VERSION 5.8 ;
BUSBITCHARS "[]" ;
DIVIDERCHAR "/" ;
UNITS
    DATABASE MICRONS 1000 ;
END UNITS

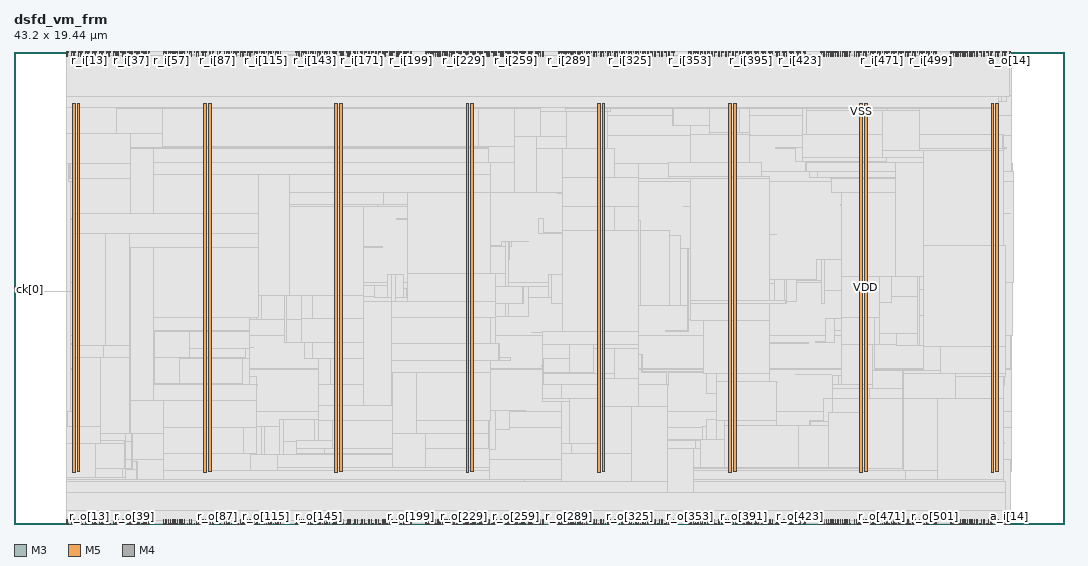
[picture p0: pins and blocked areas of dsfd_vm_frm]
MACRO dsfd_vm_frm
  FOREIGN dsfd_vm_frm 0 0 ;
  CLASS BLOCK ;
  SIZE 43.2 BY 19.44 ;
  PIN a_i[0]
    DIRECTION INPUT ;
    USE SIGNAL ;
    PORT
      LAYER M3 ;
        RECT  40.032 0 40.05 0.038 ;
    END
  END a_i[0]
  PIN a_i[10]
    DIRECTION INPUT ;
    USE SIGNAL ;
    PORT
      LAYER M3 ;
        RECT  40.68 0 40.698 0.038 ;
    END
  END a_i[10]
  PIN a_i[11]
    DIRECTION INPUT ;
    USE SIGNAL ;
    PORT
      LAYER M5 ;
        RECT  40.752 0 40.776 0.192 ;
    END
  END a_i[11]
  PIN a_i[12]
    DIRECTION INPUT ;
    USE SIGNAL ;
    PORT
      LAYER M3 ;
        RECT  40.824 0 40.842 0.038 ;
    END
  END a_i[12]
  PIN a_i[13]
    DIRECTION INPUT ;
    USE SIGNAL ;
    PORT
      LAYER M5 ;
        RECT  40.944 0 40.968 0.192 ;
    END
  END a_i[13]
  PIN a_i[14]
    DIRECTION INPUT ;
    USE SIGNAL ;
    PORT
      LAYER M3 ;
        RECT  40.968 0 40.986 0.038 ;
    END
  END a_i[14]
  PIN a_i[1]
    DIRECTION INPUT ;
    USE SIGNAL ;
    PORT
      LAYER M5 ;
        RECT  40.08 0 40.104 0.192 ;
    END
  END a_i[1]
  PIN a_i[2]
    DIRECTION INPUT ;
    USE SIGNAL ;
    PORT
      LAYER M3 ;
        RECT  40.176 0 40.194 0.038 ;
    END
  END a_i[2]
  PIN a_i[3]
    DIRECTION INPUT ;
    USE SIGNAL ;
    PORT
      LAYER M5 ;
        RECT  40.176 0 40.2 0.192 ;
    END
  END a_i[3]
  PIN a_i[4]
    DIRECTION INPUT ;
    USE SIGNAL ;
    PORT
      LAYER M3 ;
        RECT  40.248 0 40.266 0.038 ;
    END
  END a_i[4]
  PIN a_i[5]
    DIRECTION INPUT ;
    USE SIGNAL ;
    PORT
      LAYER M5 ;
        RECT  40.368 0 40.392 0.192 ;
    END
  END a_i[5]
  PIN a_i[6]
    DIRECTION INPUT ;
    USE SIGNAL ;
    PORT
      LAYER M3 ;
        RECT  40.392 0 40.41 0.038 ;
    END
  END a_i[6]
  PIN a_i[7]
    DIRECTION INPUT ;
    USE SIGNAL ;
    PORT
      LAYER M5 ;
        RECT  40.464 0 40.488 0.192 ;
    END
  END a_i[7]
  PIN a_i[8]
    DIRECTION INPUT ;
    USE SIGNAL ;
    PORT
      LAYER M3 ;
        RECT  40.536 0 40.554 0.038 ;
    END
  END a_i[8]
  PIN a_i[9]
    DIRECTION INPUT ;
    USE SIGNAL ;
    PORT
      LAYER M5 ;
        RECT  40.656 0 40.68 0.192 ;
    END
  END a_i[9]
  PIN a_o[0]
    DIRECTION OUTPUT ;
    USE SIGNAL ;
    PORT
      LAYER M3 ;
        RECT  40.032 19.402 40.05 19.44 ;
    END
  END a_o[0]
  PIN a_o[10]
    DIRECTION OUTPUT ;
    USE SIGNAL ;
    PORT
      LAYER M3 ;
        RECT  40.68 19.402 40.698 19.44 ;
    END
  END a_o[10]
  PIN a_o[11]
    DIRECTION OUTPUT ;
    USE SIGNAL ;
    PORT
      LAYER M5 ;
        RECT  40.752 19.248 40.776 19.44 ;
    END
  END a_o[11]
  PIN a_o[12]
    DIRECTION OUTPUT ;
    USE SIGNAL ;
    PORT
      LAYER M3 ;
        RECT  40.824 19.402 40.842 19.44 ;
    END
  END a_o[12]
  PIN a_o[13]
    DIRECTION OUTPUT ;
    USE SIGNAL ;
    PORT
      LAYER M5 ;
        RECT  40.944 19.248 40.968 19.44 ;
    END
  END a_o[13]
  PIN a_o[14]
    DIRECTION OUTPUT ;
    USE SIGNAL ;
    PORT
      LAYER M3 ;
        RECT  40.968 19.402 40.986 19.44 ;
    END
  END a_o[14]
  PIN a_o[1]
    DIRECTION OUTPUT ;
    USE SIGNAL ;
    PORT
      LAYER M5 ;
        RECT  40.08 19.248 40.104 19.44 ;
    END
  END a_o[1]
  PIN a_o[2]
    DIRECTION OUTPUT ;
    USE SIGNAL ;
    PORT
      LAYER M3 ;
        RECT  40.176 19.402 40.194 19.44 ;
    END
  END a_o[2]
  PIN a_o[3]
    DIRECTION OUTPUT ;
    USE SIGNAL ;
    PORT
      LAYER M5 ;
        RECT  40.176 19.248 40.2 19.44 ;
    END
  END a_o[3]
  PIN a_o[4]
    DIRECTION OUTPUT ;
    USE SIGNAL ;
    PORT
      LAYER M3 ;
        RECT  40.248 19.402 40.266 19.44 ;
    END
  END a_o[4]
  PIN a_o[5]
    DIRECTION OUTPUT ;
    USE SIGNAL ;
    PORT
      LAYER M5 ;
        RECT  40.368 19.248 40.392 19.44 ;
    END
  END a_o[5]
  PIN a_o[6]
    DIRECTION OUTPUT ;
    USE SIGNAL ;
    PORT
      LAYER M3 ;
        RECT  40.392 19.402 40.41 19.44 ;
    END
  END a_o[6]
  PIN a_o[7]
    DIRECTION OUTPUT ;
    USE SIGNAL ;
    PORT
      LAYER M5 ;
        RECT  40.464 19.248 40.488 19.44 ;
    END
  END a_o[7]
  PIN a_o[8]
    DIRECTION OUTPUT ;
    USE SIGNAL ;
    PORT
      LAYER M3 ;
        RECT  40.536 19.402 40.554 19.44 ;
    END
  END a_o[8]
  PIN a_o[9]
    DIRECTION OUTPUT ;
    USE SIGNAL ;
    PORT
      LAYER M5 ;
        RECT  40.656 19.248 40.68 19.44 ;
    END
  END a_o[9]
  PIN ck[0]
    DIRECTION INPUT ;
    USE SIGNAL ;
    PORT
      LAYER M4 ;
        RECT  0 9.744 0.192 9.768 ;
    END
    PORT
      LAYER M4 ;
        RECT  0.156 9.744 0.181 9.768 ;
    END
    PORT
      LAYER M4 ;
        RECT  0.181 9.552 0.227 9.768 ;
    END
  END ck[0]
  PIN f_i[0]
    DIRECTION INPUT ;
    USE SIGNAL ;
    PORT
      LAYER M5 ;
        RECT  39.6 19.248 39.624 19.44 ;
    END
  END f_i[0]
  PIN f_i[1]
    DIRECTION INPUT ;
    USE SIGNAL ;
    PORT
      LAYER M3 ;
        RECT  39.744 19.402 39.762 19.44 ;
    END
  END f_i[1]
  PIN f_i[2]
    DIRECTION INPUT ;
    USE SIGNAL ;
    PORT
      LAYER M5 ;
        RECT  39.792 19.248 39.816 19.44 ;
    END
  END f_i[2]
  PIN f_i[3]
    DIRECTION INPUT ;
    USE SIGNAL ;
    PORT
      LAYER M3 ;
        RECT  39.888 19.402 39.906 19.44 ;
    END
  END f_i[3]
  PIN f_o[0]
    DIRECTION OUTPUT ;
    USE SIGNAL ;
    PORT
      LAYER M5 ;
        RECT  39.6 0 39.624 0.192 ;
    END
  END f_o[0]
  PIN f_o[1]
    DIRECTION OUTPUT ;
    USE SIGNAL ;
    PORT
      LAYER M3 ;
        RECT  39.744 0 39.762 0.038 ;
    END
  END f_o[1]
  PIN f_o[2]
    DIRECTION OUTPUT ;
    USE SIGNAL ;
    PORT
      LAYER M5 ;
        RECT  39.792 0 39.816 0.192 ;
    END
  END f_o[2]
  PIN f_o[3]
    DIRECTION OUTPUT ;
    USE SIGNAL ;
    PORT
      LAYER M3 ;
        RECT  39.888 0 39.906 0.038 ;
    END
  END f_o[3]
  PIN g_i[0]
    DIRECTION INPUT ;
    USE SIGNAL ;
    PORT
      LAYER M5 ;
        RECT  39.888 0 39.912 0.192 ;
    END
  END g_i[0]
  PIN g_o[0]
    DIRECTION OUTPUT ;
    USE SIGNAL ;
    PORT
      LAYER M5 ;
        RECT  39.888 19.248 39.912 19.44 ;
    END
  END g_o[0]
  PIN r_i[0]
    DIRECTION INPUT ;
    USE SIGNAL ;
    PORT
      LAYER M5 ;
        RECT  2.16 19.248 2.184 19.44 ;
    END
  END r_i[0]
  PIN r_i[100]
    DIRECTION INPUT ;
    USE SIGNAL ;
    PORT
      LAYER M5 ;
        RECT  9.312 19.248 9.336 19.44 ;
    END
  END r_i[100]
  PIN r_i[101]
    DIRECTION INPUT ;
    USE SIGNAL ;
    PORT
      LAYER M3 ;
        RECT  9.36 19.402 9.378 19.44 ;
    END
  END r_i[101]
  PIN r_i[102]
    DIRECTION INPUT ;
    USE SIGNAL ;
    PORT
      LAYER M5 ;
        RECT  9.408 19.248 9.432 19.44 ;
    END
  END r_i[102]
  PIN r_i[103]
    DIRECTION INPUT ;
    USE SIGNAL ;
    PORT
      LAYER M3 ;
        RECT  9.504 19.402 9.522 19.44 ;
    END
  END r_i[103]
  PIN r_i[104]
    DIRECTION INPUT ;
    USE SIGNAL ;
    PORT
      LAYER M5 ;
        RECT  9.6 19.248 9.624 19.44 ;
    END
  END r_i[104]
  PIN r_i[105]
    DIRECTION INPUT ;
    USE SIGNAL ;
    PORT
      LAYER M3 ;
        RECT  9.648 19.402 9.666 19.44 ;
    END
  END r_i[105]
  PIN r_i[106]
    DIRECTION INPUT ;
    USE SIGNAL ;
    PORT
      LAYER M5 ;
        RECT  9.696 19.248 9.72 19.44 ;
    END
  END r_i[106]
  PIN r_i[107]
    DIRECTION INPUT ;
    USE SIGNAL ;
    PORT
      LAYER M3 ;
        RECT  9.792 19.402 9.81 19.44 ;
    END
  END r_i[107]
  PIN r_i[108]
    DIRECTION INPUT ;
    USE SIGNAL ;
    PORT
      LAYER M5 ;
        RECT  9.888 19.248 9.912 19.44 ;
    END
  END r_i[108]
  PIN r_i[109]
    DIRECTION INPUT ;
    USE SIGNAL ;
    PORT
      LAYER M3 ;
        RECT  9.936 19.402 9.954 19.44 ;
    END
  END r_i[109]
  PIN r_i[10]
    DIRECTION INPUT ;
    USE SIGNAL ;
    PORT
      LAYER M5 ;
        RECT  2.928 19.248 2.952 19.44 ;
    END
  END r_i[10]
  PIN r_i[110]
    DIRECTION INPUT ;
    USE SIGNAL ;
    PORT
      LAYER M5 ;
        RECT  9.984 19.248 10.008 19.44 ;
    END
  END r_i[110]
  PIN r_i[111]
    DIRECTION INPUT ;
    USE SIGNAL ;
    PORT
      LAYER M3 ;
        RECT  10.08 19.402 10.098 19.44 ;
    END
  END r_i[111]
  PIN r_i[112]
    DIRECTION INPUT ;
    USE SIGNAL ;
    PORT
      LAYER M5 ;
        RECT  10.176 19.248 10.2 19.44 ;
    END
  END r_i[112]
  PIN r_i[113]
    DIRECTION INPUT ;
    USE SIGNAL ;
    PORT
      LAYER M3 ;
        RECT  10.224 19.402 10.242 19.44 ;
    END
  END r_i[113]
  PIN r_i[114]
    DIRECTION INPUT ;
    USE SIGNAL ;
    PORT
      LAYER M5 ;
        RECT  10.272 19.248 10.296 19.44 ;
    END
  END r_i[114]
  PIN r_i[115]
    DIRECTION INPUT ;
    USE SIGNAL ;
    PORT
      LAYER M3 ;
        RECT  10.368 19.402 10.386 19.44 ;
    END
  END r_i[115]
  PIN r_i[116]
    DIRECTION INPUT ;
    USE SIGNAL ;
    PORT
      LAYER M5 ;
        RECT  10.464 19.248 10.488 19.44 ;
    END
  END r_i[116]
  PIN r_i[117]
    DIRECTION INPUT ;
    USE SIGNAL ;
    PORT
      LAYER M3 ;
        RECT  10.512 19.402 10.53 19.44 ;
    END
  END r_i[117]
  PIN r_i[118]
    DIRECTION INPUT ;
    USE SIGNAL ;
    PORT
      LAYER M5 ;
        RECT  10.56 19.248 10.584 19.44 ;
    END
  END r_i[118]
  PIN r_i[119]
    DIRECTION INPUT ;
    USE SIGNAL ;
    PORT
      LAYER M3 ;
        RECT  10.656 19.402 10.674 19.44 ;
    END
  END r_i[119]
  PIN r_i[11]
    DIRECTION INPUT ;
    USE SIGNAL ;
    PORT
      LAYER M3 ;
        RECT  2.952 19.402 2.97 19.44 ;
    END
  END r_i[11]
  PIN r_i[120]
    DIRECTION INPUT ;
    USE SIGNAL ;
    PORT
      LAYER M5 ;
        RECT  10.752 19.248 10.776 19.44 ;
    END
  END r_i[120]
  PIN r_i[121]
    DIRECTION INPUT ;
    USE SIGNAL ;
    PORT
      LAYER M3 ;
        RECT  10.8 19.402 10.818 19.44 ;
    END
  END r_i[121]
  PIN r_i[122]
    DIRECTION INPUT ;
    USE SIGNAL ;
    PORT
      LAYER M5 ;
        RECT  10.848 19.248 10.872 19.44 ;
    END
  END r_i[122]
  PIN r_i[123]
    DIRECTION INPUT ;
    USE SIGNAL ;
    PORT
      LAYER M3 ;
        RECT  10.944 19.402 10.962 19.44 ;
    END
  END r_i[123]
  PIN r_i[124]
    DIRECTION INPUT ;
    USE SIGNAL ;
    PORT
      LAYER M5 ;
        RECT  10.944 19.248 10.968 19.44 ;
    END
  END r_i[124]
  PIN r_i[125]
    DIRECTION INPUT ;
    USE SIGNAL ;
    PORT
      LAYER M3 ;
        RECT  11.592 19.402 11.61 19.44 ;
    END
  END r_i[125]
  PIN r_i[126]
    DIRECTION INPUT ;
    USE SIGNAL ;
    PORT
      LAYER M5 ;
        RECT  11.616 19.248 11.64 19.44 ;
    END
  END r_i[126]
  PIN r_i[127]
    DIRECTION INPUT ;
    USE SIGNAL ;
    PORT
      LAYER M3 ;
        RECT  11.664 19.402 11.682 19.44 ;
    END
  END r_i[127]
  PIN r_i[128]
    DIRECTION INPUT ;
    USE SIGNAL ;
    PORT
      LAYER M5 ;
        RECT  11.712 19.248 11.736 19.44 ;
    END
  END r_i[128]
  PIN r_i[129]
    DIRECTION INPUT ;
    USE SIGNAL ;
    PORT
      LAYER M3 ;
        RECT  11.736 19.402 11.754 19.44 ;
    END
  END r_i[129]
  PIN r_i[12]
    DIRECTION INPUT ;
    USE SIGNAL ;
    PORT
      LAYER M5 ;
        RECT  3.024 19.248 3.048 19.44 ;
    END
  END r_i[12]
  PIN r_i[130]
    DIRECTION INPUT ;
    USE SIGNAL ;
    PORT
      LAYER M5 ;
        RECT  11.808 19.248 11.832 19.44 ;
    END
  END r_i[130]
  PIN r_i[131]
    DIRECTION INPUT ;
    USE SIGNAL ;
    PORT
      LAYER M3 ;
        RECT  11.808 19.402 11.826 19.44 ;
    END
  END r_i[131]
  PIN r_i[132]
    DIRECTION INPUT ;
    USE SIGNAL ;
    PORT
      LAYER M5 ;
        RECT  11.904 19.248 11.928 19.44 ;
    END
  END r_i[132]
  PIN r_i[133]
    DIRECTION INPUT ;
    USE SIGNAL ;
    PORT
      LAYER M3 ;
        RECT  11.88 19.402 11.898 19.44 ;
    END
  END r_i[133]
  PIN r_i[134]
    DIRECTION INPUT ;
    USE SIGNAL ;
    PORT
      LAYER M5 ;
        RECT  12 19.248 12.024 19.44 ;
    END
  END r_i[134]
  PIN r_i[135]
    DIRECTION INPUT ;
    USE SIGNAL ;
    PORT
      LAYER M3 ;
        RECT  11.952 19.402 11.97 19.44 ;
    END
  END r_i[135]
  PIN r_i[136]
    DIRECTION INPUT ;
    USE SIGNAL ;
    PORT
      LAYER M5 ;
        RECT  12.096 19.248 12.12 19.44 ;
    END
  END r_i[136]
  PIN r_i[137]
    DIRECTION INPUT ;
    USE SIGNAL ;
    PORT
      LAYER M3 ;
        RECT  12.024 19.402 12.042 19.44 ;
    END
  END r_i[137]
  PIN r_i[138]
    DIRECTION INPUT ;
    USE SIGNAL ;
    PORT
      LAYER M5 ;
        RECT  12.192 19.248 12.216 19.44 ;
    END
  END r_i[138]
  PIN r_i[139]
    DIRECTION INPUT ;
    USE SIGNAL ;
    PORT
      LAYER M3 ;
        RECT  12.096 19.402 12.114 19.44 ;
    END
  END r_i[139]
  PIN r_i[13]
    DIRECTION INPUT ;
    USE SIGNAL ;
    PORT
      LAYER M3 ;
        RECT  3.096 19.402 3.114 19.44 ;
    END
  END r_i[13]
  PIN r_i[140]
    DIRECTION INPUT ;
    USE SIGNAL ;
    PORT
      LAYER M5 ;
        RECT  12.288 19.248 12.312 19.44 ;
    END
  END r_i[140]
  PIN r_i[141]
    DIRECTION INPUT ;
    USE SIGNAL ;
    PORT
      LAYER M3 ;
        RECT  12.24 19.402 12.258 19.44 ;
    END
  END r_i[141]
  PIN r_i[142]
    DIRECTION INPUT ;
    USE SIGNAL ;
    PORT
      LAYER M5 ;
        RECT  12.384 19.248 12.408 19.44 ;
    END
  END r_i[142]
  PIN r_i[143]
    DIRECTION INPUT ;
    USE SIGNAL ;
    PORT
      LAYER M3 ;
        RECT  12.384 19.402 12.402 19.44 ;
    END
  END r_i[143]
  PIN r_i[144]
    DIRECTION INPUT ;
    USE SIGNAL ;
    PORT
      LAYER M5 ;
        RECT  12.48 19.248 12.504 19.44 ;
    END
  END r_i[144]
  PIN r_i[145]
    DIRECTION INPUT ;
    USE SIGNAL ;
    PORT
      LAYER M3 ;
        RECT  12.528 19.402 12.546 19.44 ;
    END
  END r_i[145]
  PIN r_i[146]
    DIRECTION INPUT ;
    USE SIGNAL ;
    PORT
      LAYER M5 ;
        RECT  12.576 19.248 12.6 19.44 ;
    END
  END r_i[146]
  PIN r_i[147]
    DIRECTION INPUT ;
    USE SIGNAL ;
    PORT
      LAYER M3 ;
        RECT  12.672 19.402 12.69 19.44 ;
    END
  END r_i[147]
  PIN r_i[148]
    DIRECTION INPUT ;
    USE SIGNAL ;
    PORT
      LAYER M5 ;
        RECT  12.768 19.248 12.792 19.44 ;
    END
  END r_i[148]
  PIN r_i[149]
    DIRECTION INPUT ;
    USE SIGNAL ;
    PORT
      LAYER M3 ;
        RECT  12.816 19.402 12.834 19.44 ;
    END
  END r_i[149]
  PIN r_i[14]
    DIRECTION INPUT ;
    USE SIGNAL ;
    PORT
      LAYER M5 ;
        RECT  3.216 19.248 3.24 19.44 ;
    END
  END r_i[14]
  PIN r_i[150]
    DIRECTION INPUT ;
    USE SIGNAL ;
    PORT
      LAYER M5 ;
        RECT  12.864 19.248 12.888 19.44 ;
    END
  END r_i[150]
  PIN r_i[151]
    DIRECTION INPUT ;
    USE SIGNAL ;
    PORT
      LAYER M3 ;
        RECT  12.96 19.402 12.978 19.44 ;
    END
  END r_i[151]
  PIN r_i[152]
    DIRECTION INPUT ;
    USE SIGNAL ;
    PORT
      LAYER M5 ;
        RECT  12.96 19.248 12.984 19.44 ;
    END
  END r_i[152]
  PIN r_i[153]
    DIRECTION INPUT ;
    USE SIGNAL ;
    PORT
      LAYER M3 ;
        RECT  13.104 19.402 13.122 19.44 ;
    END
  END r_i[153]
  PIN r_i[154]
    DIRECTION INPUT ;
    USE SIGNAL ;
    PORT
      LAYER M5 ;
        RECT  13.152 19.248 13.176 19.44 ;
    END
  END r_i[154]
  PIN r_i[155]
    DIRECTION INPUT ;
    USE SIGNAL ;
    PORT
      LAYER M3 ;
        RECT  13.248 19.402 13.266 19.44 ;
    END
  END r_i[155]
  PIN r_i[156]
    DIRECTION INPUT ;
    USE SIGNAL ;
    PORT
      LAYER M5 ;
        RECT  13.248 19.248 13.272 19.44 ;
    END
  END r_i[156]
  PIN r_i[157]
    DIRECTION INPUT ;
    USE SIGNAL ;
    PORT
      LAYER M3 ;
        RECT  13.392 19.402 13.41 19.44 ;
    END
  END r_i[157]
  PIN r_i[158]
    DIRECTION INPUT ;
    USE SIGNAL ;
    PORT
      LAYER M5 ;
        RECT  13.44 19.248 13.464 19.44 ;
    END
  END r_i[158]
  PIN r_i[159]
    DIRECTION INPUT ;
    USE SIGNAL ;
    PORT
      LAYER M3 ;
        RECT  13.536 19.402 13.554 19.44 ;
    END
  END r_i[159]
  PIN r_i[15]
    DIRECTION INPUT ;
    USE SIGNAL ;
    PORT
      LAYER M3 ;
        RECT  3.24 19.402 3.258 19.44 ;
    END
  END r_i[15]
  PIN r_i[160]
    DIRECTION INPUT ;
    USE SIGNAL ;
    PORT
      LAYER M5 ;
        RECT  13.536 19.248 13.56 19.44 ;
    END
  END r_i[160]
  PIN r_i[161]
    DIRECTION INPUT ;
    USE SIGNAL ;
    PORT
      LAYER M3 ;
        RECT  13.68 19.402 13.698 19.44 ;
    END
  END r_i[161]
  PIN r_i[162]
    DIRECTION INPUT ;
    USE SIGNAL ;
    PORT
      LAYER M5 ;
        RECT  13.728 19.248 13.752 19.44 ;
    END
  END r_i[162]
  PIN r_i[163]
    DIRECTION INPUT ;
    USE SIGNAL ;
    PORT
      LAYER M3 ;
        RECT  13.824 19.402 13.842 19.44 ;
    END
  END r_i[163]
  PIN r_i[164]
    DIRECTION INPUT ;
    USE SIGNAL ;
    PORT
      LAYER M5 ;
        RECT  13.824 19.248 13.848 19.44 ;
    END
  END r_i[164]
  PIN r_i[165]
    DIRECTION INPUT ;
    USE SIGNAL ;
    PORT
      LAYER M3 ;
        RECT  13.968 19.402 13.986 19.44 ;
    END
  END r_i[165]
  PIN r_i[166]
    DIRECTION INPUT ;
    USE SIGNAL ;
    PORT
      LAYER M5 ;
        RECT  14.016 19.248 14.04 19.44 ;
    END
  END r_i[166]
  PIN r_i[167]
    DIRECTION INPUT ;
    USE SIGNAL ;
    PORT
      LAYER M3 ;
        RECT  14.112 19.402 14.13 19.44 ;
    END
  END r_i[167]
  PIN r_i[168]
    DIRECTION INPUT ;
    USE SIGNAL ;
    PORT
      LAYER M5 ;
        RECT  14.112 19.248 14.136 19.44 ;
    END
  END r_i[168]
  PIN r_i[169]
    DIRECTION INPUT ;
    USE SIGNAL ;
    PORT
      LAYER M3 ;
        RECT  14.256 19.402 14.274 19.44 ;
    END
  END r_i[169]
  PIN r_i[16]
    DIRECTION INPUT ;
    USE SIGNAL ;
    PORT
      LAYER M5 ;
        RECT  3.312 19.248 3.336 19.44 ;
    END
  END r_i[16]
  PIN r_i[170]
    DIRECTION INPUT ;
    USE SIGNAL ;
    PORT
      LAYER M5 ;
        RECT  14.304 19.248 14.328 19.44 ;
    END
  END r_i[170]
  PIN r_i[171]
    DIRECTION INPUT ;
    USE SIGNAL ;
    PORT
      LAYER M3 ;
        RECT  14.328 19.402 14.346 19.44 ;
    END
  END r_i[171]
  PIN r_i[172]
    DIRECTION INPUT ;
    USE SIGNAL ;
    PORT
      LAYER M5 ;
        RECT  14.4 19.248 14.424 19.44 ;
    END
  END r_i[172]
  PIN r_i[173]
    DIRECTION INPUT ;
    USE SIGNAL ;
    PORT
      LAYER M3 ;
        RECT  14.472 19.402 14.49 19.44 ;
    END
  END r_i[173]
  PIN r_i[174]
    DIRECTION INPUT ;
    USE SIGNAL ;
    PORT
      LAYER M5 ;
        RECT  14.592 19.248 14.616 19.44 ;
    END
  END r_i[174]
  PIN r_i[175]
    DIRECTION INPUT ;
    USE SIGNAL ;
    PORT
      LAYER M3 ;
        RECT  14.616 19.402 14.634 19.44 ;
    END
  END r_i[175]
  PIN r_i[176]
    DIRECTION INPUT ;
    USE SIGNAL ;
    PORT
      LAYER M5 ;
        RECT  14.688 19.248 14.712 19.44 ;
    END
  END r_i[176]
  PIN r_i[177]
    DIRECTION INPUT ;
    USE SIGNAL ;
    PORT
      LAYER M3 ;
        RECT  14.76 19.402 14.778 19.44 ;
    END
  END r_i[177]
  PIN r_i[178]
    DIRECTION INPUT ;
    USE SIGNAL ;
    PORT
      LAYER M5 ;
        RECT  14.88 19.248 14.904 19.44 ;
    END
  END r_i[178]
  PIN r_i[179]
    DIRECTION INPUT ;
    USE SIGNAL ;
    PORT
      LAYER M3 ;
        RECT  14.904 19.402 14.922 19.44 ;
    END
  END r_i[179]
  PIN r_i[17]
    DIRECTION INPUT ;
    USE SIGNAL ;
    PORT
      LAYER M3 ;
        RECT  3.384 19.402 3.402 19.44 ;
    END
  END r_i[17]
  PIN r_i[180]
    DIRECTION INPUT ;
    USE SIGNAL ;
    PORT
      LAYER M5 ;
        RECT  14.976 19.248 15 19.44 ;
    END
  END r_i[180]
  PIN r_i[181]
    DIRECTION INPUT ;
    USE SIGNAL ;
    PORT
      LAYER M3 ;
        RECT  15.048 19.402 15.066 19.44 ;
    END
  END r_i[181]
  PIN r_i[182]
    DIRECTION INPUT ;
    USE SIGNAL ;
    PORT
      LAYER M5 ;
        RECT  15.168 19.248 15.192 19.44 ;
    END
  END r_i[182]
  PIN r_i[183]
    DIRECTION INPUT ;
    USE SIGNAL ;
    PORT
      LAYER M3 ;
        RECT  15.192 19.402 15.21 19.44 ;
    END
  END r_i[183]
  PIN r_i[184]
    DIRECTION INPUT ;
    USE SIGNAL ;
    PORT
      LAYER M5 ;
        RECT  15.264 19.248 15.288 19.44 ;
    END
  END r_i[184]
  PIN r_i[185]
    DIRECTION INPUT ;
    USE SIGNAL ;
    PORT
      LAYER M3 ;
        RECT  15.336 19.402 15.354 19.44 ;
    END
  END r_i[185]
  PIN r_i[186]
    DIRECTION INPUT ;
    USE SIGNAL ;
    PORT
      LAYER M5 ;
        RECT  15.456 19.248 15.48 19.44 ;
    END
  END r_i[186]
  PIN r_i[187]
    DIRECTION INPUT ;
    USE SIGNAL ;
    PORT
      LAYER M3 ;
        RECT  15.48 19.402 15.498 19.44 ;
    END
  END r_i[187]
  PIN r_i[188]
    DIRECTION INPUT ;
    USE SIGNAL ;
    PORT
      LAYER M5 ;
        RECT  15.552 19.248 15.576 19.44 ;
    END
  END r_i[188]
  PIN r_i[189]
    DIRECTION INPUT ;
    USE SIGNAL ;
    PORT
      LAYER M3 ;
        RECT  15.624 19.402 15.642 19.44 ;
    END
  END r_i[189]
  PIN r_i[18]
    DIRECTION INPUT ;
    USE SIGNAL ;
    PORT
      LAYER M5 ;
        RECT  3.504 19.248 3.528 19.44 ;
    END
  END r_i[18]
  PIN r_i[190]
    DIRECTION INPUT ;
    USE SIGNAL ;
    PORT
      LAYER M5 ;
        RECT  15.744 19.248 15.768 19.44 ;
    END
  END r_i[190]
  PIN r_i[191]
    DIRECTION INPUT ;
    USE SIGNAL ;
    PORT
      LAYER M3 ;
        RECT  15.768 19.402 15.786 19.44 ;
    END
  END r_i[191]
  PIN r_i[192]
    DIRECTION INPUT ;
    USE SIGNAL ;
    PORT
      LAYER M5 ;
        RECT  15.84 19.248 15.864 19.44 ;
    END
  END r_i[192]
  PIN r_i[193]
    DIRECTION INPUT ;
    USE SIGNAL ;
    PORT
      LAYER M3 ;
        RECT  15.912 19.402 15.93 19.44 ;
    END
  END r_i[193]
  PIN r_i[194]
    DIRECTION INPUT ;
    USE SIGNAL ;
    PORT
      LAYER M5 ;
        RECT  16.032 19.248 16.056 19.44 ;
    END
  END r_i[194]
  PIN r_i[195]
    DIRECTION INPUT ;
    USE SIGNAL ;
    PORT
      LAYER M3 ;
        RECT  16.056 19.402 16.074 19.44 ;
    END
  END r_i[195]
  PIN r_i[196]
    DIRECTION INPUT ;
    USE SIGNAL ;
    PORT
      LAYER M5 ;
        RECT  16.128 19.248 16.152 19.44 ;
    END
  END r_i[196]
  PIN r_i[197]
    DIRECTION INPUT ;
    USE SIGNAL ;
    PORT
      LAYER M3 ;
        RECT  16.2 19.402 16.218 19.44 ;
    END
  END r_i[197]
  PIN r_i[198]
    DIRECTION INPUT ;
    USE SIGNAL ;
    PORT
      LAYER M5 ;
        RECT  16.32 19.248 16.344 19.44 ;
    END
  END r_i[198]
  PIN r_i[199]
    DIRECTION INPUT ;
    USE SIGNAL ;
    PORT
      LAYER M3 ;
        RECT  16.344 19.402 16.362 19.44 ;
    END
  END r_i[199]
  PIN r_i[19]
    DIRECTION INPUT ;
    USE SIGNAL ;
    PORT
      LAYER M3 ;
        RECT  3.528 19.402 3.546 19.44 ;
    END
  END r_i[19]
  PIN r_i[1]
    DIRECTION INPUT ;
    USE SIGNAL ;
    PORT
      LAYER M3 ;
        RECT  2.232 19.402 2.25 19.44 ;
    END
  END r_i[1]
  PIN r_i[200]
    DIRECTION INPUT ;
    USE SIGNAL ;
    PORT
      LAYER M5 ;
        RECT  16.944 19.248 16.968 19.44 ;
    END
  END r_i[200]
  PIN r_i[201]
    DIRECTION INPUT ;
    USE SIGNAL ;
    PORT
      LAYER M3 ;
        RECT  16.992 19.402 17.01 19.44 ;
    END
  END r_i[201]
  PIN r_i[202]
    DIRECTION INPUT ;
    USE SIGNAL ;
    PORT
      LAYER M5 ;
        RECT  17.04 19.248 17.064 19.44 ;
    END
  END r_i[202]
  PIN r_i[203]
    DIRECTION INPUT ;
    USE SIGNAL ;
    PORT
      LAYER M3 ;
        RECT  17.064 19.402 17.082 19.44 ;
    END
  END r_i[203]
  PIN r_i[204]
    DIRECTION INPUT ;
    USE SIGNAL ;
    PORT
      LAYER M5 ;
        RECT  17.136 19.248 17.16 19.44 ;
    END
  END r_i[204]
  PIN r_i[205]
    DIRECTION INPUT ;
    USE SIGNAL ;
    PORT
      LAYER M3 ;
        RECT  17.136 19.402 17.154 19.44 ;
    END
  END r_i[205]
  PIN r_i[206]
    DIRECTION INPUT ;
    USE SIGNAL ;
    PORT
      LAYER M5 ;
        RECT  17.232 19.248 17.256 19.44 ;
    END
  END r_i[206]
  PIN r_i[207]
    DIRECTION INPUT ;
    USE SIGNAL ;
    PORT
      LAYER M3 ;
        RECT  17.208 19.402 17.226 19.44 ;
    END
  END r_i[207]
  PIN r_i[208]
    DIRECTION INPUT ;
    USE SIGNAL ;
    PORT
      LAYER M5 ;
        RECT  17.328 19.248 17.352 19.44 ;
    END
  END r_i[208]
  PIN r_i[209]
    DIRECTION INPUT ;
    USE SIGNAL ;
    PORT
      LAYER M3 ;
        RECT  17.28 19.402 17.298 19.44 ;
    END
  END r_i[209]
  PIN r_i[20]
    DIRECTION INPUT ;
    USE SIGNAL ;
    PORT
      LAYER M5 ;
        RECT  3.6 19.248 3.624 19.44 ;
    END
  END r_i[20]
  PIN r_i[210]
    DIRECTION INPUT ;
    USE SIGNAL ;
    PORT
      LAYER M5 ;
        RECT  17.424 19.248 17.448 19.44 ;
    END
  END r_i[210]
  PIN r_i[211]
    DIRECTION INPUT ;
    USE SIGNAL ;
    PORT
      LAYER M3 ;
        RECT  17.352 19.402 17.37 19.44 ;
    END
  END r_i[211]
  PIN r_i[212]
    DIRECTION INPUT ;
    USE SIGNAL ;
    PORT
      LAYER M5 ;
        RECT  17.52 19.248 17.544 19.44 ;
    END
  END r_i[212]
  PIN r_i[213]
    DIRECTION INPUT ;
    USE SIGNAL ;
    PORT
      LAYER M3 ;
        RECT  17.424 19.402 17.442 19.44 ;
    END
  END r_i[213]
  PIN r_i[214]
    DIRECTION INPUT ;
    USE SIGNAL ;
    PORT
      LAYER M5 ;
        RECT  17.616 19.248 17.64 19.44 ;
    END
  END r_i[214]
  PIN r_i[215]
    DIRECTION INPUT ;
    USE SIGNAL ;
    PORT
      LAYER M3 ;
        RECT  17.496 19.402 17.514 19.44 ;
    END
  END r_i[215]
  PIN r_i[216]
    DIRECTION INPUT ;
    USE SIGNAL ;
    PORT
      LAYER M5 ;
        RECT  17.712 19.248 17.736 19.44 ;
    END
  END r_i[216]
  PIN r_i[217]
    DIRECTION INPUT ;
    USE SIGNAL ;
    PORT
      LAYER M3 ;
        RECT  17.64 19.402 17.658 19.44 ;
    END
  END r_i[217]
  PIN r_i[218]
    DIRECTION INPUT ;
    USE SIGNAL ;
    PORT
      LAYER M5 ;
        RECT  17.808 19.248 17.832 19.44 ;
    END
  END r_i[218]
  PIN r_i[219]
    DIRECTION INPUT ;
    USE SIGNAL ;
    PORT
      LAYER M3 ;
        RECT  17.784 19.402 17.802 19.44 ;
    END
  END r_i[219]
  PIN r_i[21]
    DIRECTION INPUT ;
    USE SIGNAL ;
    PORT
      LAYER M3 ;
        RECT  3.672 19.402 3.69 19.44 ;
    END
  END r_i[21]
  PIN r_i[220]
    DIRECTION INPUT ;
    USE SIGNAL ;
    PORT
      LAYER M5 ;
        RECT  17.904 19.248 17.928 19.44 ;
    END
  END r_i[220]
  PIN r_i[221]
    DIRECTION INPUT ;
    USE SIGNAL ;
    PORT
      LAYER M3 ;
        RECT  17.928 19.402 17.946 19.44 ;
    END
  END r_i[221]
  PIN r_i[222]
    DIRECTION INPUT ;
    USE SIGNAL ;
    PORT
      LAYER M5 ;
        RECT  18 19.248 18.024 19.44 ;
    END
  END r_i[222]
  PIN r_i[223]
    DIRECTION INPUT ;
    USE SIGNAL ;
    PORT
      LAYER M3 ;
        RECT  18.072 19.402 18.09 19.44 ;
    END
  END r_i[223]
  PIN r_i[224]
    DIRECTION INPUT ;
    USE SIGNAL ;
    PORT
      LAYER M5 ;
        RECT  18.096 19.248 18.12 19.44 ;
    END
  END r_i[224]
  PIN r_i[225]
    DIRECTION INPUT ;
    USE SIGNAL ;
    PORT
      LAYER M3 ;
        RECT  18.216 19.402 18.234 19.44 ;
    END
  END r_i[225]
  PIN r_i[226]
    DIRECTION INPUT ;
    USE SIGNAL ;
    PORT
      LAYER M5 ;
        RECT  18.288 19.248 18.312 19.44 ;
    END
  END r_i[226]
  PIN r_i[227]
    DIRECTION INPUT ;
    USE SIGNAL ;
    PORT
      LAYER M3 ;
        RECT  18.36 19.402 18.378 19.44 ;
    END
  END r_i[227]
  PIN r_i[228]
    DIRECTION INPUT ;
    USE SIGNAL ;
    PORT
      LAYER M5 ;
        RECT  18.384 19.248 18.408 19.44 ;
    END
  END r_i[228]
  PIN r_i[229]
    DIRECTION INPUT ;
    USE SIGNAL ;
    PORT
      LAYER M3 ;
        RECT  18.504 19.402 18.522 19.44 ;
    END
  END r_i[229]
  PIN r_i[22]
    DIRECTION INPUT ;
    USE SIGNAL ;
    PORT
      LAYER M5 ;
        RECT  3.792 19.248 3.816 19.44 ;
    END
  END r_i[22]
  PIN r_i[230]
    DIRECTION INPUT ;
    USE SIGNAL ;
    PORT
      LAYER M5 ;
        RECT  18.576 19.248 18.6 19.44 ;
    END
  END r_i[230]
  PIN r_i[231]
    DIRECTION INPUT ;
    USE SIGNAL ;
    PORT
      LAYER M3 ;
        RECT  18.648 19.402 18.666 19.44 ;
    END
  END r_i[231]
  PIN r_i[232]
    DIRECTION INPUT ;
    USE SIGNAL ;
    PORT
      LAYER M5 ;
        RECT  18.672 19.248 18.696 19.44 ;
    END
  END r_i[232]
  PIN r_i[233]
    DIRECTION INPUT ;
    USE SIGNAL ;
    PORT
      LAYER M3 ;
        RECT  18.792 19.402 18.81 19.44 ;
    END
  END r_i[233]
  PIN r_i[234]
    DIRECTION INPUT ;
    USE SIGNAL ;
    PORT
      LAYER M5 ;
        RECT  18.864 19.248 18.888 19.44 ;
    END
  END r_i[234]
  PIN r_i[235]
    DIRECTION INPUT ;
    USE SIGNAL ;
    PORT
      LAYER M3 ;
        RECT  18.936 19.402 18.954 19.44 ;
    END
  END r_i[235]
  PIN r_i[236]
    DIRECTION INPUT ;
    USE SIGNAL ;
    PORT
      LAYER M5 ;
        RECT  18.96 19.248 18.984 19.44 ;
    END
  END r_i[236]
  PIN r_i[237]
    DIRECTION INPUT ;
    USE SIGNAL ;
    PORT
      LAYER M3 ;
        RECT  19.08 19.402 19.098 19.44 ;
    END
  END r_i[237]
  PIN r_i[238]
    DIRECTION INPUT ;
    USE SIGNAL ;
    PORT
      LAYER M5 ;
        RECT  19.152 19.248 19.176 19.44 ;
    END
  END r_i[238]
  PIN r_i[239]
    DIRECTION INPUT ;
    USE SIGNAL ;
    PORT
      LAYER M3 ;
        RECT  19.224 19.402 19.242 19.44 ;
    END
  END r_i[239]
  PIN r_i[23]
    DIRECTION INPUT ;
    USE SIGNAL ;
    PORT
      LAYER M3 ;
        RECT  3.816 19.402 3.834 19.44 ;
    END
  END r_i[23]
  PIN r_i[240]
    DIRECTION INPUT ;
    USE SIGNAL ;
    PORT
      LAYER M5 ;
        RECT  19.248 19.248 19.272 19.44 ;
    END
  END r_i[240]
  PIN r_i[241]
    DIRECTION INPUT ;
    USE SIGNAL ;
    PORT
      LAYER M3 ;
        RECT  19.368 19.402 19.386 19.44 ;
    END
  END r_i[241]
  PIN r_i[242]
    DIRECTION INPUT ;
    USE SIGNAL ;
    PORT
      LAYER M5 ;
        RECT  19.44 19.248 19.464 19.44 ;
    END
  END r_i[242]
  PIN r_i[243]
    DIRECTION INPUT ;
    USE SIGNAL ;
    PORT
      LAYER M3 ;
        RECT  19.512 19.402 19.53 19.44 ;
    END
  END r_i[243]
  PIN r_i[244]
    DIRECTION INPUT ;
    USE SIGNAL ;
    PORT
      LAYER M5 ;
        RECT  19.536 19.248 19.56 19.44 ;
    END
  END r_i[244]
  PIN r_i[245]
    DIRECTION INPUT ;
    USE SIGNAL ;
    PORT
      LAYER M3 ;
        RECT  19.656 19.402 19.674 19.44 ;
    END
  END r_i[245]
  PIN r_i[246]
    DIRECTION INPUT ;
    USE SIGNAL ;
    PORT
      LAYER M5 ;
        RECT  19.728 19.248 19.752 19.44 ;
    END
  END r_i[246]
  PIN r_i[247]
    DIRECTION INPUT ;
    USE SIGNAL ;
    PORT
      LAYER M3 ;
        RECT  19.8 19.402 19.818 19.44 ;
    END
  END r_i[247]
  PIN r_i[248]
    DIRECTION INPUT ;
    USE SIGNAL ;
    PORT
      LAYER M5 ;
        RECT  19.824 19.248 19.848 19.44 ;
    END
  END r_i[248]
  PIN r_i[249]
    DIRECTION INPUT ;
    USE SIGNAL ;
    PORT
      LAYER M3 ;
        RECT  19.944 19.402 19.962 19.44 ;
    END
  END r_i[249]
  PIN r_i[24]
    DIRECTION INPUT ;
    USE SIGNAL ;
    PORT
      LAYER M5 ;
        RECT  3.888 19.248 3.912 19.44 ;
    END
  END r_i[24]
  PIN r_i[250]
    DIRECTION INPUT ;
    USE SIGNAL ;
    PORT
      LAYER M5 ;
        RECT  20.016 19.248 20.04 19.44 ;
    END
  END r_i[250]
  PIN r_i[251]
    DIRECTION INPUT ;
    USE SIGNAL ;
    PORT
      LAYER M3 ;
        RECT  20.088 19.402 20.106 19.44 ;
    END
  END r_i[251]
  PIN r_i[252]
    DIRECTION INPUT ;
    USE SIGNAL ;
    PORT
      LAYER M5 ;
        RECT  20.112 19.248 20.136 19.44 ;
    END
  END r_i[252]
  PIN r_i[253]
    DIRECTION INPUT ;
    USE SIGNAL ;
    PORT
      LAYER M3 ;
        RECT  20.232 19.402 20.25 19.44 ;
    END
  END r_i[253]
  PIN r_i[254]
    DIRECTION INPUT ;
    USE SIGNAL ;
    PORT
      LAYER M5 ;
        RECT  20.304 19.248 20.328 19.44 ;
    END
  END r_i[254]
  PIN r_i[255]
    DIRECTION INPUT ;
    USE SIGNAL ;
    PORT
      LAYER M3 ;
        RECT  20.376 19.402 20.394 19.44 ;
    END
  END r_i[255]
  PIN r_i[256]
    DIRECTION INPUT ;
    USE SIGNAL ;
    PORT
      LAYER M5 ;
        RECT  20.4 19.248 20.424 19.44 ;
    END
  END r_i[256]
  PIN r_i[257]
    DIRECTION INPUT ;
    USE SIGNAL ;
    PORT
      LAYER M3 ;
        RECT  20.52 19.402 20.538 19.44 ;
    END
  END r_i[257]
  PIN r_i[258]
    DIRECTION INPUT ;
    USE SIGNAL ;
    PORT
      LAYER M5 ;
        RECT  20.592 19.248 20.616 19.44 ;
    END
  END r_i[258]
  PIN r_i[259]
    DIRECTION INPUT ;
    USE SIGNAL ;
    PORT
      LAYER M3 ;
        RECT  20.664 19.402 20.682 19.44 ;
    END
  END r_i[259]
  PIN r_i[25]
    DIRECTION INPUT ;
    USE SIGNAL ;
    PORT
      LAYER M3 ;
        RECT  3.96 19.402 3.978 19.44 ;
    END
  END r_i[25]
  PIN r_i[260]
    DIRECTION INPUT ;
    USE SIGNAL ;
    PORT
      LAYER M5 ;
        RECT  20.688 19.248 20.712 19.44 ;
    END
  END r_i[260]
  PIN r_i[261]
    DIRECTION INPUT ;
    USE SIGNAL ;
    PORT
      LAYER M3 ;
        RECT  20.808 19.402 20.826 19.44 ;
    END
  END r_i[261]
  PIN r_i[262]
    DIRECTION INPUT ;
    USE SIGNAL ;
    PORT
      LAYER M5 ;
        RECT  20.88 19.248 20.904 19.44 ;
    END
  END r_i[262]
  PIN r_i[263]
    DIRECTION INPUT ;
    USE SIGNAL ;
    PORT
      LAYER M3 ;
        RECT  20.88 19.402 20.898 19.44 ;
    END
  END r_i[263]
  PIN r_i[264]
    DIRECTION INPUT ;
    USE SIGNAL ;
    PORT
      LAYER M5 ;
        RECT  20.976 19.248 21 19.44 ;
    END
  END r_i[264]
  PIN r_i[265]
    DIRECTION INPUT ;
    USE SIGNAL ;
    PORT
      LAYER M3 ;
        RECT  21.024 19.402 21.042 19.44 ;
    END
  END r_i[265]
  PIN r_i[266]
    DIRECTION INPUT ;
    USE SIGNAL ;
    PORT
      LAYER M5 ;
        RECT  21.168 19.248 21.192 19.44 ;
    END
  END r_i[266]
  PIN r_i[267]
    DIRECTION INPUT ;
    USE SIGNAL ;
    PORT
      LAYER M3 ;
        RECT  21.168 19.402 21.186 19.44 ;
    END
  END r_i[267]
  PIN r_i[268]
    DIRECTION INPUT ;
    USE SIGNAL ;
    PORT
      LAYER M5 ;
        RECT  21.264 19.248 21.288 19.44 ;
    END
  END r_i[268]
  PIN r_i[269]
    DIRECTION INPUT ;
    USE SIGNAL ;
    PORT
      LAYER M3 ;
        RECT  21.312 19.402 21.33 19.44 ;
    END
  END r_i[269]
  PIN r_i[26]
    DIRECTION INPUT ;
    USE SIGNAL ;
    PORT
      LAYER M5 ;
        RECT  4.08 19.248 4.104 19.44 ;
    END
  END r_i[26]
  PIN r_i[270]
    DIRECTION INPUT ;
    USE SIGNAL ;
    PORT
      LAYER M5 ;
        RECT  21.456 19.248 21.48 19.44 ;
    END
  END r_i[270]
  PIN r_i[271]
    DIRECTION INPUT ;
    USE SIGNAL ;
    PORT
      LAYER M3 ;
        RECT  21.456 19.402 21.474 19.44 ;
    END
  END r_i[271]
  PIN r_i[272]
    DIRECTION INPUT ;
    USE SIGNAL ;
    PORT
      LAYER M5 ;
        RECT  21.552 19.248 21.576 19.44 ;
    END
  END r_i[272]
  PIN r_i[273]
    DIRECTION INPUT ;
    USE SIGNAL ;
    PORT
      LAYER M3 ;
        RECT  21.6 19.402 21.618 19.44 ;
    END
  END r_i[273]
  PIN r_i[274]
    DIRECTION INPUT ;
    USE SIGNAL ;
    PORT
      LAYER M5 ;
        RECT  21.648 19.248 21.672 19.44 ;
    END
  END r_i[274]
  PIN r_i[275]
    DIRECTION INPUT ;
    USE SIGNAL ;
    PORT
      LAYER M3 ;
        RECT  21.744 19.402 21.762 19.44 ;
    END
  END r_i[275]
  PIN r_i[276]
    DIRECTION INPUT ;
    USE SIGNAL ;
    PORT
      LAYER M5 ;
        RECT  21.744 19.248 21.768 19.44 ;
    END
  END r_i[276]
  PIN r_i[277]
    DIRECTION INPUT ;
    USE SIGNAL ;
    PORT
      LAYER M3 ;
        RECT  22.392 19.402 22.41 19.44 ;
    END
  END r_i[277]
  PIN r_i[278]
    DIRECTION INPUT ;
    USE SIGNAL ;
    PORT
      LAYER M5 ;
        RECT  22.416 19.248 22.44 19.44 ;
    END
  END r_i[278]
  PIN r_i[279]
    DIRECTION INPUT ;
    USE SIGNAL ;
    PORT
      LAYER M3 ;
        RECT  22.464 19.402 22.482 19.44 ;
    END
  END r_i[279]
  PIN r_i[27]
    DIRECTION INPUT ;
    USE SIGNAL ;
    PORT
      LAYER M3 ;
        RECT  4.104 19.402 4.122 19.44 ;
    END
  END r_i[27]
  PIN r_i[280]
    DIRECTION INPUT ;
    USE SIGNAL ;
    PORT
      LAYER M5 ;
        RECT  22.512 19.248 22.536 19.44 ;
    END
  END r_i[280]
  PIN r_i[281]
    DIRECTION INPUT ;
    USE SIGNAL ;
    PORT
      LAYER M3 ;
        RECT  22.536 19.402 22.554 19.44 ;
    END
  END r_i[281]
  PIN r_i[282]
    DIRECTION INPUT ;
    USE SIGNAL ;
    PORT
      LAYER M5 ;
        RECT  22.608 19.248 22.632 19.44 ;
    END
  END r_i[282]
  PIN r_i[283]
    DIRECTION INPUT ;
    USE SIGNAL ;
    PORT
      LAYER M3 ;
        RECT  22.608 19.402 22.626 19.44 ;
    END
  END r_i[283]
  PIN r_i[284]
    DIRECTION INPUT ;
    USE SIGNAL ;
    PORT
      LAYER M5 ;
        RECT  22.704 19.248 22.728 19.44 ;
    END
  END r_i[284]
  PIN r_i[285]
    DIRECTION INPUT ;
    USE SIGNAL ;
    PORT
      LAYER M3 ;
        RECT  22.68 19.402 22.698 19.44 ;
    END
  END r_i[285]
  PIN r_i[286]
    DIRECTION INPUT ;
    USE SIGNAL ;
    PORT
      LAYER M5 ;
        RECT  22.8 19.248 22.824 19.44 ;
    END
  END r_i[286]
  PIN r_i[287]
    DIRECTION INPUT ;
    USE SIGNAL ;
    PORT
      LAYER M3 ;
        RECT  22.752 19.402 22.77 19.44 ;
    END
  END r_i[287]
  PIN r_i[288]
    DIRECTION INPUT ;
    USE SIGNAL ;
    PORT
      LAYER M5 ;
        RECT  22.896 19.248 22.92 19.44 ;
    END
  END r_i[288]
  PIN r_i[289]
    DIRECTION INPUT ;
    USE SIGNAL ;
    PORT
      LAYER M3 ;
        RECT  22.824 19.402 22.842 19.44 ;
    END
  END r_i[289]
  PIN r_i[28]
    DIRECTION INPUT ;
    USE SIGNAL ;
    PORT
      LAYER M5 ;
        RECT  4.176 19.248 4.2 19.44 ;
    END
  END r_i[28]
  PIN r_i[290]
    DIRECTION INPUT ;
    USE SIGNAL ;
    PORT
      LAYER M5 ;
        RECT  22.992 19.248 23.016 19.44 ;
    END
  END r_i[290]
  PIN r_i[291]
    DIRECTION INPUT ;
    USE SIGNAL ;
    PORT
      LAYER M3 ;
        RECT  22.896 19.402 22.914 19.44 ;
    END
  END r_i[291]
  PIN r_i[292]
    DIRECTION INPUT ;
    USE SIGNAL ;
    PORT
      LAYER M5 ;
        RECT  23.088 19.248 23.112 19.44 ;
    END
  END r_i[292]
  PIN r_i[293]
    DIRECTION INPUT ;
    USE SIGNAL ;
    PORT
      LAYER M3 ;
        RECT  23.04 19.402 23.058 19.44 ;
    END
  END r_i[293]
  PIN r_i[294]
    DIRECTION INPUT ;
    USE SIGNAL ;
    PORT
      LAYER M5 ;
        RECT  23.184 19.248 23.208 19.44 ;
    END
  END r_i[294]
  PIN r_i[295]
    DIRECTION INPUT ;
    USE SIGNAL ;
    PORT
      LAYER M3 ;
        RECT  23.184 19.402 23.202 19.44 ;
    END
  END r_i[295]
  PIN r_i[296]
    DIRECTION INPUT ;
    USE SIGNAL ;
    PORT
      LAYER M5 ;
        RECT  23.28 19.248 23.304 19.44 ;
    END
  END r_i[296]
  PIN r_i[297]
    DIRECTION INPUT ;
    USE SIGNAL ;
    PORT
      LAYER M3 ;
        RECT  23.328 19.402 23.346 19.44 ;
    END
  END r_i[297]
  PIN r_i[298]
    DIRECTION INPUT ;
    USE SIGNAL ;
    PORT
      LAYER M5 ;
        RECT  23.376 19.248 23.4 19.44 ;
    END
  END r_i[298]
  PIN r_i[299]
    DIRECTION INPUT ;
    USE SIGNAL ;
    PORT
      LAYER M3 ;
        RECT  23.472 19.402 23.49 19.44 ;
    END
  END r_i[299]
  PIN r_i[29]
    DIRECTION INPUT ;
    USE SIGNAL ;
    PORT
      LAYER M3 ;
        RECT  4.248 19.402 4.266 19.44 ;
    END
  END r_i[29]
  PIN r_i[2]
    DIRECTION INPUT ;
    USE SIGNAL ;
    PORT
      LAYER M5 ;
        RECT  2.352 19.248 2.376 19.44 ;
    END
  END r_i[2]
  PIN r_i[300]
    DIRECTION INPUT ;
    USE SIGNAL ;
    PORT
      LAYER M5 ;
        RECT  23.568 19.248 23.592 19.44 ;
    END
  END r_i[300]
  PIN r_i[301]
    DIRECTION INPUT ;
    USE SIGNAL ;
    PORT
      LAYER M3 ;
        RECT  23.616 19.402 23.634 19.44 ;
    END
  END r_i[301]
  PIN r_i[302]
    DIRECTION INPUT ;
    USE SIGNAL ;
    PORT
      LAYER M5 ;
        RECT  23.664 19.248 23.688 19.44 ;
    END
  END r_i[302]
  PIN r_i[303]
    DIRECTION INPUT ;
    USE SIGNAL ;
    PORT
      LAYER M3 ;
        RECT  23.76 19.402 23.778 19.44 ;
    END
  END r_i[303]
  PIN r_i[304]
    DIRECTION INPUT ;
    USE SIGNAL ;
    PORT
      LAYER M5 ;
        RECT  23.856 19.248 23.88 19.44 ;
    END
  END r_i[304]
  PIN r_i[305]
    DIRECTION INPUT ;
    USE SIGNAL ;
    PORT
      LAYER M3 ;
        RECT  23.904 19.402 23.922 19.44 ;
    END
  END r_i[305]
  PIN r_i[306]
    DIRECTION INPUT ;
    USE SIGNAL ;
    PORT
      LAYER M5 ;
        RECT  23.952 19.248 23.976 19.44 ;
    END
  END r_i[306]
  PIN r_i[307]
    DIRECTION INPUT ;
    USE SIGNAL ;
    PORT
      LAYER M3 ;
        RECT  24.048 19.402 24.066 19.44 ;
    END
  END r_i[307]
  PIN r_i[308]
    DIRECTION INPUT ;
    USE SIGNAL ;
    PORT
      LAYER M5 ;
        RECT  24.144 19.248 24.168 19.44 ;
    END
  END r_i[308]
  PIN r_i[309]
    DIRECTION INPUT ;
    USE SIGNAL ;
    PORT
      LAYER M3 ;
        RECT  24.192 19.402 24.21 19.44 ;
    END
  END r_i[309]
  PIN r_i[30]
    DIRECTION INPUT ;
    USE SIGNAL ;
    PORT
      LAYER M5 ;
        RECT  4.272 19.248 4.296 19.44 ;
    END
  END r_i[30]
  PIN r_i[310]
    DIRECTION INPUT ;
    USE SIGNAL ;
    PORT
      LAYER M5 ;
        RECT  24.24 19.248 24.264 19.44 ;
    END
  END r_i[310]
  PIN r_i[311]
    DIRECTION INPUT ;
    USE SIGNAL ;
    PORT
      LAYER M3 ;
        RECT  24.336 19.402 24.354 19.44 ;
    END
  END r_i[311]
  PIN r_i[312]
    DIRECTION INPUT ;
    USE SIGNAL ;
    PORT
      LAYER M5 ;
        RECT  24.432 19.248 24.456 19.44 ;
    END
  END r_i[312]
  PIN r_i[313]
    DIRECTION INPUT ;
    USE SIGNAL ;
    PORT
      LAYER M3 ;
        RECT  24.48 19.402 24.498 19.44 ;
    END
  END r_i[313]
  PIN r_i[314]
    DIRECTION INPUT ;
    USE SIGNAL ;
    PORT
      LAYER M5 ;
        RECT  24.528 19.248 24.552 19.44 ;
    END
  END r_i[314]
  PIN r_i[315]
    DIRECTION INPUT ;
    USE SIGNAL ;
    PORT
      LAYER M3 ;
        RECT  24.624 19.402 24.642 19.44 ;
    END
  END r_i[315]
  PIN r_i[316]
    DIRECTION INPUT ;
    USE SIGNAL ;
    PORT
      LAYER M5 ;
        RECT  24.72 19.248 24.744 19.44 ;
    END
  END r_i[316]
  PIN r_i[317]
    DIRECTION INPUT ;
    USE SIGNAL ;
    PORT
      LAYER M3 ;
        RECT  24.768 19.402 24.786 19.44 ;
    END
  END r_i[317]
  PIN r_i[318]
    DIRECTION INPUT ;
    USE SIGNAL ;
    PORT
      LAYER M5 ;
        RECT  24.816 19.248 24.84 19.44 ;
    END
  END r_i[318]
  PIN r_i[319]
    DIRECTION INPUT ;
    USE SIGNAL ;
    PORT
      LAYER M3 ;
        RECT  24.912 19.402 24.93 19.44 ;
    END
  END r_i[319]
  PIN r_i[31]
    DIRECTION INPUT ;
    USE SIGNAL ;
    PORT
      LAYER M3 ;
        RECT  4.392 19.402 4.41 19.44 ;
    END
  END r_i[31]
  PIN r_i[320]
    DIRECTION INPUT ;
    USE SIGNAL ;
    PORT
      LAYER M5 ;
        RECT  25.008 19.248 25.032 19.44 ;
    END
  END r_i[320]
  PIN r_i[321]
    DIRECTION INPUT ;
    USE SIGNAL ;
    PORT
      LAYER M3 ;
        RECT  25.056 19.402 25.074 19.44 ;
    END
  END r_i[321]
  PIN r_i[322]
    DIRECTION INPUT ;
    USE SIGNAL ;
    PORT
      LAYER M5 ;
        RECT  25.104 19.248 25.128 19.44 ;
    END
  END r_i[322]
  PIN r_i[323]
    DIRECTION INPUT ;
    USE SIGNAL ;
    PORT
      LAYER M3 ;
        RECT  25.2 19.402 25.218 19.44 ;
    END
  END r_i[323]
  PIN r_i[324]
    DIRECTION INPUT ;
    USE SIGNAL ;
    PORT
      LAYER M5 ;
        RECT  25.296 19.248 25.32 19.44 ;
    END
  END r_i[324]
  PIN r_i[325]
    DIRECTION INPUT ;
    USE SIGNAL ;
    PORT
      LAYER M3 ;
        RECT  25.344 19.402 25.362 19.44 ;
    END
  END r_i[325]
  PIN r_i[326]
    DIRECTION INPUT ;
    USE SIGNAL ;
    PORT
      LAYER M5 ;
        RECT  25.392 19.248 25.416 19.44 ;
    END
  END r_i[326]
  PIN r_i[327]
    DIRECTION INPUT ;
    USE SIGNAL ;
    PORT
      LAYER M3 ;
        RECT  25.488 19.402 25.506 19.44 ;
    END
  END r_i[327]
  PIN r_i[328]
    DIRECTION INPUT ;
    USE SIGNAL ;
    PORT
      LAYER M5 ;
        RECT  25.584 19.248 25.608 19.44 ;
    END
  END r_i[328]
  PIN r_i[329]
    DIRECTION INPUT ;
    USE SIGNAL ;
    PORT
      LAYER M3 ;
        RECT  25.632 19.402 25.65 19.44 ;
    END
  END r_i[329]
  PIN r_i[32]
    DIRECTION INPUT ;
    USE SIGNAL ;
    PORT
      LAYER M5 ;
        RECT  4.464 19.248 4.488 19.44 ;
    END
  END r_i[32]
  PIN r_i[330]
    DIRECTION INPUT ;
    USE SIGNAL ;
    PORT
      LAYER M5 ;
        RECT  25.68 19.248 25.704 19.44 ;
    END
  END r_i[330]
  PIN r_i[331]
    DIRECTION INPUT ;
    USE SIGNAL ;
    PORT
      LAYER M3 ;
        RECT  25.776 19.402 25.794 19.44 ;
    END
  END r_i[331]
  PIN r_i[332]
    DIRECTION INPUT ;
    USE SIGNAL ;
    PORT
      LAYER M5 ;
        RECT  25.872 19.248 25.896 19.44 ;
    END
  END r_i[332]
  PIN r_i[333]
    DIRECTION INPUT ;
    USE SIGNAL ;
    PORT
      LAYER M3 ;
        RECT  25.92 19.402 25.938 19.44 ;
    END
  END r_i[333]
  PIN r_i[334]
    DIRECTION INPUT ;
    USE SIGNAL ;
    PORT
      LAYER M5 ;
        RECT  25.968 19.248 25.992 19.44 ;
    END
  END r_i[334]
  PIN r_i[335]
    DIRECTION INPUT ;
    USE SIGNAL ;
    PORT
      LAYER M3 ;
        RECT  26.064 19.402 26.082 19.44 ;
    END
  END r_i[335]
  PIN r_i[336]
    DIRECTION INPUT ;
    USE SIGNAL ;
    PORT
      LAYER M5 ;
        RECT  26.064 19.248 26.088 19.44 ;
    END
  END r_i[336]
  PIN r_i[337]
    DIRECTION INPUT ;
    USE SIGNAL ;
    PORT
      LAYER M3 ;
        RECT  26.208 19.402 26.226 19.44 ;
    END
  END r_i[337]
  PIN r_i[338]
    DIRECTION INPUT ;
    USE SIGNAL ;
    PORT
      LAYER M5 ;
        RECT  26.256 19.248 26.28 19.44 ;
    END
  END r_i[338]
  PIN r_i[339]
    DIRECTION INPUT ;
    USE SIGNAL ;
    PORT
      LAYER M3 ;
        RECT  26.352 19.402 26.37 19.44 ;
    END
  END r_i[339]
  PIN r_i[33]
    DIRECTION INPUT ;
    USE SIGNAL ;
    PORT
      LAYER M3 ;
        RECT  4.536 19.402 4.554 19.44 ;
    END
  END r_i[33]
  PIN r_i[340]
    DIRECTION INPUT ;
    USE SIGNAL ;
    PORT
      LAYER M5 ;
        RECT  26.352 19.248 26.376 19.44 ;
    END
  END r_i[340]
  PIN r_i[341]
    DIRECTION INPUT ;
    USE SIGNAL ;
    PORT
      LAYER M3 ;
        RECT  26.496 19.402 26.514 19.44 ;
    END
  END r_i[341]
  PIN r_i[342]
    DIRECTION INPUT ;
    USE SIGNAL ;
    PORT
      LAYER M5 ;
        RECT  26.544 19.248 26.568 19.44 ;
    END
  END r_i[342]
  PIN r_i[343]
    DIRECTION INPUT ;
    USE SIGNAL ;
    PORT
      LAYER M3 ;
        RECT  26.64 19.402 26.658 19.44 ;
    END
  END r_i[343]
  PIN r_i[344]
    DIRECTION INPUT ;
    USE SIGNAL ;
    PORT
      LAYER M5 ;
        RECT  26.64 19.248 26.664 19.44 ;
    END
  END r_i[344]
  PIN r_i[345]
    DIRECTION INPUT ;
    USE SIGNAL ;
    PORT
      LAYER M3 ;
        RECT  26.784 19.402 26.802 19.44 ;
    END
  END r_i[345]
  PIN r_i[346]
    DIRECTION INPUT ;
    USE SIGNAL ;
    PORT
      LAYER M5 ;
        RECT  26.832 19.248 26.856 19.44 ;
    END
  END r_i[346]
  PIN r_i[347]
    DIRECTION INPUT ;
    USE SIGNAL ;
    PORT
      LAYER M3 ;
        RECT  26.928 19.402 26.946 19.44 ;
    END
  END r_i[347]
  PIN r_i[348]
    DIRECTION INPUT ;
    USE SIGNAL ;
    PORT
      LAYER M5 ;
        RECT  26.928 19.248 26.952 19.44 ;
    END
  END r_i[348]
  PIN r_i[349]
    DIRECTION INPUT ;
    USE SIGNAL ;
    PORT
      LAYER M3 ;
        RECT  27.072 19.402 27.09 19.44 ;
    END
  END r_i[349]
  PIN r_i[34]
    DIRECTION INPUT ;
    USE SIGNAL ;
    PORT
      LAYER M5 ;
        RECT  4.56 19.248 4.584 19.44 ;
    END
  END r_i[34]
  PIN r_i[350]
    DIRECTION INPUT ;
    USE SIGNAL ;
    PORT
      LAYER M5 ;
        RECT  27.12 19.248 27.144 19.44 ;
    END
  END r_i[350]
  PIN r_i[351]
    DIRECTION INPUT ;
    USE SIGNAL ;
    PORT
      LAYER M3 ;
        RECT  27.144 19.402 27.162 19.44 ;
    END
  END r_i[351]
  PIN r_i[352]
    DIRECTION INPUT ;
    USE SIGNAL ;
    PORT
      LAYER M5 ;
        RECT  27.744 19.248 27.768 19.44 ;
    END
  END r_i[352]
  PIN r_i[353]
    DIRECTION INPUT ;
    USE SIGNAL ;
    PORT
      LAYER M3 ;
        RECT  27.792 19.402 27.81 19.44 ;
    END
  END r_i[353]
  PIN r_i[354]
    DIRECTION INPUT ;
    USE SIGNAL ;
    PORT
      LAYER M5 ;
        RECT  27.84 19.248 27.864 19.44 ;
    END
  END r_i[354]
  PIN r_i[355]
    DIRECTION INPUT ;
    USE SIGNAL ;
    PORT
      LAYER M3 ;
        RECT  27.864 19.402 27.882 19.44 ;
    END
  END r_i[355]
  PIN r_i[356]
    DIRECTION INPUT ;
    USE SIGNAL ;
    PORT
      LAYER M5 ;
        RECT  27.936 19.248 27.96 19.44 ;
    END
  END r_i[356]
  PIN r_i[357]
    DIRECTION INPUT ;
    USE SIGNAL ;
    PORT
      LAYER M3 ;
        RECT  27.936 19.402 27.954 19.44 ;
    END
  END r_i[357]
  PIN r_i[358]
    DIRECTION INPUT ;
    USE SIGNAL ;
    PORT
      LAYER M5 ;
        RECT  28.032 19.248 28.056 19.44 ;
    END
  END r_i[358]
  PIN r_i[359]
    DIRECTION INPUT ;
    USE SIGNAL ;
    PORT
      LAYER M3 ;
        RECT  28.008 19.402 28.026 19.44 ;
    END
  END r_i[359]
  PIN r_i[35]
    DIRECTION INPUT ;
    USE SIGNAL ;
    PORT
      LAYER M3 ;
        RECT  4.68 19.402 4.698 19.44 ;
    END
  END r_i[35]
  PIN r_i[360]
    DIRECTION INPUT ;
    USE SIGNAL ;
    PORT
      LAYER M5 ;
        RECT  28.128 19.248 28.152 19.44 ;
    END
  END r_i[360]
  PIN r_i[361]
    DIRECTION INPUT ;
    USE SIGNAL ;
    PORT
      LAYER M3 ;
        RECT  28.08 19.402 28.098 19.44 ;
    END
  END r_i[361]
  PIN r_i[362]
    DIRECTION INPUT ;
    USE SIGNAL ;
    PORT
      LAYER M5 ;
        RECT  28.224 19.248 28.248 19.44 ;
    END
  END r_i[362]
  PIN r_i[363]
    DIRECTION INPUT ;
    USE SIGNAL ;
    PORT
      LAYER M3 ;
        RECT  28.152 19.402 28.17 19.44 ;
    END
  END r_i[363]
  PIN r_i[364]
    DIRECTION INPUT ;
    USE SIGNAL ;
    PORT
      LAYER M5 ;
        RECT  28.32 19.248 28.344 19.44 ;
    END
  END r_i[364]
  PIN r_i[365]
    DIRECTION INPUT ;
    USE SIGNAL ;
    PORT
      LAYER M3 ;
        RECT  28.224 19.402 28.242 19.44 ;
    END
  END r_i[365]
  PIN r_i[366]
    DIRECTION INPUT ;
    USE SIGNAL ;
    PORT
      LAYER M5 ;
        RECT  28.416 19.248 28.44 19.44 ;
    END
  END r_i[366]
  PIN r_i[367]
    DIRECTION INPUT ;
    USE SIGNAL ;
    PORT
      LAYER M3 ;
        RECT  28.296 19.402 28.314 19.44 ;
    END
  END r_i[367]
  PIN r_i[368]
    DIRECTION INPUT ;
    USE SIGNAL ;
    PORT
      LAYER M5 ;
        RECT  28.512 19.248 28.536 19.44 ;
    END
  END r_i[368]
  PIN r_i[369]
    DIRECTION INPUT ;
    USE SIGNAL ;
    PORT
      LAYER M3 ;
        RECT  28.44 19.402 28.458 19.44 ;
    END
  END r_i[369]
  PIN r_i[36]
    DIRECTION INPUT ;
    USE SIGNAL ;
    PORT
      LAYER M5 ;
        RECT  4.752 19.248 4.776 19.44 ;
    END
  END r_i[36]
  PIN r_i[370]
    DIRECTION INPUT ;
    USE SIGNAL ;
    PORT
      LAYER M5 ;
        RECT  28.608 19.248 28.632 19.44 ;
    END
  END r_i[370]
  PIN r_i[371]
    DIRECTION INPUT ;
    USE SIGNAL ;
    PORT
      LAYER M3 ;
        RECT  28.584 19.402 28.602 19.44 ;
    END
  END r_i[371]
  PIN r_i[372]
    DIRECTION INPUT ;
    USE SIGNAL ;
    PORT
      LAYER M5 ;
        RECT  28.704 19.248 28.728 19.44 ;
    END
  END r_i[372]
  PIN r_i[373]
    DIRECTION INPUT ;
    USE SIGNAL ;
    PORT
      LAYER M3 ;
        RECT  28.728 19.402 28.746 19.44 ;
    END
  END r_i[373]
  PIN r_i[374]
    DIRECTION INPUT ;
    USE SIGNAL ;
    PORT
      LAYER M5 ;
        RECT  28.8 19.248 28.824 19.44 ;
    END
  END r_i[374]
  PIN r_i[375]
    DIRECTION INPUT ;
    USE SIGNAL ;
    PORT
      LAYER M3 ;
        RECT  28.872 19.402 28.89 19.44 ;
    END
  END r_i[375]
  PIN r_i[376]
    DIRECTION INPUT ;
    USE SIGNAL ;
    PORT
      LAYER M5 ;
        RECT  28.992 19.248 29.016 19.44 ;
    END
  END r_i[376]
  PIN r_i[377]
    DIRECTION INPUT ;
    USE SIGNAL ;
    PORT
      LAYER M3 ;
        RECT  29.016 19.402 29.034 19.44 ;
    END
  END r_i[377]
  PIN r_i[378]
    DIRECTION INPUT ;
    USE SIGNAL ;
    PORT
      LAYER M5 ;
        RECT  29.088 19.248 29.112 19.44 ;
    END
  END r_i[378]
  PIN r_i[379]
    DIRECTION INPUT ;
    USE SIGNAL ;
    PORT
      LAYER M3 ;
        RECT  29.16 19.402 29.178 19.44 ;
    END
  END r_i[379]
  PIN r_i[37]
    DIRECTION INPUT ;
    USE SIGNAL ;
    PORT
      LAYER M3 ;
        RECT  4.824 19.402 4.842 19.44 ;
    END
  END r_i[37]
  PIN r_i[380]
    DIRECTION INPUT ;
    USE SIGNAL ;
    PORT
      LAYER M5 ;
        RECT  29.28 19.248 29.304 19.44 ;
    END
  END r_i[380]
  PIN r_i[381]
    DIRECTION INPUT ;
    USE SIGNAL ;
    PORT
      LAYER M3 ;
        RECT  29.304 19.402 29.322 19.44 ;
    END
  END r_i[381]
  PIN r_i[382]
    DIRECTION INPUT ;
    USE SIGNAL ;
    PORT
      LAYER M5 ;
        RECT  29.376 19.248 29.4 19.44 ;
    END
  END r_i[382]
  PIN r_i[383]
    DIRECTION INPUT ;
    USE SIGNAL ;
    PORT
      LAYER M3 ;
        RECT  29.448 19.402 29.466 19.44 ;
    END
  END r_i[383]
  PIN r_i[384]
    DIRECTION INPUT ;
    USE SIGNAL ;
    PORT
      LAYER M5 ;
        RECT  29.568 19.248 29.592 19.44 ;
    END
  END r_i[384]
  PIN r_i[385]
    DIRECTION INPUT ;
    USE SIGNAL ;
    PORT
      LAYER M3 ;
        RECT  29.592 19.402 29.61 19.44 ;
    END
  END r_i[385]
  PIN r_i[386]
    DIRECTION INPUT ;
    USE SIGNAL ;
    PORT
      LAYER M5 ;
        RECT  29.664 19.248 29.688 19.44 ;
    END
  END r_i[386]
  PIN r_i[387]
    DIRECTION INPUT ;
    USE SIGNAL ;
    PORT
      LAYER M3 ;
        RECT  29.736 19.402 29.754 19.44 ;
    END
  END r_i[387]
  PIN r_i[388]
    DIRECTION INPUT ;
    USE SIGNAL ;
    PORT
      LAYER M5 ;
        RECT  29.856 19.248 29.88 19.44 ;
    END
  END r_i[388]
  PIN r_i[389]
    DIRECTION INPUT ;
    USE SIGNAL ;
    PORT
      LAYER M3 ;
        RECT  29.88 19.402 29.898 19.44 ;
    END
  END r_i[389]
  PIN r_i[38]
    DIRECTION INPUT ;
    USE SIGNAL ;
    PORT
      LAYER M5 ;
        RECT  4.848 19.248 4.872 19.44 ;
    END
  END r_i[38]
  PIN r_i[390]
    DIRECTION INPUT ;
    USE SIGNAL ;
    PORT
      LAYER M5 ;
        RECT  29.952 19.248 29.976 19.44 ;
    END
  END r_i[390]
  PIN r_i[391]
    DIRECTION INPUT ;
    USE SIGNAL ;
    PORT
      LAYER M3 ;
        RECT  30.024 19.402 30.042 19.44 ;
    END
  END r_i[391]
  PIN r_i[392]
    DIRECTION INPUT ;
    USE SIGNAL ;
    PORT
      LAYER M5 ;
        RECT  30.144 19.248 30.168 19.44 ;
    END
  END r_i[392]
  PIN r_i[393]
    DIRECTION INPUT ;
    USE SIGNAL ;
    PORT
      LAYER M3 ;
        RECT  30.168 19.402 30.186 19.44 ;
    END
  END r_i[393]
  PIN r_i[394]
    DIRECTION INPUT ;
    USE SIGNAL ;
    PORT
      LAYER M5 ;
        RECT  30.24 19.248 30.264 19.44 ;
    END
  END r_i[394]
  PIN r_i[395]
    DIRECTION INPUT ;
    USE SIGNAL ;
    PORT
      LAYER M3 ;
        RECT  30.312 19.402 30.33 19.44 ;
    END
  END r_i[395]
  PIN r_i[396]
    DIRECTION INPUT ;
    USE SIGNAL ;
    PORT
      LAYER M5 ;
        RECT  30.336 19.248 30.36 19.44 ;
    END
  END r_i[396]
  PIN r_i[397]
    DIRECTION INPUT ;
    USE SIGNAL ;
    PORT
      LAYER M3 ;
        RECT  30.456 19.402 30.474 19.44 ;
    END
  END r_i[397]
  PIN r_i[398]
    DIRECTION INPUT ;
    USE SIGNAL ;
    PORT
      LAYER M5 ;
        RECT  30.528 19.248 30.552 19.44 ;
    END
  END r_i[398]
  PIN r_i[399]
    DIRECTION INPUT ;
    USE SIGNAL ;
    PORT
      LAYER M3 ;
        RECT  30.6 19.402 30.618 19.44 ;
    END
  END r_i[399]
  PIN r_i[39]
    DIRECTION INPUT ;
    USE SIGNAL ;
    PORT
      LAYER M3 ;
        RECT  4.968 19.402 4.986 19.44 ;
    END
  END r_i[39]
  PIN r_i[3]
    DIRECTION INPUT ;
    USE SIGNAL ;
    PORT
      LAYER M3 ;
        RECT  2.376 19.402 2.394 19.44 ;
    END
  END r_i[3]
  PIN r_i[400]
    DIRECTION INPUT ;
    USE SIGNAL ;
    PORT
      LAYER M5 ;
        RECT  30.624 19.248 30.648 19.44 ;
    END
  END r_i[400]
  PIN r_i[401]
    DIRECTION INPUT ;
    USE SIGNAL ;
    PORT
      LAYER M3 ;
        RECT  30.744 19.402 30.762 19.44 ;
    END
  END r_i[401]
  PIN r_i[402]
    DIRECTION INPUT ;
    USE SIGNAL ;
    PORT
      LAYER M5 ;
        RECT  30.816 19.248 30.84 19.44 ;
    END
  END r_i[402]
  PIN r_i[403]
    DIRECTION INPUT ;
    USE SIGNAL ;
    PORT
      LAYER M3 ;
        RECT  30.888 19.402 30.906 19.44 ;
    END
  END r_i[403]
  PIN r_i[404]
    DIRECTION INPUT ;
    USE SIGNAL ;
    PORT
      LAYER M5 ;
        RECT  30.912 19.248 30.936 19.44 ;
    END
  END r_i[404]
  PIN r_i[405]
    DIRECTION INPUT ;
    USE SIGNAL ;
    PORT
      LAYER M3 ;
        RECT  31.032 19.402 31.05 19.44 ;
    END
  END r_i[405]
  PIN r_i[406]
    DIRECTION INPUT ;
    USE SIGNAL ;
    PORT
      LAYER M5 ;
        RECT  31.104 19.248 31.128 19.44 ;
    END
  END r_i[406]
  PIN r_i[407]
    DIRECTION INPUT ;
    USE SIGNAL ;
    PORT
      LAYER M3 ;
        RECT  31.176 19.402 31.194 19.44 ;
    END
  END r_i[407]
  PIN r_i[408]
    DIRECTION INPUT ;
    USE SIGNAL ;
    PORT
      LAYER M5 ;
        RECT  31.2 19.248 31.224 19.44 ;
    END
  END r_i[408]
  PIN r_i[409]
    DIRECTION INPUT ;
    USE SIGNAL ;
    PORT
      LAYER M3 ;
        RECT  31.32 19.402 31.338 19.44 ;
    END
  END r_i[409]
  PIN r_i[40]
    DIRECTION INPUT ;
    USE SIGNAL ;
    PORT
      LAYER M5 ;
        RECT  5.04 19.248 5.064 19.44 ;
    END
  END r_i[40]
  PIN r_i[410]
    DIRECTION INPUT ;
    USE SIGNAL ;
    PORT
      LAYER M5 ;
        RECT  31.392 19.248 31.416 19.44 ;
    END
  END r_i[410]
  PIN r_i[411]
    DIRECTION INPUT ;
    USE SIGNAL ;
    PORT
      LAYER M3 ;
        RECT  31.464 19.402 31.482 19.44 ;
    END
  END r_i[411]
  PIN r_i[412]
    DIRECTION INPUT ;
    USE SIGNAL ;
    PORT
      LAYER M5 ;
        RECT  31.488 19.248 31.512 19.44 ;
    END
  END r_i[412]
  PIN r_i[413]
    DIRECTION INPUT ;
    USE SIGNAL ;
    PORT
      LAYER M3 ;
        RECT  31.608 19.402 31.626 19.44 ;
    END
  END r_i[413]
  PIN r_i[414]
    DIRECTION INPUT ;
    USE SIGNAL ;
    PORT
      LAYER M5 ;
        RECT  31.68 19.248 31.704 19.44 ;
    END
  END r_i[414]
  PIN r_i[415]
    DIRECTION INPUT ;
    USE SIGNAL ;
    PORT
      LAYER M3 ;
        RECT  31.752 19.402 31.77 19.44 ;
    END
  END r_i[415]
  PIN r_i[416]
    DIRECTION INPUT ;
    USE SIGNAL ;
    PORT
      LAYER M5 ;
        RECT  31.776 19.248 31.8 19.44 ;
    END
  END r_i[416]
  PIN r_i[417]
    DIRECTION INPUT ;
    USE SIGNAL ;
    PORT
      LAYER M3 ;
        RECT  31.896 19.402 31.914 19.44 ;
    END
  END r_i[417]
  PIN r_i[418]
    DIRECTION INPUT ;
    USE SIGNAL ;
    PORT
      LAYER M5 ;
        RECT  31.968 19.248 31.992 19.44 ;
    END
  END r_i[418]
  PIN r_i[419]
    DIRECTION INPUT ;
    USE SIGNAL ;
    PORT
      LAYER M3 ;
        RECT  32.04 19.402 32.058 19.44 ;
    END
  END r_i[419]
  PIN r_i[41]
    DIRECTION INPUT ;
    USE SIGNAL ;
    PORT
      LAYER M3 ;
        RECT  5.112 19.402 5.13 19.44 ;
    END
  END r_i[41]
  PIN r_i[420]
    DIRECTION INPUT ;
    USE SIGNAL ;
    PORT
      LAYER M5 ;
        RECT  32.064 19.248 32.088 19.44 ;
    END
  END r_i[420]
  PIN r_i[421]
    DIRECTION INPUT ;
    USE SIGNAL ;
    PORT
      LAYER M3 ;
        RECT  32.184 19.402 32.202 19.44 ;
    END
  END r_i[421]
  PIN r_i[422]
    DIRECTION INPUT ;
    USE SIGNAL ;
    PORT
      LAYER M5 ;
        RECT  32.256 19.248 32.28 19.44 ;
    END
  END r_i[422]
  PIN r_i[423]
    DIRECTION INPUT ;
    USE SIGNAL ;
    PORT
      LAYER M3 ;
        RECT  32.328 19.402 32.346 19.44 ;
    END
  END r_i[423]
  PIN r_i[424]
    DIRECTION INPUT ;
    USE SIGNAL ;
    PORT
      LAYER M5 ;
        RECT  32.352 19.248 32.376 19.44 ;
    END
  END r_i[424]
  PIN r_i[425]
    DIRECTION INPUT ;
    USE SIGNAL ;
    PORT
      LAYER M3 ;
        RECT  32.472 19.402 32.49 19.44 ;
    END
  END r_i[425]
  PIN r_i[426]
    DIRECTION INPUT ;
    USE SIGNAL ;
    PORT
      LAYER M5 ;
        RECT  32.544 19.248 32.568 19.44 ;
    END
  END r_i[426]
  PIN r_i[427]
    DIRECTION INPUT ;
    USE SIGNAL ;
    PORT
      LAYER M3 ;
        RECT  32.544 19.402 32.562 19.44 ;
    END
  END r_i[427]
  PIN r_i[428]
    DIRECTION INPUT ;
    USE SIGNAL ;
    PORT
      LAYER M5 ;
        RECT  33.216 19.248 33.24 19.44 ;
    END
  END r_i[428]
  PIN r_i[429]
    DIRECTION INPUT ;
    USE SIGNAL ;
    PORT
      LAYER M3 ;
        RECT  33.192 19.402 33.21 19.44 ;
    END
  END r_i[429]
  PIN r_i[42]
    DIRECTION INPUT ;
    USE SIGNAL ;
    PORT
      LAYER M5 ;
        RECT  5.136 19.248 5.16 19.44 ;
    END
  END r_i[42]
  PIN r_i[430]
    DIRECTION INPUT ;
    USE SIGNAL ;
    PORT
      LAYER M5 ;
        RECT  33.312 19.248 33.336 19.44 ;
    END
  END r_i[430]
  PIN r_i[431]
    DIRECTION INPUT ;
    USE SIGNAL ;
    PORT
      LAYER M3 ;
        RECT  33.264 19.402 33.282 19.44 ;
    END
  END r_i[431]
  PIN r_i[432]
    DIRECTION INPUT ;
    USE SIGNAL ;
    PORT
      LAYER M5 ;
        RECT  33.408 19.248 33.432 19.44 ;
    END
  END r_i[432]
  PIN r_i[433]
    DIRECTION INPUT ;
    USE SIGNAL ;
    PORT
      LAYER M3 ;
        RECT  33.336 19.402 33.354 19.44 ;
    END
  END r_i[433]
  PIN r_i[434]
    DIRECTION INPUT ;
    USE SIGNAL ;
    PORT
      LAYER M5 ;
        RECT  33.504 19.248 33.528 19.44 ;
    END
  END r_i[434]
  PIN r_i[435]
    DIRECTION INPUT ;
    USE SIGNAL ;
    PORT
      LAYER M3 ;
        RECT  33.408 19.402 33.426 19.44 ;
    END
  END r_i[435]
  PIN r_i[436]
    DIRECTION INPUT ;
    USE SIGNAL ;
    PORT
      LAYER M5 ;
        RECT  33.6 19.248 33.624 19.44 ;
    END
  END r_i[436]
  PIN r_i[437]
    DIRECTION INPUT ;
    USE SIGNAL ;
    PORT
      LAYER M3 ;
        RECT  33.48 19.402 33.498 19.44 ;
    END
  END r_i[437]
  PIN r_i[438]
    DIRECTION INPUT ;
    USE SIGNAL ;
    PORT
      LAYER M5 ;
        RECT  33.696 19.248 33.72 19.44 ;
    END
  END r_i[438]
  PIN r_i[439]
    DIRECTION INPUT ;
    USE SIGNAL ;
    PORT
      LAYER M3 ;
        RECT  33.552 19.402 33.57 19.44 ;
    END
  END r_i[439]
  PIN r_i[43]
    DIRECTION INPUT ;
    USE SIGNAL ;
    PORT
      LAYER M3 ;
        RECT  5.256 19.402 5.274 19.44 ;
    END
  END r_i[43]
  PIN r_i[440]
    DIRECTION INPUT ;
    USE SIGNAL ;
    PORT
      LAYER M5 ;
        RECT  33.792 19.248 33.816 19.44 ;
    END
  END r_i[440]
  PIN r_i[441]
    DIRECTION INPUT ;
    USE SIGNAL ;
    PORT
      LAYER M3 ;
        RECT  33.624 19.402 33.642 19.44 ;
    END
  END r_i[441]
  PIN r_i[442]
    DIRECTION INPUT ;
    USE SIGNAL ;
    PORT
      LAYER M5 ;
        RECT  33.888 19.248 33.912 19.44 ;
    END
  END r_i[442]
  PIN r_i[443]
    DIRECTION INPUT ;
    USE SIGNAL ;
    PORT
      LAYER M3 ;
        RECT  33.768 19.402 33.786 19.44 ;
    END
  END r_i[443]
  PIN r_i[444]
    DIRECTION INPUT ;
    USE SIGNAL ;
    PORT
      LAYER M5 ;
        RECT  33.984 19.248 34.008 19.44 ;
    END
  END r_i[444]
  PIN r_i[445]
    DIRECTION INPUT ;
    USE SIGNAL ;
    PORT
      LAYER M3 ;
        RECT  33.84 19.402 33.858 19.44 ;
    END
  END r_i[445]
  PIN r_i[446]
    DIRECTION INPUT ;
    USE SIGNAL ;
    PORT
      LAYER M5 ;
        RECT  34.08 19.248 34.104 19.44 ;
    END
  END r_i[446]
  PIN r_i[447]
    DIRECTION INPUT ;
    USE SIGNAL ;
    PORT
      LAYER M3 ;
        RECT  33.984 19.402 34.002 19.44 ;
    END
  END r_i[447]
  PIN r_i[448]
    DIRECTION INPUT ;
    USE SIGNAL ;
    PORT
      LAYER M5 ;
        RECT  34.176 19.248 34.2 19.44 ;
    END
  END r_i[448]
  PIN r_i[449]
    DIRECTION INPUT ;
    USE SIGNAL ;
    PORT
      LAYER M3 ;
        RECT  34.128 19.402 34.146 19.44 ;
    END
  END r_i[449]
  PIN r_i[44]
    DIRECTION INPUT ;
    USE SIGNAL ;
    PORT
      LAYER M5 ;
        RECT  5.328 19.248 5.352 19.44 ;
    END
  END r_i[44]
  PIN r_i[450]
    DIRECTION INPUT ;
    USE SIGNAL ;
    PORT
      LAYER M5 ;
        RECT  34.272 19.248 34.296 19.44 ;
    END
  END r_i[450]
  PIN r_i[451]
    DIRECTION INPUT ;
    USE SIGNAL ;
    PORT
      LAYER M3 ;
        RECT  34.272 19.402 34.29 19.44 ;
    END
  END r_i[451]
  PIN r_i[452]
    DIRECTION INPUT ;
    USE SIGNAL ;
    PORT
      LAYER M5 ;
        RECT  34.368 19.248 34.392 19.44 ;
    END
  END r_i[452]
  PIN r_i[453]
    DIRECTION INPUT ;
    USE SIGNAL ;
    PORT
      LAYER M3 ;
        RECT  34.416 19.402 34.434 19.44 ;
    END
  END r_i[453]
  PIN r_i[454]
    DIRECTION INPUT ;
    USE SIGNAL ;
    PORT
      LAYER M5 ;
        RECT  34.56 19.248 34.584 19.44 ;
    END
  END r_i[454]
  PIN r_i[455]
    DIRECTION INPUT ;
    USE SIGNAL ;
    PORT
      LAYER M3 ;
        RECT  34.56 19.402 34.578 19.44 ;
    END
  END r_i[455]
  PIN r_i[456]
    DIRECTION INPUT ;
    USE SIGNAL ;
    PORT
      LAYER M5 ;
        RECT  34.656 19.248 34.68 19.44 ;
    END
  END r_i[456]
  PIN r_i[457]
    DIRECTION INPUT ;
    USE SIGNAL ;
    PORT
      LAYER M3 ;
        RECT  34.704 19.402 34.722 19.44 ;
    END
  END r_i[457]
  PIN r_i[458]
    DIRECTION INPUT ;
    USE SIGNAL ;
    PORT
      LAYER M5 ;
        RECT  34.752 19.248 34.776 19.44 ;
    END
  END r_i[458]
  PIN r_i[459]
    DIRECTION INPUT ;
    USE SIGNAL ;
    PORT
      LAYER M3 ;
        RECT  34.848 19.402 34.866 19.44 ;
    END
  END r_i[459]
  PIN r_i[45]
    DIRECTION INPUT ;
    USE SIGNAL ;
    PORT
      LAYER M3 ;
        RECT  5.4 19.402 5.418 19.44 ;
    END
  END r_i[45]
  PIN r_i[460]
    DIRECTION INPUT ;
    USE SIGNAL ;
    PORT
      LAYER M5 ;
        RECT  34.944 19.248 34.968 19.44 ;
    END
  END r_i[460]
  PIN r_i[461]
    DIRECTION INPUT ;
    USE SIGNAL ;
    PORT
      LAYER M3 ;
        RECT  34.992 19.402 35.01 19.44 ;
    END
  END r_i[461]
  PIN r_i[462]
    DIRECTION INPUT ;
    USE SIGNAL ;
    PORT
      LAYER M5 ;
        RECT  35.04 19.248 35.064 19.44 ;
    END
  END r_i[462]
  PIN r_i[463]
    DIRECTION INPUT ;
    USE SIGNAL ;
    PORT
      LAYER M3 ;
        RECT  35.136 19.402 35.154 19.44 ;
    END
  END r_i[463]
  PIN r_i[464]
    DIRECTION INPUT ;
    USE SIGNAL ;
    PORT
      LAYER M5 ;
        RECT  35.232 19.248 35.256 19.44 ;
    END
  END r_i[464]
  PIN r_i[465]
    DIRECTION INPUT ;
    USE SIGNAL ;
    PORT
      LAYER M3 ;
        RECT  35.28 19.402 35.298 19.44 ;
    END
  END r_i[465]
  PIN r_i[466]
    DIRECTION INPUT ;
    USE SIGNAL ;
    PORT
      LAYER M5 ;
        RECT  35.328 19.248 35.352 19.44 ;
    END
  END r_i[466]
  PIN r_i[467]
    DIRECTION INPUT ;
    USE SIGNAL ;
    PORT
      LAYER M3 ;
        RECT  35.424 19.402 35.442 19.44 ;
    END
  END r_i[467]
  PIN r_i[468]
    DIRECTION INPUT ;
    USE SIGNAL ;
    PORT
      LAYER M5 ;
        RECT  35.52 19.248 35.544 19.44 ;
    END
  END r_i[468]
  PIN r_i[469]
    DIRECTION INPUT ;
    USE SIGNAL ;
    PORT
      LAYER M3 ;
        RECT  35.568 19.402 35.586 19.44 ;
    END
  END r_i[469]
  PIN r_i[46]
    DIRECTION INPUT ;
    USE SIGNAL ;
    PORT
      LAYER M5 ;
        RECT  5.424 19.248 5.448 19.44 ;
    END
  END r_i[46]
  PIN r_i[470]
    DIRECTION INPUT ;
    USE SIGNAL ;
    PORT
      LAYER M5 ;
        RECT  35.616 19.248 35.64 19.44 ;
    END
  END r_i[470]
  PIN r_i[471]
    DIRECTION INPUT ;
    USE SIGNAL ;
    PORT
      LAYER M3 ;
        RECT  35.712 19.402 35.73 19.44 ;
    END
  END r_i[471]
  PIN r_i[472]
    DIRECTION INPUT ;
    USE SIGNAL ;
    PORT
      LAYER M5 ;
        RECT  35.808 19.248 35.832 19.44 ;
    END
  END r_i[472]
  PIN r_i[473]
    DIRECTION INPUT ;
    USE SIGNAL ;
    PORT
      LAYER M3 ;
        RECT  35.856 19.402 35.874 19.44 ;
    END
  END r_i[473]
  PIN r_i[474]
    DIRECTION INPUT ;
    USE SIGNAL ;
    PORT
      LAYER M5 ;
        RECT  35.904 19.248 35.928 19.44 ;
    END
  END r_i[474]
  PIN r_i[475]
    DIRECTION INPUT ;
    USE SIGNAL ;
    PORT
      LAYER M3 ;
        RECT  36 19.402 36.018 19.44 ;
    END
  END r_i[475]
  PIN r_i[476]
    DIRECTION INPUT ;
    USE SIGNAL ;
    PORT
      LAYER M5 ;
        RECT  36.096 19.248 36.12 19.44 ;
    END
  END r_i[476]
  PIN r_i[477]
    DIRECTION INPUT ;
    USE SIGNAL ;
    PORT
      LAYER M3 ;
        RECT  36.144 19.402 36.162 19.44 ;
    END
  END r_i[477]
  PIN r_i[478]
    DIRECTION INPUT ;
    USE SIGNAL ;
    PORT
      LAYER M5 ;
        RECT  36.192 19.248 36.216 19.44 ;
    END
  END r_i[478]
  PIN r_i[479]
    DIRECTION INPUT ;
    USE SIGNAL ;
    PORT
      LAYER M3 ;
        RECT  36.288 19.402 36.306 19.44 ;
    END
  END r_i[479]
  PIN r_i[47]
    DIRECTION INPUT ;
    USE SIGNAL ;
    PORT
      LAYER M3 ;
        RECT  5.544 19.402 5.562 19.44 ;
    END
  END r_i[47]
  PIN r_i[480]
    DIRECTION INPUT ;
    USE SIGNAL ;
    PORT
      LAYER M5 ;
        RECT  36.384 19.248 36.408 19.44 ;
    END
  END r_i[480]
  PIN r_i[481]
    DIRECTION INPUT ;
    USE SIGNAL ;
    PORT
      LAYER M3 ;
        RECT  36.432 19.402 36.45 19.44 ;
    END
  END r_i[481]
  PIN r_i[482]
    DIRECTION INPUT ;
    USE SIGNAL ;
    PORT
      LAYER M5 ;
        RECT  36.48 19.248 36.504 19.44 ;
    END
  END r_i[482]
  PIN r_i[483]
    DIRECTION INPUT ;
    USE SIGNAL ;
    PORT
      LAYER M3 ;
        RECT  36.576 19.402 36.594 19.44 ;
    END
  END r_i[483]
  PIN r_i[484]
    DIRECTION INPUT ;
    USE SIGNAL ;
    PORT
      LAYER M5 ;
        RECT  36.672 19.248 36.696 19.44 ;
    END
  END r_i[484]
  PIN r_i[485]
    DIRECTION INPUT ;
    USE SIGNAL ;
    PORT
      LAYER M3 ;
        RECT  36.72 19.402 36.738 19.44 ;
    END
  END r_i[485]
  PIN r_i[486]
    DIRECTION INPUT ;
    USE SIGNAL ;
    PORT
      LAYER M5 ;
        RECT  36.768 19.248 36.792 19.44 ;
    END
  END r_i[486]
  PIN r_i[487]
    DIRECTION INPUT ;
    USE SIGNAL ;
    PORT
      LAYER M3 ;
        RECT  36.864 19.402 36.882 19.44 ;
    END
  END r_i[487]
  PIN r_i[488]
    DIRECTION INPUT ;
    USE SIGNAL ;
    PORT
      LAYER M5 ;
        RECT  36.96 19.248 36.984 19.44 ;
    END
  END r_i[488]
  PIN r_i[489]
    DIRECTION INPUT ;
    USE SIGNAL ;
    PORT
      LAYER M3 ;
        RECT  37.008 19.402 37.026 19.44 ;
    END
  END r_i[489]
  PIN r_i[48]
    DIRECTION INPUT ;
    USE SIGNAL ;
    PORT
      LAYER M5 ;
        RECT  5.52 19.248 5.544 19.44 ;
    END
  END r_i[48]
  PIN r_i[490]
    DIRECTION INPUT ;
    USE SIGNAL ;
    PORT
      LAYER M5 ;
        RECT  37.056 19.248 37.08 19.44 ;
    END
  END r_i[490]
  PIN r_i[491]
    DIRECTION INPUT ;
    USE SIGNAL ;
    PORT
      LAYER M3 ;
        RECT  37.152 19.402 37.17 19.44 ;
    END
  END r_i[491]
  PIN r_i[492]
    DIRECTION INPUT ;
    USE SIGNAL ;
    PORT
      LAYER M5 ;
        RECT  37.248 19.248 37.272 19.44 ;
    END
  END r_i[492]
  PIN r_i[493]
    DIRECTION INPUT ;
    USE SIGNAL ;
    PORT
      LAYER M3 ;
        RECT  37.296 19.402 37.314 19.44 ;
    END
  END r_i[493]
  PIN r_i[494]
    DIRECTION INPUT ;
    USE SIGNAL ;
    PORT
      LAYER M5 ;
        RECT  37.344 19.248 37.368 19.44 ;
    END
  END r_i[494]
  PIN r_i[495]
    DIRECTION INPUT ;
    USE SIGNAL ;
    PORT
      LAYER M3 ;
        RECT  37.44 19.402 37.458 19.44 ;
    END
  END r_i[495]
  PIN r_i[496]
    DIRECTION INPUT ;
    USE SIGNAL ;
    PORT
      LAYER M5 ;
        RECT  37.536 19.248 37.56 19.44 ;
    END
  END r_i[496]
  PIN r_i[497]
    DIRECTION INPUT ;
    USE SIGNAL ;
    PORT
      LAYER M3 ;
        RECT  37.584 19.402 37.602 19.44 ;
    END
  END r_i[497]
  PIN r_i[498]
    DIRECTION INPUT ;
    USE SIGNAL ;
    PORT
      LAYER M5 ;
        RECT  37.632 19.248 37.656 19.44 ;
    END
  END r_i[498]
  PIN r_i[499]
    DIRECTION INPUT ;
    USE SIGNAL ;
    PORT
      LAYER M3 ;
        RECT  37.728 19.402 37.746 19.44 ;
    END
  END r_i[499]
  PIN r_i[49]
    DIRECTION INPUT ;
    USE SIGNAL ;
    PORT
      LAYER M3 ;
        RECT  6.192 19.402 6.21 19.44 ;
    END
  END r_i[49]
  PIN r_i[4]
    DIRECTION INPUT ;
    USE SIGNAL ;
    PORT
      LAYER M5 ;
        RECT  2.448 19.248 2.472 19.44 ;
    END
  END r_i[4]
  PIN r_i[500]
    DIRECTION INPUT ;
    USE SIGNAL ;
    PORT
      LAYER M5 ;
        RECT  37.824 19.248 37.848 19.44 ;
    END
  END r_i[500]
  PIN r_i[501]
    DIRECTION INPUT ;
    USE SIGNAL ;
    PORT
      LAYER M3 ;
        RECT  37.872 19.402 37.89 19.44 ;
    END
  END r_i[501]
  PIN r_i[502]
    DIRECTION INPUT ;
    USE SIGNAL ;
    PORT
      LAYER M5 ;
        RECT  37.92 19.248 37.944 19.44 ;
    END
  END r_i[502]
  PIN r_i[503]
    DIRECTION INPUT ;
    USE SIGNAL ;
    PORT
      LAYER M3 ;
        RECT  37.944 19.402 37.962 19.44 ;
    END
  END r_i[503]
  PIN r_i[504]
    DIRECTION INPUT ;
    USE SIGNAL ;
    PORT
      LAYER M5 ;
        RECT  38.544 19.248 38.568 19.44 ;
    END
  END r_i[504]
  PIN r_i[505]
    DIRECTION INPUT ;
    USE SIGNAL ;
    PORT
      LAYER M3 ;
        RECT  38.592 19.402 38.61 19.44 ;
    END
  END r_i[505]
  PIN r_i[506]
    DIRECTION INPUT ;
    USE SIGNAL ;
    PORT
      LAYER M5 ;
        RECT  38.64 19.248 38.664 19.44 ;
    END
  END r_i[506]
  PIN r_i[507]
    DIRECTION INPUT ;
    USE SIGNAL ;
    PORT
      LAYER M3 ;
        RECT  38.664 19.402 38.682 19.44 ;
    END
  END r_i[507]
  PIN r_i[508]
    DIRECTION INPUT ;
    USE SIGNAL ;
    PORT
      LAYER M5 ;
        RECT  38.736 19.248 38.76 19.44 ;
    END
  END r_i[508]
  PIN r_i[509]
    DIRECTION INPUT ;
    USE SIGNAL ;
    PORT
      LAYER M3 ;
        RECT  38.736 19.402 38.754 19.44 ;
    END
  END r_i[509]
  PIN r_i[50]
    DIRECTION INPUT ;
    USE SIGNAL ;
    PORT
      LAYER M5 ;
        RECT  6.144 19.248 6.168 19.44 ;
    END
  END r_i[50]
  PIN r_i[510]
    DIRECTION INPUT ;
    USE SIGNAL ;
    PORT
      LAYER M5 ;
        RECT  38.832 19.248 38.856 19.44 ;
    END
  END r_i[510]
  PIN r_i[511]
    DIRECTION INPUT ;
    USE SIGNAL ;
    PORT
      LAYER M3 ;
        RECT  38.808 19.402 38.826 19.44 ;
    END
  END r_i[511]
  PIN r_i[512]
    DIRECTION INPUT ;
    USE SIGNAL ;
    PORT
      LAYER M5 ;
        RECT  38.928 19.248 38.952 19.44 ;
    END
  END r_i[512]
  PIN r_i[513]
    DIRECTION INPUT ;
    USE SIGNAL ;
    PORT
      LAYER M3 ;
        RECT  38.88 19.402 38.898 19.44 ;
    END
  END r_i[513]
  PIN r_i[514]
    DIRECTION INPUT ;
    USE SIGNAL ;
    PORT
      LAYER M5 ;
        RECT  39.024 19.248 39.048 19.44 ;
    END
  END r_i[514]
  PIN r_i[515]
    DIRECTION INPUT ;
    USE SIGNAL ;
    PORT
      LAYER M3 ;
        RECT  38.952 19.402 38.97 19.44 ;
    END
  END r_i[515]
  PIN r_i[516]
    DIRECTION INPUT ;
    USE SIGNAL ;
    PORT
      LAYER M5 ;
        RECT  39.12 19.248 39.144 19.44 ;
    END
  END r_i[516]
  PIN r_i[517]
    DIRECTION INPUT ;
    USE SIGNAL ;
    PORT
      LAYER M3 ;
        RECT  39.024 19.402 39.042 19.44 ;
    END
  END r_i[517]
  PIN r_i[518]
    DIRECTION INPUT ;
    USE SIGNAL ;
    PORT
      LAYER M5 ;
        RECT  39.216 19.248 39.24 19.44 ;
    END
  END r_i[518]
  PIN r_i[519]
    DIRECTION INPUT ;
    USE SIGNAL ;
    PORT
      LAYER M3 ;
        RECT  39.168 19.402 39.186 19.44 ;
    END
  END r_i[519]
  PIN r_i[51]
    DIRECTION INPUT ;
    USE SIGNAL ;
    PORT
      LAYER M3 ;
        RECT  6.264 19.402 6.282 19.44 ;
    END
  END r_i[51]
  PIN r_i[520]
    DIRECTION INPUT ;
    USE SIGNAL ;
    PORT
      LAYER M5 ;
        RECT  39.312 19.248 39.336 19.44 ;
    END
  END r_i[520]
  PIN r_i[521]
    DIRECTION INPUT ;
    USE SIGNAL ;
    PORT
      LAYER M3 ;
        RECT  39.312 19.402 39.33 19.44 ;
    END
  END r_i[521]
  PIN r_i[522]
    DIRECTION INPUT ;
    USE SIGNAL ;
    PORT
      LAYER M5 ;
        RECT  39.408 19.248 39.432 19.44 ;
    END
  END r_i[522]
  PIN r_i[523]
    DIRECTION INPUT ;
    USE SIGNAL ;
    PORT
      LAYER M3 ;
        RECT  39.456 19.402 39.474 19.44 ;
    END
  END r_i[523]
  PIN r_i[524]
    DIRECTION INPUT ;
    USE SIGNAL ;
    PORT
      LAYER M5 ;
        RECT  39.504 19.248 39.528 19.44 ;
    END
  END r_i[524]
  PIN r_i[525]
    DIRECTION INPUT ;
    USE SIGNAL ;
    PORT
      LAYER M3 ;
        RECT  39.6 19.402 39.618 19.44 ;
    END
  END r_i[525]
  PIN r_i[52]
    DIRECTION INPUT ;
    USE SIGNAL ;
    PORT
      LAYER M5 ;
        RECT  6.24 19.248 6.264 19.44 ;
    END
  END r_i[52]
  PIN r_i[53]
    DIRECTION INPUT ;
    USE SIGNAL ;
    PORT
      LAYER M3 ;
        RECT  6.336 19.402 6.354 19.44 ;
    END
  END r_i[53]
  PIN r_i[54]
    DIRECTION INPUT ;
    USE SIGNAL ;
    PORT
      LAYER M5 ;
        RECT  6.336 19.248 6.36 19.44 ;
    END
  END r_i[54]
  PIN r_i[55]
    DIRECTION INPUT ;
    USE SIGNAL ;
    PORT
      LAYER M3 ;
        RECT  6.408 19.402 6.426 19.44 ;
    END
  END r_i[55]
  PIN r_i[56]
    DIRECTION INPUT ;
    USE SIGNAL ;
    PORT
      LAYER M5 ;
        RECT  6.432 19.248 6.456 19.44 ;
    END
  END r_i[56]
  PIN r_i[57]
    DIRECTION INPUT ;
    USE SIGNAL ;
    PORT
      LAYER M3 ;
        RECT  6.48 19.402 6.498 19.44 ;
    END
  END r_i[57]
  PIN r_i[58]
    DIRECTION INPUT ;
    USE SIGNAL ;
    PORT
      LAYER M5 ;
        RECT  6.528 19.248 6.552 19.44 ;
    END
  END r_i[58]
  PIN r_i[59]
    DIRECTION INPUT ;
    USE SIGNAL ;
    PORT
      LAYER M3 ;
        RECT  6.552 19.402 6.57 19.44 ;
    END
  END r_i[59]
  PIN r_i[5]
    DIRECTION INPUT ;
    USE SIGNAL ;
    PORT
      LAYER M3 ;
        RECT  2.52 19.402 2.538 19.44 ;
    END
  END r_i[5]
  PIN r_i[60]
    DIRECTION INPUT ;
    USE SIGNAL ;
    PORT
      LAYER M5 ;
        RECT  6.624 19.248 6.648 19.44 ;
    END
  END r_i[60]
  PIN r_i[61]
    DIRECTION INPUT ;
    USE SIGNAL ;
    PORT
      LAYER M3 ;
        RECT  6.624 19.402 6.642 19.44 ;
    END
  END r_i[61]
  PIN r_i[62]
    DIRECTION INPUT ;
    USE SIGNAL ;
    PORT
      LAYER M5 ;
        RECT  6.72 19.248 6.744 19.44 ;
    END
  END r_i[62]
  PIN r_i[63]
    DIRECTION INPUT ;
    USE SIGNAL ;
    PORT
      LAYER M3 ;
        RECT  6.696 19.402 6.714 19.44 ;
    END
  END r_i[63]
  PIN r_i[64]
    DIRECTION INPUT ;
    USE SIGNAL ;
    PORT
      LAYER M5 ;
        RECT  6.816 19.248 6.84 19.44 ;
    END
  END r_i[64]
  PIN r_i[65]
    DIRECTION INPUT ;
    USE SIGNAL ;
    PORT
      LAYER M3 ;
        RECT  6.84 19.402 6.858 19.44 ;
    END
  END r_i[65]
  PIN r_i[66]
    DIRECTION INPUT ;
    USE SIGNAL ;
    PORT
      LAYER M5 ;
        RECT  6.912 19.248 6.936 19.44 ;
    END
  END r_i[66]
  PIN r_i[67]
    DIRECTION INPUT ;
    USE SIGNAL ;
    PORT
      LAYER M3 ;
        RECT  6.984 19.402 7.002 19.44 ;
    END
  END r_i[67]
  PIN r_i[68]
    DIRECTION INPUT ;
    USE SIGNAL ;
    PORT
      LAYER M5 ;
        RECT  7.008 19.248 7.032 19.44 ;
    END
  END r_i[68]
  PIN r_i[69]
    DIRECTION INPUT ;
    USE SIGNAL ;
    PORT
      LAYER M3 ;
        RECT  7.128 19.402 7.146 19.44 ;
    END
  END r_i[69]
  PIN r_i[6]
    DIRECTION INPUT ;
    USE SIGNAL ;
    PORT
      LAYER M5 ;
        RECT  2.64 19.248 2.664 19.44 ;
    END
  END r_i[6]
  PIN r_i[70]
    DIRECTION INPUT ;
    USE SIGNAL ;
    PORT
      LAYER M5 ;
        RECT  7.2 19.248 7.224 19.44 ;
    END
  END r_i[70]
  PIN r_i[71]
    DIRECTION INPUT ;
    USE SIGNAL ;
    PORT
      LAYER M3 ;
        RECT  7.272 19.402 7.29 19.44 ;
    END
  END r_i[71]
  PIN r_i[72]
    DIRECTION INPUT ;
    USE SIGNAL ;
    PORT
      LAYER M5 ;
        RECT  7.296 19.248 7.32 19.44 ;
    END
  END r_i[72]
  PIN r_i[73]
    DIRECTION INPUT ;
    USE SIGNAL ;
    PORT
      LAYER M3 ;
        RECT  7.416 19.402 7.434 19.44 ;
    END
  END r_i[73]
  PIN r_i[74]
    DIRECTION INPUT ;
    USE SIGNAL ;
    PORT
      LAYER M5 ;
        RECT  7.488 19.248 7.512 19.44 ;
    END
  END r_i[74]
  PIN r_i[75]
    DIRECTION INPUT ;
    USE SIGNAL ;
    PORT
      LAYER M3 ;
        RECT  7.56 19.402 7.578 19.44 ;
    END
  END r_i[75]
  PIN r_i[76]
    DIRECTION INPUT ;
    USE SIGNAL ;
    PORT
      LAYER M5 ;
        RECT  7.584 19.248 7.608 19.44 ;
    END
  END r_i[76]
  PIN r_i[77]
    DIRECTION INPUT ;
    USE SIGNAL ;
    PORT
      LAYER M3 ;
        RECT  7.704 19.402 7.722 19.44 ;
    END
  END r_i[77]
  PIN r_i[78]
    DIRECTION INPUT ;
    USE SIGNAL ;
    PORT
      LAYER M5 ;
        RECT  7.776 19.248 7.8 19.44 ;
    END
  END r_i[78]
  PIN r_i[79]
    DIRECTION INPUT ;
    USE SIGNAL ;
    PORT
      LAYER M3 ;
        RECT  7.848 19.402 7.866 19.44 ;
    END
  END r_i[79]
  PIN r_i[7]
    DIRECTION INPUT ;
    USE SIGNAL ;
    PORT
      LAYER M3 ;
        RECT  2.664 19.402 2.682 19.44 ;
    END
  END r_i[7]
  PIN r_i[80]
    DIRECTION INPUT ;
    USE SIGNAL ;
    PORT
      LAYER M5 ;
        RECT  7.872 19.248 7.896 19.44 ;
    END
  END r_i[80]
  PIN r_i[81]
    DIRECTION INPUT ;
    USE SIGNAL ;
    PORT
      LAYER M3 ;
        RECT  7.92 19.402 7.938 19.44 ;
    END
  END r_i[81]
  PIN r_i[82]
    DIRECTION INPUT ;
    USE SIGNAL ;
    PORT
      LAYER M5 ;
        RECT  8.064 19.248 8.088 19.44 ;
    END
  END r_i[82]
  PIN r_i[83]
    DIRECTION INPUT ;
    USE SIGNAL ;
    PORT
      LAYER M3 ;
        RECT  8.064 19.402 8.082 19.44 ;
    END
  END r_i[83]
  PIN r_i[84]
    DIRECTION INPUT ;
    USE SIGNAL ;
    PORT
      LAYER M5 ;
        RECT  8.16 19.248 8.184 19.44 ;
    END
  END r_i[84]
  PIN r_i[85]
    DIRECTION INPUT ;
    USE SIGNAL ;
    PORT
      LAYER M3 ;
        RECT  8.208 19.402 8.226 19.44 ;
    END
  END r_i[85]
  PIN r_i[86]
    DIRECTION INPUT ;
    USE SIGNAL ;
    PORT
      LAYER M5 ;
        RECT  8.352 19.248 8.376 19.44 ;
    END
  END r_i[86]
  PIN r_i[87]
    DIRECTION INPUT ;
    USE SIGNAL ;
    PORT
      LAYER M3 ;
        RECT  8.352 19.402 8.37 19.44 ;
    END
  END r_i[87]
  PIN r_i[88]
    DIRECTION INPUT ;
    USE SIGNAL ;
    PORT
      LAYER M5 ;
        RECT  8.448 19.248 8.472 19.44 ;
    END
  END r_i[88]
  PIN r_i[89]
    DIRECTION INPUT ;
    USE SIGNAL ;
    PORT
      LAYER M3 ;
        RECT  8.496 19.402 8.514 19.44 ;
    END
  END r_i[89]
  PIN r_i[8]
    DIRECTION INPUT ;
    USE SIGNAL ;
    PORT
      LAYER M5 ;
        RECT  2.736 19.248 2.76 19.44 ;
    END
  END r_i[8]
  PIN r_i[90]
    DIRECTION INPUT ;
    USE SIGNAL ;
    PORT
      LAYER M5 ;
        RECT  8.64 19.248 8.664 19.44 ;
    END
  END r_i[90]
  PIN r_i[91]
    DIRECTION INPUT ;
    USE SIGNAL ;
    PORT
      LAYER M3 ;
        RECT  8.64 19.402 8.658 19.44 ;
    END
  END r_i[91]
  PIN r_i[92]
    DIRECTION INPUT ;
    USE SIGNAL ;
    PORT
      LAYER M5 ;
        RECT  8.736 19.248 8.76 19.44 ;
    END
  END r_i[92]
  PIN r_i[93]
    DIRECTION INPUT ;
    USE SIGNAL ;
    PORT
      LAYER M3 ;
        RECT  8.784 19.402 8.802 19.44 ;
    END
  END r_i[93]
  PIN r_i[94]
    DIRECTION INPUT ;
    USE SIGNAL ;
    PORT
      LAYER M5 ;
        RECT  8.832 19.248 8.856 19.44 ;
    END
  END r_i[94]
  PIN r_i[95]
    DIRECTION INPUT ;
    USE SIGNAL ;
    PORT
      LAYER M3 ;
        RECT  8.928 19.402 8.946 19.44 ;
    END
  END r_i[95]
  PIN r_i[96]
    DIRECTION INPUT ;
    USE SIGNAL ;
    PORT
      LAYER M5 ;
        RECT  9.024 19.248 9.048 19.44 ;
    END
  END r_i[96]
  PIN r_i[97]
    DIRECTION INPUT ;
    USE SIGNAL ;
    PORT
      LAYER M3 ;
        RECT  9.072 19.402 9.09 19.44 ;
    END
  END r_i[97]
  PIN r_i[98]
    DIRECTION INPUT ;
    USE SIGNAL ;
    PORT
      LAYER M5 ;
        RECT  9.12 19.248 9.144 19.44 ;
    END
  END r_i[98]
  PIN r_i[99]
    DIRECTION INPUT ;
    USE SIGNAL ;
    PORT
      LAYER M3 ;
        RECT  9.216 19.402 9.234 19.44 ;
    END
  END r_i[99]
  PIN r_i[9]
    DIRECTION INPUT ;
    USE SIGNAL ;
    PORT
      LAYER M3 ;
        RECT  2.808 19.402 2.826 19.44 ;
    END
  END r_i[9]
  PIN r_o[0]
    DIRECTION OUTPUT ;
    USE SIGNAL ;
    PORT
      LAYER M5 ;
        RECT  2.16 0 2.184 0.192 ;
    END
  END r_o[0]
  PIN r_o[100]
    DIRECTION OUTPUT ;
    USE SIGNAL ;
    PORT
      LAYER M5 ;
        RECT  9.312 0 9.336 0.192 ;
    END
  END r_o[100]
  PIN r_o[101]
    DIRECTION OUTPUT ;
    USE SIGNAL ;
    PORT
      LAYER M3 ;
        RECT  9.36 0 9.378 0.038 ;
    END
  END r_o[101]
  PIN r_o[102]
    DIRECTION OUTPUT ;
    USE SIGNAL ;
    PORT
      LAYER M5 ;
        RECT  9.408 0 9.432 0.192 ;
    END
  END r_o[102]
  PIN r_o[103]
    DIRECTION OUTPUT ;
    USE SIGNAL ;
    PORT
      LAYER M3 ;
        RECT  9.504 0 9.522 0.038 ;
    END
  END r_o[103]
  PIN r_o[104]
    DIRECTION OUTPUT ;
    USE SIGNAL ;
    PORT
      LAYER M5 ;
        RECT  9.6 0 9.624 0.192 ;
    END
  END r_o[104]
  PIN r_o[105]
    DIRECTION OUTPUT ;
    USE SIGNAL ;
    PORT
      LAYER M3 ;
        RECT  9.648 0 9.666 0.038 ;
    END
  END r_o[105]
  PIN r_o[106]
    DIRECTION OUTPUT ;
    USE SIGNAL ;
    PORT
      LAYER M5 ;
        RECT  9.696 0 9.72 0.192 ;
    END
  END r_o[106]
  PIN r_o[107]
    DIRECTION OUTPUT ;
    USE SIGNAL ;
    PORT
      LAYER M3 ;
        RECT  9.792 0 9.81 0.038 ;
    END
  END r_o[107]
  PIN r_o[108]
    DIRECTION OUTPUT ;
    USE SIGNAL ;
    PORT
      LAYER M5 ;
        RECT  9.888 0 9.912 0.192 ;
    END
  END r_o[108]
  PIN r_o[109]
    DIRECTION OUTPUT ;
    USE SIGNAL ;
    PORT
      LAYER M3 ;
        RECT  9.936 0 9.954 0.038 ;
    END
  END r_o[109]
  PIN r_o[10]
    DIRECTION OUTPUT ;
    USE SIGNAL ;
    PORT
      LAYER M5 ;
        RECT  2.928 0 2.952 0.192 ;
    END
  END r_o[10]
  PIN r_o[110]
    DIRECTION OUTPUT ;
    USE SIGNAL ;
    PORT
      LAYER M5 ;
        RECT  9.984 0 10.008 0.192 ;
    END
  END r_o[110]
  PIN r_o[111]
    DIRECTION OUTPUT ;
    USE SIGNAL ;
    PORT
      LAYER M3 ;
        RECT  10.08 0 10.098 0.038 ;
    END
  END r_o[111]
  PIN r_o[112]
    DIRECTION OUTPUT ;
    USE SIGNAL ;
    PORT
      LAYER M5 ;
        RECT  10.176 0 10.2 0.192 ;
    END
  END r_o[112]
  PIN r_o[113]
    DIRECTION OUTPUT ;
    USE SIGNAL ;
    PORT
      LAYER M3 ;
        RECT  10.224 0 10.242 0.038 ;
    END
  END r_o[113]
  PIN r_o[114]
    DIRECTION OUTPUT ;
    USE SIGNAL ;
    PORT
      LAYER M5 ;
        RECT  10.272 0 10.296 0.192 ;
    END
  END r_o[114]
  PIN r_o[115]
    DIRECTION OUTPUT ;
    USE SIGNAL ;
    PORT
      LAYER M3 ;
        RECT  10.368 0 10.386 0.038 ;
    END
  END r_o[115]
  PIN r_o[116]
    DIRECTION OUTPUT ;
    USE SIGNAL ;
    PORT
      LAYER M5 ;
        RECT  10.464 0 10.488 0.192 ;
    END
  END r_o[116]
  PIN r_o[117]
    DIRECTION OUTPUT ;
    USE SIGNAL ;
    PORT
      LAYER M3 ;
        RECT  10.512 0 10.53 0.038 ;
    END
  END r_o[117]
  PIN r_o[118]
    DIRECTION OUTPUT ;
    USE SIGNAL ;
    PORT
      LAYER M5 ;
        RECT  10.56 0 10.584 0.192 ;
    END
  END r_o[118]
  PIN r_o[119]
    DIRECTION OUTPUT ;
    USE SIGNAL ;
    PORT
      LAYER M3 ;
        RECT  10.656 0 10.674 0.038 ;
    END
  END r_o[119]
  PIN r_o[11]
    DIRECTION OUTPUT ;
    USE SIGNAL ;
    PORT
      LAYER M3 ;
        RECT  2.952 0 2.97 0.038 ;
    END
  END r_o[11]
  PIN r_o[120]
    DIRECTION OUTPUT ;
    USE SIGNAL ;
    PORT
      LAYER M5 ;
        RECT  10.752 0 10.776 0.192 ;
    END
  END r_o[120]
  PIN r_o[121]
    DIRECTION OUTPUT ;
    USE SIGNAL ;
    PORT
      LAYER M3 ;
        RECT  10.8 0 10.818 0.038 ;
    END
  END r_o[121]
  PIN r_o[122]
    DIRECTION OUTPUT ;
    USE SIGNAL ;
    PORT
      LAYER M5 ;
        RECT  10.848 0 10.872 0.192 ;
    END
  END r_o[122]
  PIN r_o[123]
    DIRECTION OUTPUT ;
    USE SIGNAL ;
    PORT
      LAYER M3 ;
        RECT  10.944 0 10.962 0.038 ;
    END
  END r_o[123]
  PIN r_o[124]
    DIRECTION OUTPUT ;
    USE SIGNAL ;
    PORT
      LAYER M5 ;
        RECT  10.944 0 10.968 0.192 ;
    END
  END r_o[124]
  PIN r_o[125]
    DIRECTION OUTPUT ;
    USE SIGNAL ;
    PORT
      LAYER M3 ;
        RECT  11.592 0 11.61 0.038 ;
    END
  END r_o[125]
  PIN r_o[126]
    DIRECTION OUTPUT ;
    USE SIGNAL ;
    PORT
      LAYER M5 ;
        RECT  11.616 0 11.64 0.192 ;
    END
  END r_o[126]
  PIN r_o[127]
    DIRECTION OUTPUT ;
    USE SIGNAL ;
    PORT
      LAYER M3 ;
        RECT  11.664 0 11.682 0.038 ;
    END
  END r_o[127]
  PIN r_o[128]
    DIRECTION OUTPUT ;
    USE SIGNAL ;
    PORT
      LAYER M5 ;
        RECT  11.712 0 11.736 0.192 ;
    END
  END r_o[128]
  PIN r_o[129]
    DIRECTION OUTPUT ;
    USE SIGNAL ;
    PORT
      LAYER M3 ;
        RECT  11.736 0 11.754 0.038 ;
    END
  END r_o[129]
  PIN r_o[12]
    DIRECTION OUTPUT ;
    USE SIGNAL ;
    PORT
      LAYER M5 ;
        RECT  3.024 0 3.048 0.192 ;
    END
  END r_o[12]
  PIN r_o[130]
    DIRECTION OUTPUT ;
    USE SIGNAL ;
    PORT
      LAYER M5 ;
        RECT  11.808 0 11.832 0.192 ;
    END
  END r_o[130]
  PIN r_o[131]
    DIRECTION OUTPUT ;
    USE SIGNAL ;
    PORT
      LAYER M3 ;
        RECT  11.808 0 11.826 0.038 ;
    END
  END r_o[131]
  PIN r_o[132]
    DIRECTION OUTPUT ;
    USE SIGNAL ;
    PORT
      LAYER M5 ;
        RECT  11.904 0 11.928 0.192 ;
    END
  END r_o[132]
  PIN r_o[133]
    DIRECTION OUTPUT ;
    USE SIGNAL ;
    PORT
      LAYER M3 ;
        RECT  11.88 0 11.898 0.038 ;
    END
  END r_o[133]
  PIN r_o[134]
    DIRECTION OUTPUT ;
    USE SIGNAL ;
    PORT
      LAYER M5 ;
        RECT  12 0 12.024 0.192 ;
    END
  END r_o[134]
  PIN r_o[135]
    DIRECTION OUTPUT ;
    USE SIGNAL ;
    PORT
      LAYER M3 ;
        RECT  11.952 0 11.97 0.038 ;
    END
  END r_o[135]
  PIN r_o[136]
    DIRECTION OUTPUT ;
    USE SIGNAL ;
    PORT
      LAYER M5 ;
        RECT  12.096 0 12.12 0.192 ;
    END
  END r_o[136]
  PIN r_o[137]
    DIRECTION OUTPUT ;
    USE SIGNAL ;
    PORT
      LAYER M3 ;
        RECT  12.024 0 12.042 0.038 ;
    END
  END r_o[137]
  PIN r_o[138]
    DIRECTION OUTPUT ;
    USE SIGNAL ;
    PORT
      LAYER M5 ;
        RECT  12.192 0 12.216 0.192 ;
    END
  END r_o[138]
  PIN r_o[139]
    DIRECTION OUTPUT ;
    USE SIGNAL ;
    PORT
      LAYER M3 ;
        RECT  12.096 0 12.114 0.038 ;
    END
  END r_o[139]
  PIN r_o[13]
    DIRECTION OUTPUT ;
    USE SIGNAL ;
    PORT
      LAYER M3 ;
        RECT  3.096 0 3.114 0.038 ;
    END
  END r_o[13]
  PIN r_o[140]
    DIRECTION OUTPUT ;
    USE SIGNAL ;
    PORT
      LAYER M5 ;
        RECT  12.288 0 12.312 0.192 ;
    END
  END r_o[140]
  PIN r_o[141]
    DIRECTION OUTPUT ;
    USE SIGNAL ;
    PORT
      LAYER M3 ;
        RECT  12.24 0 12.258 0.038 ;
    END
  END r_o[141]
  PIN r_o[142]
    DIRECTION OUTPUT ;
    USE SIGNAL ;
    PORT
      LAYER M5 ;
        RECT  12.384 0 12.408 0.192 ;
    END
  END r_o[142]
  PIN r_o[143]
    DIRECTION OUTPUT ;
    USE SIGNAL ;
    PORT
      LAYER M3 ;
        RECT  12.384 0 12.402 0.038 ;
    END
  END r_o[143]
  PIN r_o[144]
    DIRECTION OUTPUT ;
    USE SIGNAL ;
    PORT
      LAYER M5 ;
        RECT  12.48 0 12.504 0.192 ;
    END
  END r_o[144]
  PIN r_o[145]
    DIRECTION OUTPUT ;
    USE SIGNAL ;
    PORT
      LAYER M3 ;
        RECT  12.528 0 12.546 0.038 ;
    END
  END r_o[145]
  PIN r_o[146]
    DIRECTION OUTPUT ;
    USE SIGNAL ;
    PORT
      LAYER M5 ;
        RECT  12.576 0 12.6 0.192 ;
    END
  END r_o[146]
  PIN r_o[147]
    DIRECTION OUTPUT ;
    USE SIGNAL ;
    PORT
      LAYER M3 ;
        RECT  12.672 0 12.69 0.038 ;
    END
  END r_o[147]
  PIN r_o[148]
    DIRECTION OUTPUT ;
    USE SIGNAL ;
    PORT
      LAYER M5 ;
        RECT  12.768 0 12.792 0.192 ;
    END
  END r_o[148]
  PIN r_o[149]
    DIRECTION OUTPUT ;
    USE SIGNAL ;
    PORT
      LAYER M3 ;
        RECT  12.816 0 12.834 0.038 ;
    END
  END r_o[149]
  PIN r_o[14]
    DIRECTION OUTPUT ;
    USE SIGNAL ;
    PORT
      LAYER M5 ;
        RECT  3.216 0 3.24 0.192 ;
    END
  END r_o[14]
  PIN r_o[150]
    DIRECTION OUTPUT ;
    USE SIGNAL ;
    PORT
      LAYER M5 ;
        RECT  12.864 0 12.888 0.192 ;
    END
  END r_o[150]
  PIN r_o[151]
    DIRECTION OUTPUT ;
    USE SIGNAL ;
    PORT
      LAYER M3 ;
        RECT  12.96 0 12.978 0.038 ;
    END
  END r_o[151]
  PIN r_o[152]
    DIRECTION OUTPUT ;
    USE SIGNAL ;
    PORT
      LAYER M5 ;
        RECT  12.96 0 12.984 0.192 ;
    END
  END r_o[152]
  PIN r_o[153]
    DIRECTION OUTPUT ;
    USE SIGNAL ;
    PORT
      LAYER M3 ;
        RECT  13.104 0 13.122 0.038 ;
    END
  END r_o[153]
  PIN r_o[154]
    DIRECTION OUTPUT ;
    USE SIGNAL ;
    PORT
      LAYER M5 ;
        RECT  13.152 0 13.176 0.192 ;
    END
  END r_o[154]
  PIN r_o[155]
    DIRECTION OUTPUT ;
    USE SIGNAL ;
    PORT
      LAYER M3 ;
        RECT  13.248 0 13.266 0.038 ;
    END
  END r_o[155]
  PIN r_o[156]
    DIRECTION OUTPUT ;
    USE SIGNAL ;
    PORT
      LAYER M5 ;
        RECT  13.248 0 13.272 0.192 ;
    END
  END r_o[156]
  PIN r_o[157]
    DIRECTION OUTPUT ;
    USE SIGNAL ;
    PORT
      LAYER M3 ;
        RECT  13.392 0 13.41 0.038 ;
    END
  END r_o[157]
  PIN r_o[158]
    DIRECTION OUTPUT ;
    USE SIGNAL ;
    PORT
      LAYER M5 ;
        RECT  13.44 0 13.464 0.192 ;
    END
  END r_o[158]
  PIN r_o[159]
    DIRECTION OUTPUT ;
    USE SIGNAL ;
    PORT
      LAYER M3 ;
        RECT  13.536 0 13.554 0.038 ;
    END
  END r_o[159]
  PIN r_o[15]
    DIRECTION OUTPUT ;
    USE SIGNAL ;
    PORT
      LAYER M3 ;
        RECT  3.24 0 3.258 0.038 ;
    END
  END r_o[15]
  PIN r_o[160]
    DIRECTION OUTPUT ;
    USE SIGNAL ;
    PORT
      LAYER M5 ;
        RECT  13.536 0 13.56 0.192 ;
    END
  END r_o[160]
  PIN r_o[161]
    DIRECTION OUTPUT ;
    USE SIGNAL ;
    PORT
      LAYER M3 ;
        RECT  13.68 0 13.698 0.038 ;
    END
  END r_o[161]
  PIN r_o[162]
    DIRECTION OUTPUT ;
    USE SIGNAL ;
    PORT
      LAYER M5 ;
        RECT  13.728 0 13.752 0.192 ;
    END
  END r_o[162]
  PIN r_o[163]
    DIRECTION OUTPUT ;
    USE SIGNAL ;
    PORT
      LAYER M3 ;
        RECT  13.824 0 13.842 0.038 ;
    END
  END r_o[163]
  PIN r_o[164]
    DIRECTION OUTPUT ;
    USE SIGNAL ;
    PORT
      LAYER M5 ;
        RECT  13.824 0 13.848 0.192 ;
    END
  END r_o[164]
  PIN r_o[165]
    DIRECTION OUTPUT ;
    USE SIGNAL ;
    PORT
      LAYER M3 ;
        RECT  13.968 0 13.986 0.038 ;
    END
  END r_o[165]
  PIN r_o[166]
    DIRECTION OUTPUT ;
    USE SIGNAL ;
    PORT
      LAYER M5 ;
        RECT  14.016 0 14.04 0.192 ;
    END
  END r_o[166]
  PIN r_o[167]
    DIRECTION OUTPUT ;
    USE SIGNAL ;
    PORT
      LAYER M3 ;
        RECT  14.112 0 14.13 0.038 ;
    END
  END r_o[167]
  PIN r_o[168]
    DIRECTION OUTPUT ;
    USE SIGNAL ;
    PORT
      LAYER M5 ;
        RECT  14.112 0 14.136 0.192 ;
    END
  END r_o[168]
  PIN r_o[169]
    DIRECTION OUTPUT ;
    USE SIGNAL ;
    PORT
      LAYER M3 ;
        RECT  14.256 0 14.274 0.038 ;
    END
  END r_o[169]
  PIN r_o[16]
    DIRECTION OUTPUT ;
    USE SIGNAL ;
    PORT
      LAYER M5 ;
        RECT  3.312 0 3.336 0.192 ;
    END
  END r_o[16]
  PIN r_o[170]
    DIRECTION OUTPUT ;
    USE SIGNAL ;
    PORT
      LAYER M5 ;
        RECT  14.304 0 14.328 0.192 ;
    END
  END r_o[170]
  PIN r_o[171]
    DIRECTION OUTPUT ;
    USE SIGNAL ;
    PORT
      LAYER M3 ;
        RECT  14.328 0 14.346 0.038 ;
    END
  END r_o[171]
  PIN r_o[172]
    DIRECTION OUTPUT ;
    USE SIGNAL ;
    PORT
      LAYER M5 ;
        RECT  14.4 0 14.424 0.192 ;
    END
  END r_o[172]
  PIN r_o[173]
    DIRECTION OUTPUT ;
    USE SIGNAL ;
    PORT
      LAYER M3 ;
        RECT  14.472 0 14.49 0.038 ;
    END
  END r_o[173]
  PIN r_o[174]
    DIRECTION OUTPUT ;
    USE SIGNAL ;
    PORT
      LAYER M5 ;
        RECT  14.592 0 14.616 0.192 ;
    END
  END r_o[174]
  PIN r_o[175]
    DIRECTION OUTPUT ;
    USE SIGNAL ;
    PORT
      LAYER M3 ;
        RECT  14.616 0 14.634 0.038 ;
    END
  END r_o[175]
  PIN r_o[176]
    DIRECTION OUTPUT ;
    USE SIGNAL ;
    PORT
      LAYER M5 ;
        RECT  14.688 0 14.712 0.192 ;
    END
  END r_o[176]
  PIN r_o[177]
    DIRECTION OUTPUT ;
    USE SIGNAL ;
    PORT
      LAYER M3 ;
        RECT  14.76 0 14.778 0.038 ;
    END
  END r_o[177]
  PIN r_o[178]
    DIRECTION OUTPUT ;
    USE SIGNAL ;
    PORT
      LAYER M5 ;
        RECT  14.88 0 14.904 0.192 ;
    END
  END r_o[178]
  PIN r_o[179]
    DIRECTION OUTPUT ;
    USE SIGNAL ;
    PORT
      LAYER M3 ;
        RECT  14.904 0 14.922 0.038 ;
    END
  END r_o[179]
  PIN r_o[17]
    DIRECTION OUTPUT ;
    USE SIGNAL ;
    PORT
      LAYER M3 ;
        RECT  3.384 0 3.402 0.038 ;
    END
  END r_o[17]
  PIN r_o[180]
    DIRECTION OUTPUT ;
    USE SIGNAL ;
    PORT
      LAYER M5 ;
        RECT  14.976 0 15 0.192 ;
    END
  END r_o[180]
  PIN r_o[181]
    DIRECTION OUTPUT ;
    USE SIGNAL ;
    PORT
      LAYER M3 ;
        RECT  15.048 0 15.066 0.038 ;
    END
  END r_o[181]
  PIN r_o[182]
    DIRECTION OUTPUT ;
    USE SIGNAL ;
    PORT
      LAYER M5 ;
        RECT  15.168 0 15.192 0.192 ;
    END
  END r_o[182]
  PIN r_o[183]
    DIRECTION OUTPUT ;
    USE SIGNAL ;
    PORT
      LAYER M3 ;
        RECT  15.192 0 15.21 0.038 ;
    END
  END r_o[183]
  PIN r_o[184]
    DIRECTION OUTPUT ;
    USE SIGNAL ;
    PORT
      LAYER M5 ;
        RECT  15.264 0 15.288 0.192 ;
    END
  END r_o[184]
  PIN r_o[185]
    DIRECTION OUTPUT ;
    USE SIGNAL ;
    PORT
      LAYER M3 ;
        RECT  15.336 0 15.354 0.038 ;
    END
  END r_o[185]
  PIN r_o[186]
    DIRECTION OUTPUT ;
    USE SIGNAL ;
    PORT
      LAYER M5 ;
        RECT  15.456 0 15.48 0.192 ;
    END
  END r_o[186]
  PIN r_o[187]
    DIRECTION OUTPUT ;
    USE SIGNAL ;
    PORT
      LAYER M3 ;
        RECT  15.48 0 15.498 0.038 ;
    END
  END r_o[187]
  PIN r_o[188]
    DIRECTION OUTPUT ;
    USE SIGNAL ;
    PORT
      LAYER M5 ;
        RECT  15.552 0 15.576 0.192 ;
    END
  END r_o[188]
  PIN r_o[189]
    DIRECTION OUTPUT ;
    USE SIGNAL ;
    PORT
      LAYER M3 ;
        RECT  15.624 0 15.642 0.038 ;
    END
  END r_o[189]
  PIN r_o[18]
    DIRECTION OUTPUT ;
    USE SIGNAL ;
    PORT
      LAYER M5 ;
        RECT  3.504 0 3.528 0.192 ;
    END
  END r_o[18]
  PIN r_o[190]
    DIRECTION OUTPUT ;
    USE SIGNAL ;
    PORT
      LAYER M5 ;
        RECT  15.744 0 15.768 0.192 ;
    END
  END r_o[190]
  PIN r_o[191]
    DIRECTION OUTPUT ;
    USE SIGNAL ;
    PORT
      LAYER M3 ;
        RECT  15.768 0 15.786 0.038 ;
    END
  END r_o[191]
  PIN r_o[192]
    DIRECTION OUTPUT ;
    USE SIGNAL ;
    PORT
      LAYER M5 ;
        RECT  15.84 0 15.864 0.192 ;
    END
  END r_o[192]
  PIN r_o[193]
    DIRECTION OUTPUT ;
    USE SIGNAL ;
    PORT
      LAYER M3 ;
        RECT  15.912 0 15.93 0.038 ;
    END
  END r_o[193]
  PIN r_o[194]
    DIRECTION OUTPUT ;
    USE SIGNAL ;
    PORT
      LAYER M5 ;
        RECT  16.032 0 16.056 0.192 ;
    END
  END r_o[194]
  PIN r_o[195]
    DIRECTION OUTPUT ;
    USE SIGNAL ;
    PORT
      LAYER M3 ;
        RECT  16.056 0 16.074 0.038 ;
    END
  END r_o[195]
  PIN r_o[196]
    DIRECTION OUTPUT ;
    USE SIGNAL ;
    PORT
      LAYER M5 ;
        RECT  16.128 0 16.152 0.192 ;
    END
  END r_o[196]
  PIN r_o[197]
    DIRECTION OUTPUT ;
    USE SIGNAL ;
    PORT
      LAYER M3 ;
        RECT  16.2 0 16.218 0.038 ;
    END
  END r_o[197]
  PIN r_o[198]
    DIRECTION OUTPUT ;
    USE SIGNAL ;
    PORT
      LAYER M5 ;
        RECT  16.32 0 16.344 0.192 ;
    END
  END r_o[198]
  PIN r_o[199]
    DIRECTION OUTPUT ;
    USE SIGNAL ;
    PORT
      LAYER M3 ;
        RECT  16.344 0 16.362 0.038 ;
    END
  END r_o[199]
  PIN r_o[19]
    DIRECTION OUTPUT ;
    USE SIGNAL ;
    PORT
      LAYER M3 ;
        RECT  3.528 0 3.546 0.038 ;
    END
  END r_o[19]
  PIN r_o[1]
    DIRECTION OUTPUT ;
    USE SIGNAL ;
    PORT
      LAYER M3 ;
        RECT  2.232 0 2.25 0.038 ;
    END
  END r_o[1]
  PIN r_o[200]
    DIRECTION OUTPUT ;
    USE SIGNAL ;
    PORT
      LAYER M5 ;
        RECT  16.944 0 16.968 0.192 ;
    END
  END r_o[200]
  PIN r_o[201]
    DIRECTION OUTPUT ;
    USE SIGNAL ;
    PORT
      LAYER M3 ;
        RECT  16.992 0 17.01 0.038 ;
    END
  END r_o[201]
  PIN r_o[202]
    DIRECTION OUTPUT ;
    USE SIGNAL ;
    PORT
      LAYER M5 ;
        RECT  17.04 0 17.064 0.192 ;
    END
  END r_o[202]
  PIN r_o[203]
    DIRECTION OUTPUT ;
    USE SIGNAL ;
    PORT
      LAYER M3 ;
        RECT  17.064 0 17.082 0.038 ;
    END
  END r_o[203]
  PIN r_o[204]
    DIRECTION OUTPUT ;
    USE SIGNAL ;
    PORT
      LAYER M5 ;
        RECT  17.136 0 17.16 0.192 ;
    END
  END r_o[204]
  PIN r_o[205]
    DIRECTION OUTPUT ;
    USE SIGNAL ;
    PORT
      LAYER M3 ;
        RECT  17.136 0 17.154 0.038 ;
    END
  END r_o[205]
  PIN r_o[206]
    DIRECTION OUTPUT ;
    USE SIGNAL ;
    PORT
      LAYER M5 ;
        RECT  17.232 0 17.256 0.192 ;
    END
  END r_o[206]
  PIN r_o[207]
    DIRECTION OUTPUT ;
    USE SIGNAL ;
    PORT
      LAYER M3 ;
        RECT  17.208 0 17.226 0.038 ;
    END
  END r_o[207]
  PIN r_o[208]
    DIRECTION OUTPUT ;
    USE SIGNAL ;
    PORT
      LAYER M5 ;
        RECT  17.328 0 17.352 0.192 ;
    END
  END r_o[208]
  PIN r_o[209]
    DIRECTION OUTPUT ;
    USE SIGNAL ;
    PORT
      LAYER M3 ;
        RECT  17.28 0 17.298 0.038 ;
    END
  END r_o[209]
  PIN r_o[20]
    DIRECTION OUTPUT ;
    USE SIGNAL ;
    PORT
      LAYER M5 ;
        RECT  3.6 0 3.624 0.192 ;
    END
  END r_o[20]
  PIN r_o[210]
    DIRECTION OUTPUT ;
    USE SIGNAL ;
    PORT
      LAYER M5 ;
        RECT  17.424 0 17.448 0.192 ;
    END
  END r_o[210]
  PIN r_o[211]
    DIRECTION OUTPUT ;
    USE SIGNAL ;
    PORT
      LAYER M3 ;
        RECT  17.352 0 17.37 0.038 ;
    END
  END r_o[211]
  PIN r_o[212]
    DIRECTION OUTPUT ;
    USE SIGNAL ;
    PORT
      LAYER M5 ;
        RECT  17.52 0 17.544 0.192 ;
    END
  END r_o[212]
  PIN r_o[213]
    DIRECTION OUTPUT ;
    USE SIGNAL ;
    PORT
      LAYER M3 ;
        RECT  17.424 0 17.442 0.038 ;
    END
  END r_o[213]
  PIN r_o[214]
    DIRECTION OUTPUT ;
    USE SIGNAL ;
    PORT
      LAYER M5 ;
        RECT  17.616 0 17.64 0.192 ;
    END
  END r_o[214]
  PIN r_o[215]
    DIRECTION OUTPUT ;
    USE SIGNAL ;
    PORT
      LAYER M3 ;
        RECT  17.496 0 17.514 0.038 ;
    END
  END r_o[215]
  PIN r_o[216]
    DIRECTION OUTPUT ;
    USE SIGNAL ;
    PORT
      LAYER M5 ;
        RECT  17.712 0 17.736 0.192 ;
    END
  END r_o[216]
  PIN r_o[217]
    DIRECTION OUTPUT ;
    USE SIGNAL ;
    PORT
      LAYER M3 ;
        RECT  17.64 0 17.658 0.038 ;
    END
  END r_o[217]
  PIN r_o[218]
    DIRECTION OUTPUT ;
    USE SIGNAL ;
    PORT
      LAYER M5 ;
        RECT  17.808 0 17.832 0.192 ;
    END
  END r_o[218]
  PIN r_o[219]
    DIRECTION OUTPUT ;
    USE SIGNAL ;
    PORT
      LAYER M3 ;
        RECT  17.784 0 17.802 0.038 ;
    END
  END r_o[219]
  PIN r_o[21]
    DIRECTION OUTPUT ;
    USE SIGNAL ;
    PORT
      LAYER M3 ;
        RECT  3.672 0 3.69 0.038 ;
    END
  END r_o[21]
  PIN r_o[220]
    DIRECTION OUTPUT ;
    USE SIGNAL ;
    PORT
      LAYER M5 ;
        RECT  17.904 0 17.928 0.192 ;
    END
  END r_o[220]
  PIN r_o[221]
    DIRECTION OUTPUT ;
    USE SIGNAL ;
    PORT
      LAYER M3 ;
        RECT  17.928 0 17.946 0.038 ;
    END
  END r_o[221]
  PIN r_o[222]
    DIRECTION OUTPUT ;
    USE SIGNAL ;
    PORT
      LAYER M5 ;
        RECT  18 0 18.024 0.192 ;
    END
  END r_o[222]
  PIN r_o[223]
    DIRECTION OUTPUT ;
    USE SIGNAL ;
    PORT
      LAYER M3 ;
        RECT  18.072 0 18.09 0.038 ;
    END
  END r_o[223]
  PIN r_o[224]
    DIRECTION OUTPUT ;
    USE SIGNAL ;
    PORT
      LAYER M5 ;
        RECT  18.096 0 18.12 0.192 ;
    END
  END r_o[224]
  PIN r_o[225]
    DIRECTION OUTPUT ;
    USE SIGNAL ;
    PORT
      LAYER M3 ;
        RECT  18.216 0 18.234 0.038 ;
    END
  END r_o[225]
  PIN r_o[226]
    DIRECTION OUTPUT ;
    USE SIGNAL ;
    PORT
      LAYER M5 ;
        RECT  18.288 0 18.312 0.192 ;
    END
  END r_o[226]
  PIN r_o[227]
    DIRECTION OUTPUT ;
    USE SIGNAL ;
    PORT
      LAYER M3 ;
        RECT  18.36 0 18.378 0.038 ;
    END
  END r_o[227]
  PIN r_o[228]
    DIRECTION OUTPUT ;
    USE SIGNAL ;
    PORT
      LAYER M5 ;
        RECT  18.384 0 18.408 0.192 ;
    END
  END r_o[228]
  PIN r_o[229]
    DIRECTION OUTPUT ;
    USE SIGNAL ;
    PORT
      LAYER M3 ;
        RECT  18.504 0 18.522 0.038 ;
    END
  END r_o[229]
  PIN r_o[22]
    DIRECTION OUTPUT ;
    USE SIGNAL ;
    PORT
      LAYER M5 ;
        RECT  3.792 0 3.816 0.192 ;
    END
  END r_o[22]
  PIN r_o[230]
    DIRECTION OUTPUT ;
    USE SIGNAL ;
    PORT
      LAYER M5 ;
        RECT  18.576 0 18.6 0.192 ;
    END
  END r_o[230]
  PIN r_o[231]
    DIRECTION OUTPUT ;
    USE SIGNAL ;
    PORT
      LAYER M3 ;
        RECT  18.648 0 18.666 0.038 ;
    END
  END r_o[231]
  PIN r_o[232]
    DIRECTION OUTPUT ;
    USE SIGNAL ;
    PORT
      LAYER M5 ;
        RECT  18.672 0 18.696 0.192 ;
    END
  END r_o[232]
  PIN r_o[233]
    DIRECTION OUTPUT ;
    USE SIGNAL ;
    PORT
      LAYER M3 ;
        RECT  18.792 0 18.81 0.038 ;
    END
  END r_o[233]
  PIN r_o[234]
    DIRECTION OUTPUT ;
    USE SIGNAL ;
    PORT
      LAYER M5 ;
        RECT  18.864 0 18.888 0.192 ;
    END
  END r_o[234]
  PIN r_o[235]
    DIRECTION OUTPUT ;
    USE SIGNAL ;
    PORT
      LAYER M3 ;
        RECT  18.936 0 18.954 0.038 ;
    END
  END r_o[235]
  PIN r_o[236]
    DIRECTION OUTPUT ;
    USE SIGNAL ;
    PORT
      LAYER M5 ;
        RECT  18.96 0 18.984 0.192 ;
    END
  END r_o[236]
  PIN r_o[237]
    DIRECTION OUTPUT ;
    USE SIGNAL ;
    PORT
      LAYER M3 ;
        RECT  19.08 0 19.098 0.038 ;
    END
  END r_o[237]
  PIN r_o[238]
    DIRECTION OUTPUT ;
    USE SIGNAL ;
    PORT
      LAYER M5 ;
        RECT  19.152 0 19.176 0.192 ;
    END
  END r_o[238]
  PIN r_o[239]
    DIRECTION OUTPUT ;
    USE SIGNAL ;
    PORT
      LAYER M3 ;
        RECT  19.224 0 19.242 0.038 ;
    END
  END r_o[239]
  PIN r_o[23]
    DIRECTION OUTPUT ;
    USE SIGNAL ;
    PORT
      LAYER M3 ;
        RECT  3.816 0 3.834 0.038 ;
    END
  END r_o[23]
  PIN r_o[240]
    DIRECTION OUTPUT ;
    USE SIGNAL ;
    PORT
      LAYER M5 ;
        RECT  19.248 0 19.272 0.192 ;
    END
  END r_o[240]
  PIN r_o[241]
    DIRECTION OUTPUT ;
    USE SIGNAL ;
    PORT
      LAYER M3 ;
        RECT  19.368 0 19.386 0.038 ;
    END
  END r_o[241]
  PIN r_o[242]
    DIRECTION OUTPUT ;
    USE SIGNAL ;
    PORT
      LAYER M5 ;
        RECT  19.44 0 19.464 0.192 ;
    END
  END r_o[242]
  PIN r_o[243]
    DIRECTION OUTPUT ;
    USE SIGNAL ;
    PORT
      LAYER M3 ;
        RECT  19.512 0 19.53 0.038 ;
    END
  END r_o[243]
  PIN r_o[244]
    DIRECTION OUTPUT ;
    USE SIGNAL ;
    PORT
      LAYER M5 ;
        RECT  19.536 0 19.56 0.192 ;
    END
  END r_o[244]
  PIN r_o[245]
    DIRECTION OUTPUT ;
    USE SIGNAL ;
    PORT
      LAYER M3 ;
        RECT  19.656 0 19.674 0.038 ;
    END
  END r_o[245]
  PIN r_o[246]
    DIRECTION OUTPUT ;
    USE SIGNAL ;
    PORT
      LAYER M5 ;
        RECT  19.728 0 19.752 0.192 ;
    END
  END r_o[246]
  PIN r_o[247]
    DIRECTION OUTPUT ;
    USE SIGNAL ;
    PORT
      LAYER M3 ;
        RECT  19.8 0 19.818 0.038 ;
    END
  END r_o[247]
  PIN r_o[248]
    DIRECTION OUTPUT ;
    USE SIGNAL ;
    PORT
      LAYER M5 ;
        RECT  19.824 0 19.848 0.192 ;
    END
  END r_o[248]
  PIN r_o[249]
    DIRECTION OUTPUT ;
    USE SIGNAL ;
    PORT
      LAYER M3 ;
        RECT  19.944 0 19.962 0.038 ;
    END
  END r_o[249]
  PIN r_o[24]
    DIRECTION OUTPUT ;
    USE SIGNAL ;
    PORT
      LAYER M5 ;
        RECT  3.888 0 3.912 0.192 ;
    END
  END r_o[24]
  PIN r_o[250]
    DIRECTION OUTPUT ;
    USE SIGNAL ;
    PORT
      LAYER M5 ;
        RECT  20.016 0 20.04 0.192 ;
    END
  END r_o[250]
  PIN r_o[251]
    DIRECTION OUTPUT ;
    USE SIGNAL ;
    PORT
      LAYER M3 ;
        RECT  20.088 0 20.106 0.038 ;
    END
  END r_o[251]
  PIN r_o[252]
    DIRECTION OUTPUT ;
    USE SIGNAL ;
    PORT
      LAYER M5 ;
        RECT  20.112 0 20.136 0.192 ;
    END
  END r_o[252]
  PIN r_o[253]
    DIRECTION OUTPUT ;
    USE SIGNAL ;
    PORT
      LAYER M3 ;
        RECT  20.232 0 20.25 0.038 ;
    END
  END r_o[253]
  PIN r_o[254]
    DIRECTION OUTPUT ;
    USE SIGNAL ;
    PORT
      LAYER M5 ;
        RECT  20.304 0 20.328 0.192 ;
    END
  END r_o[254]
  PIN r_o[255]
    DIRECTION OUTPUT ;
    USE SIGNAL ;
    PORT
      LAYER M3 ;
        RECT  20.376 0 20.394 0.038 ;
    END
  END r_o[255]
  PIN r_o[256]
    DIRECTION OUTPUT ;
    USE SIGNAL ;
    PORT
      LAYER M5 ;
        RECT  20.4 0 20.424 0.192 ;
    END
  END r_o[256]
  PIN r_o[257]
    DIRECTION OUTPUT ;
    USE SIGNAL ;
    PORT
      LAYER M3 ;
        RECT  20.52 0 20.538 0.038 ;
    END
  END r_o[257]
  PIN r_o[258]
    DIRECTION OUTPUT ;
    USE SIGNAL ;
    PORT
      LAYER M5 ;
        RECT  20.592 0 20.616 0.192 ;
    END
  END r_o[258]
  PIN r_o[259]
    DIRECTION OUTPUT ;
    USE SIGNAL ;
    PORT
      LAYER M3 ;
        RECT  20.664 0 20.682 0.038 ;
    END
  END r_o[259]
  PIN r_o[25]
    DIRECTION OUTPUT ;
    USE SIGNAL ;
    PORT
      LAYER M3 ;
        RECT  3.96 0 3.978 0.038 ;
    END
  END r_o[25]
  PIN r_o[260]
    DIRECTION OUTPUT ;
    USE SIGNAL ;
    PORT
      LAYER M5 ;
        RECT  20.688 0 20.712 0.192 ;
    END
  END r_o[260]
  PIN r_o[261]
    DIRECTION OUTPUT ;
    USE SIGNAL ;
    PORT
      LAYER M3 ;
        RECT  20.808 0 20.826 0.038 ;
    END
  END r_o[261]
  PIN r_o[262]
    DIRECTION OUTPUT ;
    USE SIGNAL ;
    PORT
      LAYER M5 ;
        RECT  20.88 0 20.904 0.192 ;
    END
  END r_o[262]
  PIN r_o[263]
    DIRECTION OUTPUT ;
    USE SIGNAL ;
    PORT
      LAYER M3 ;
        RECT  20.88 0 20.898 0.038 ;
    END
  END r_o[263]
  PIN r_o[264]
    DIRECTION OUTPUT ;
    USE SIGNAL ;
    PORT
      LAYER M5 ;
        RECT  20.976 0 21 0.192 ;
    END
  END r_o[264]
  PIN r_o[265]
    DIRECTION OUTPUT ;
    USE SIGNAL ;
    PORT
      LAYER M3 ;
        RECT  21.024 0 21.042 0.038 ;
    END
  END r_o[265]
  PIN r_o[266]
    DIRECTION OUTPUT ;
    USE SIGNAL ;
    PORT
      LAYER M5 ;
        RECT  21.168 0 21.192 0.192 ;
    END
  END r_o[266]
  PIN r_o[267]
    DIRECTION OUTPUT ;
    USE SIGNAL ;
    PORT
      LAYER M3 ;
        RECT  21.168 0 21.186 0.038 ;
    END
  END r_o[267]
  PIN r_o[268]
    DIRECTION OUTPUT ;
    USE SIGNAL ;
    PORT
      LAYER M5 ;
        RECT  21.264 0 21.288 0.192 ;
    END
  END r_o[268]
  PIN r_o[269]
    DIRECTION OUTPUT ;
    USE SIGNAL ;
    PORT
      LAYER M3 ;
        RECT  21.312 0 21.33 0.038 ;
    END
  END r_o[269]
  PIN r_o[26]
    DIRECTION OUTPUT ;
    USE SIGNAL ;
    PORT
      LAYER M5 ;
        RECT  4.08 0 4.104 0.192 ;
    END
  END r_o[26]
  PIN r_o[270]
    DIRECTION OUTPUT ;
    USE SIGNAL ;
    PORT
      LAYER M5 ;
        RECT  21.456 0 21.48 0.192 ;
    END
  END r_o[270]
  PIN r_o[271]
    DIRECTION OUTPUT ;
    USE SIGNAL ;
    PORT
      LAYER M3 ;
        RECT  21.456 0 21.474 0.038 ;
    END
  END r_o[271]
  PIN r_o[272]
    DIRECTION OUTPUT ;
    USE SIGNAL ;
    PORT
      LAYER M5 ;
        RECT  21.552 0 21.576 0.192 ;
    END
  END r_o[272]
  PIN r_o[273]
    DIRECTION OUTPUT ;
    USE SIGNAL ;
    PORT
      LAYER M3 ;
        RECT  21.6 0 21.618 0.038 ;
    END
  END r_o[273]
  PIN r_o[274]
    DIRECTION OUTPUT ;
    USE SIGNAL ;
    PORT
      LAYER M5 ;
        RECT  21.648 0 21.672 0.192 ;
    END
  END r_o[274]
  PIN r_o[275]
    DIRECTION OUTPUT ;
    USE SIGNAL ;
    PORT
      LAYER M3 ;
        RECT  21.744 0 21.762 0.038 ;
    END
  END r_o[275]
  PIN r_o[276]
    DIRECTION OUTPUT ;
    USE SIGNAL ;
    PORT
      LAYER M5 ;
        RECT  21.744 0 21.768 0.192 ;
    END
  END r_o[276]
  PIN r_o[277]
    DIRECTION OUTPUT ;
    USE SIGNAL ;
    PORT
      LAYER M3 ;
        RECT  22.392 0 22.41 0.038 ;
    END
  END r_o[277]
  PIN r_o[278]
    DIRECTION OUTPUT ;
    USE SIGNAL ;
    PORT
      LAYER M5 ;
        RECT  22.416 0 22.44 0.192 ;
    END
  END r_o[278]
  PIN r_o[279]
    DIRECTION OUTPUT ;
    USE SIGNAL ;
    PORT
      LAYER M3 ;
        RECT  22.464 0 22.482 0.038 ;
    END
  END r_o[279]
  PIN r_o[27]
    DIRECTION OUTPUT ;
    USE SIGNAL ;
    PORT
      LAYER M3 ;
        RECT  4.104 0 4.122 0.038 ;
    END
  END r_o[27]
  PIN r_o[280]
    DIRECTION OUTPUT ;
    USE SIGNAL ;
    PORT
      LAYER M5 ;
        RECT  22.512 0 22.536 0.192 ;
    END
  END r_o[280]
  PIN r_o[281]
    DIRECTION OUTPUT ;
    USE SIGNAL ;
    PORT
      LAYER M3 ;
        RECT  22.536 0 22.554 0.038 ;
    END
  END r_o[281]
  PIN r_o[282]
    DIRECTION OUTPUT ;
    USE SIGNAL ;
    PORT
      LAYER M5 ;
        RECT  22.608 0 22.632 0.192 ;
    END
  END r_o[282]
  PIN r_o[283]
    DIRECTION OUTPUT ;
    USE SIGNAL ;
    PORT
      LAYER M3 ;
        RECT  22.608 0 22.626 0.038 ;
    END
  END r_o[283]
  PIN r_o[284]
    DIRECTION OUTPUT ;
    USE SIGNAL ;
    PORT
      LAYER M5 ;
        RECT  22.704 0 22.728 0.192 ;
    END
  END r_o[284]
  PIN r_o[285]
    DIRECTION OUTPUT ;
    USE SIGNAL ;
    PORT
      LAYER M3 ;
        RECT  22.68 0 22.698 0.038 ;
    END
  END r_o[285]
  PIN r_o[286]
    DIRECTION OUTPUT ;
    USE SIGNAL ;
    PORT
      LAYER M5 ;
        RECT  22.8 0 22.824 0.192 ;
    END
  END r_o[286]
  PIN r_o[287]
    DIRECTION OUTPUT ;
    USE SIGNAL ;
    PORT
      LAYER M3 ;
        RECT  22.752 0 22.77 0.038 ;
    END
  END r_o[287]
  PIN r_o[288]
    DIRECTION OUTPUT ;
    USE SIGNAL ;
    PORT
      LAYER M5 ;
        RECT  22.896 0 22.92 0.192 ;
    END
  END r_o[288]
  PIN r_o[289]
    DIRECTION OUTPUT ;
    USE SIGNAL ;
    PORT
      LAYER M3 ;
        RECT  22.824 0 22.842 0.038 ;
    END
  END r_o[289]
  PIN r_o[28]
    DIRECTION OUTPUT ;
    USE SIGNAL ;
    PORT
      LAYER M5 ;
        RECT  4.176 0 4.2 0.192 ;
    END
  END r_o[28]
  PIN r_o[290]
    DIRECTION OUTPUT ;
    USE SIGNAL ;
    PORT
      LAYER M5 ;
        RECT  22.992 0 23.016 0.192 ;
    END
  END r_o[290]
  PIN r_o[291]
    DIRECTION OUTPUT ;
    USE SIGNAL ;
    PORT
      LAYER M3 ;
        RECT  22.896 0 22.914 0.038 ;
    END
  END r_o[291]
  PIN r_o[292]
    DIRECTION OUTPUT ;
    USE SIGNAL ;
    PORT
      LAYER M5 ;
        RECT  23.088 0 23.112 0.192 ;
    END
  END r_o[292]
  PIN r_o[293]
    DIRECTION OUTPUT ;
    USE SIGNAL ;
    PORT
      LAYER M3 ;
        RECT  23.04 0 23.058 0.038 ;
    END
  END r_o[293]
  PIN r_o[294]
    DIRECTION OUTPUT ;
    USE SIGNAL ;
    PORT
      LAYER M5 ;
        RECT  23.184 0 23.208 0.192 ;
    END
  END r_o[294]
  PIN r_o[295]
    DIRECTION OUTPUT ;
    USE SIGNAL ;
    PORT
      LAYER M3 ;
        RECT  23.184 0 23.202 0.038 ;
    END
  END r_o[295]
  PIN r_o[296]
    DIRECTION OUTPUT ;
    USE SIGNAL ;
    PORT
      LAYER M5 ;
        RECT  23.28 0 23.304 0.192 ;
    END
  END r_o[296]
  PIN r_o[297]
    DIRECTION OUTPUT ;
    USE SIGNAL ;
    PORT
      LAYER M3 ;
        RECT  23.328 0 23.346 0.038 ;
    END
  END r_o[297]
  PIN r_o[298]
    DIRECTION OUTPUT ;
    USE SIGNAL ;
    PORT
      LAYER M5 ;
        RECT  23.376 0 23.4 0.192 ;
    END
  END r_o[298]
  PIN r_o[299]
    DIRECTION OUTPUT ;
    USE SIGNAL ;
    PORT
      LAYER M3 ;
        RECT  23.472 0 23.49 0.038 ;
    END
  END r_o[299]
  PIN r_o[29]
    DIRECTION OUTPUT ;
    USE SIGNAL ;
    PORT
      LAYER M3 ;
        RECT  4.248 0 4.266 0.038 ;
    END
  END r_o[29]
  PIN r_o[2]
    DIRECTION OUTPUT ;
    USE SIGNAL ;
    PORT
      LAYER M5 ;
        RECT  2.352 0 2.376 0.192 ;
    END
  END r_o[2]
  PIN r_o[300]
    DIRECTION OUTPUT ;
    USE SIGNAL ;
    PORT
      LAYER M5 ;
        RECT  23.568 0 23.592 0.192 ;
    END
  END r_o[300]
  PIN r_o[301]
    DIRECTION OUTPUT ;
    USE SIGNAL ;
    PORT
      LAYER M3 ;
        RECT  23.616 0 23.634 0.038 ;
    END
  END r_o[301]
  PIN r_o[302]
    DIRECTION OUTPUT ;
    USE SIGNAL ;
    PORT
      LAYER M5 ;
        RECT  23.664 0 23.688 0.192 ;
    END
  END r_o[302]
  PIN r_o[303]
    DIRECTION OUTPUT ;
    USE SIGNAL ;
    PORT
      LAYER M3 ;
        RECT  23.76 0 23.778 0.038 ;
    END
  END r_o[303]
  PIN r_o[304]
    DIRECTION OUTPUT ;
    USE SIGNAL ;
    PORT
      LAYER M5 ;
        RECT  23.856 0 23.88 0.192 ;
    END
  END r_o[304]
  PIN r_o[305]
    DIRECTION OUTPUT ;
    USE SIGNAL ;
    PORT
      LAYER M3 ;
        RECT  23.904 0 23.922 0.038 ;
    END
  END r_o[305]
  PIN r_o[306]
    DIRECTION OUTPUT ;
    USE SIGNAL ;
    PORT
      LAYER M5 ;
        RECT  23.952 0 23.976 0.192 ;
    END
  END r_o[306]
  PIN r_o[307]
    DIRECTION OUTPUT ;
    USE SIGNAL ;
    PORT
      LAYER M3 ;
        RECT  24.048 0 24.066 0.038 ;
    END
  END r_o[307]
  PIN r_o[308]
    DIRECTION OUTPUT ;
    USE SIGNAL ;
    PORT
      LAYER M5 ;
        RECT  24.144 0 24.168 0.192 ;
    END
  END r_o[308]
  PIN r_o[309]
    DIRECTION OUTPUT ;
    USE SIGNAL ;
    PORT
      LAYER M3 ;
        RECT  24.192 0 24.21 0.038 ;
    END
  END r_o[309]
  PIN r_o[30]
    DIRECTION OUTPUT ;
    USE SIGNAL ;
    PORT
      LAYER M5 ;
        RECT  4.272 0 4.296 0.192 ;
    END
  END r_o[30]
  PIN r_o[310]
    DIRECTION OUTPUT ;
    USE SIGNAL ;
    PORT
      LAYER M5 ;
        RECT  24.24 0 24.264 0.192 ;
    END
  END r_o[310]
  PIN r_o[311]
    DIRECTION OUTPUT ;
    USE SIGNAL ;
    PORT
      LAYER M3 ;
        RECT  24.336 0 24.354 0.038 ;
    END
  END r_o[311]
  PIN r_o[312]
    DIRECTION OUTPUT ;
    USE SIGNAL ;
    PORT
      LAYER M5 ;
        RECT  24.432 0 24.456 0.192 ;
    END
  END r_o[312]
  PIN r_o[313]
    DIRECTION OUTPUT ;
    USE SIGNAL ;
    PORT
      LAYER M3 ;
        RECT  24.48 0 24.498 0.038 ;
    END
  END r_o[313]
  PIN r_o[314]
    DIRECTION OUTPUT ;
    USE SIGNAL ;
    PORT
      LAYER M5 ;
        RECT  24.528 0 24.552 0.192 ;
    END
  END r_o[314]
  PIN r_o[315]
    DIRECTION OUTPUT ;
    USE SIGNAL ;
    PORT
      LAYER M3 ;
        RECT  24.624 0 24.642 0.038 ;
    END
  END r_o[315]
  PIN r_o[316]
    DIRECTION OUTPUT ;
    USE SIGNAL ;
    PORT
      LAYER M5 ;
        RECT  24.72 0 24.744 0.192 ;
    END
  END r_o[316]
  PIN r_o[317]
    DIRECTION OUTPUT ;
    USE SIGNAL ;
    PORT
      LAYER M3 ;
        RECT  24.768 0 24.786 0.038 ;
    END
  END r_o[317]
  PIN r_o[318]
    DIRECTION OUTPUT ;
    USE SIGNAL ;
    PORT
      LAYER M5 ;
        RECT  24.816 0 24.84 0.192 ;
    END
  END r_o[318]
  PIN r_o[319]
    DIRECTION OUTPUT ;
    USE SIGNAL ;
    PORT
      LAYER M3 ;
        RECT  24.912 0 24.93 0.038 ;
    END
  END r_o[319]
  PIN r_o[31]
    DIRECTION OUTPUT ;
    USE SIGNAL ;
    PORT
      LAYER M3 ;
        RECT  4.392 0 4.41 0.038 ;
    END
  END r_o[31]
  PIN r_o[320]
    DIRECTION OUTPUT ;
    USE SIGNAL ;
    PORT
      LAYER M5 ;
        RECT  25.008 0 25.032 0.192 ;
    END
  END r_o[320]
  PIN r_o[321]
    DIRECTION OUTPUT ;
    USE SIGNAL ;
    PORT
      LAYER M3 ;
        RECT  25.056 0 25.074 0.038 ;
    END
  END r_o[321]
  PIN r_o[322]
    DIRECTION OUTPUT ;
    USE SIGNAL ;
    PORT
      LAYER M5 ;
        RECT  25.104 0 25.128 0.192 ;
    END
  END r_o[322]
  PIN r_o[323]
    DIRECTION OUTPUT ;
    USE SIGNAL ;
    PORT
      LAYER M3 ;
        RECT  25.2 0 25.218 0.038 ;
    END
  END r_o[323]
  PIN r_o[324]
    DIRECTION OUTPUT ;
    USE SIGNAL ;
    PORT
      LAYER M5 ;
        RECT  25.296 0 25.32 0.192 ;
    END
  END r_o[324]
  PIN r_o[325]
    DIRECTION OUTPUT ;
    USE SIGNAL ;
    PORT
      LAYER M3 ;
        RECT  25.344 0 25.362 0.038 ;
    END
  END r_o[325]
  PIN r_o[326]
    DIRECTION OUTPUT ;
    USE SIGNAL ;
    PORT
      LAYER M5 ;
        RECT  25.392 0 25.416 0.192 ;
    END
  END r_o[326]
  PIN r_o[327]
    DIRECTION OUTPUT ;
    USE SIGNAL ;
    PORT
      LAYER M3 ;
        RECT  25.488 0 25.506 0.038 ;
    END
  END r_o[327]
  PIN r_o[328]
    DIRECTION OUTPUT ;
    USE SIGNAL ;
    PORT
      LAYER M5 ;
        RECT  25.584 0 25.608 0.192 ;
    END
  END r_o[328]
  PIN r_o[329]
    DIRECTION OUTPUT ;
    USE SIGNAL ;
    PORT
      LAYER M3 ;
        RECT  25.632 0 25.65 0.038 ;
    END
  END r_o[329]
  PIN r_o[32]
    DIRECTION OUTPUT ;
    USE SIGNAL ;
    PORT
      LAYER M5 ;
        RECT  4.464 0 4.488 0.192 ;
    END
  END r_o[32]
  PIN r_o[330]
    DIRECTION OUTPUT ;
    USE SIGNAL ;
    PORT
      LAYER M5 ;
        RECT  25.68 0 25.704 0.192 ;
    END
  END r_o[330]
  PIN r_o[331]
    DIRECTION OUTPUT ;
    USE SIGNAL ;
    PORT
      LAYER M3 ;
        RECT  25.776 0 25.794 0.038 ;
    END
  END r_o[331]
  PIN r_o[332]
    DIRECTION OUTPUT ;
    USE SIGNAL ;
    PORT
      LAYER M5 ;
        RECT  25.872 0 25.896 0.192 ;
    END
  END r_o[332]
  PIN r_o[333]
    DIRECTION OUTPUT ;
    USE SIGNAL ;
    PORT
      LAYER M3 ;
        RECT  25.92 0 25.938 0.038 ;
    END
  END r_o[333]
  PIN r_o[334]
    DIRECTION OUTPUT ;
    USE SIGNAL ;
    PORT
      LAYER M5 ;
        RECT  25.968 0 25.992 0.192 ;
    END
  END r_o[334]
  PIN r_o[335]
    DIRECTION OUTPUT ;
    USE SIGNAL ;
    PORT
      LAYER M3 ;
        RECT  26.064 0 26.082 0.038 ;
    END
  END r_o[335]
  PIN r_o[336]
    DIRECTION OUTPUT ;
    USE SIGNAL ;
    PORT
      LAYER M5 ;
        RECT  26.064 0 26.088 0.192 ;
    END
  END r_o[336]
  PIN r_o[337]
    DIRECTION OUTPUT ;
    USE SIGNAL ;
    PORT
      LAYER M3 ;
        RECT  26.208 0 26.226 0.038 ;
    END
  END r_o[337]
  PIN r_o[338]
    DIRECTION OUTPUT ;
    USE SIGNAL ;
    PORT
      LAYER M5 ;
        RECT  26.256 0 26.28 0.192 ;
    END
  END r_o[338]
  PIN r_o[339]
    DIRECTION OUTPUT ;
    USE SIGNAL ;
    PORT
      LAYER M3 ;
        RECT  26.352 0 26.37 0.038 ;
    END
  END r_o[339]
  PIN r_o[33]
    DIRECTION OUTPUT ;
    USE SIGNAL ;
    PORT
      LAYER M3 ;
        RECT  4.536 0 4.554 0.038 ;
    END
  END r_o[33]
  PIN r_o[340]
    DIRECTION OUTPUT ;
    USE SIGNAL ;
    PORT
      LAYER M5 ;
        RECT  26.352 0 26.376 0.192 ;
    END
  END r_o[340]
  PIN r_o[341]
    DIRECTION OUTPUT ;
    USE SIGNAL ;
    PORT
      LAYER M3 ;
        RECT  26.496 0 26.514 0.038 ;
    END
  END r_o[341]
  PIN r_o[342]
    DIRECTION OUTPUT ;
    USE SIGNAL ;
    PORT
      LAYER M5 ;
        RECT  26.544 0 26.568 0.192 ;
    END
  END r_o[342]
  PIN r_o[343]
    DIRECTION OUTPUT ;
    USE SIGNAL ;
    PORT
      LAYER M3 ;
        RECT  26.64 0 26.658 0.038 ;
    END
  END r_o[343]
  PIN r_o[344]
    DIRECTION OUTPUT ;
    USE SIGNAL ;
    PORT
      LAYER M5 ;
        RECT  26.64 0 26.664 0.192 ;
    END
  END r_o[344]
  PIN r_o[345]
    DIRECTION OUTPUT ;
    USE SIGNAL ;
    PORT
      LAYER M3 ;
        RECT  26.784 0 26.802 0.038 ;
    END
  END r_o[345]
  PIN r_o[346]
    DIRECTION OUTPUT ;
    USE SIGNAL ;
    PORT
      LAYER M5 ;
        RECT  26.832 0 26.856 0.192 ;
    END
  END r_o[346]
  PIN r_o[347]
    DIRECTION OUTPUT ;
    USE SIGNAL ;
    PORT
      LAYER M3 ;
        RECT  26.928 0 26.946 0.038 ;
    END
  END r_o[347]
  PIN r_o[348]
    DIRECTION OUTPUT ;
    USE SIGNAL ;
    PORT
      LAYER M5 ;
        RECT  26.928 0 26.952 0.192 ;
    END
  END r_o[348]
  PIN r_o[349]
    DIRECTION OUTPUT ;
    USE SIGNAL ;
    PORT
      LAYER M3 ;
        RECT  27.072 0 27.09 0.038 ;
    END
  END r_o[349]
  PIN r_o[34]
    DIRECTION OUTPUT ;
    USE SIGNAL ;
    PORT
      LAYER M5 ;
        RECT  4.56 0 4.584 0.192 ;
    END
  END r_o[34]
  PIN r_o[350]
    DIRECTION OUTPUT ;
    USE SIGNAL ;
    PORT
      LAYER M5 ;
        RECT  27.12 0 27.144 0.192 ;
    END
  END r_o[350]
  PIN r_o[351]
    DIRECTION OUTPUT ;
    USE SIGNAL ;
    PORT
      LAYER M3 ;
        RECT  27.144 0 27.162 0.038 ;
    END
  END r_o[351]
  PIN r_o[352]
    DIRECTION OUTPUT ;
    USE SIGNAL ;
    PORT
      LAYER M5 ;
        RECT  27.744 0 27.768 0.192 ;
    END
  END r_o[352]
  PIN r_o[353]
    DIRECTION OUTPUT ;
    USE SIGNAL ;
    PORT
      LAYER M3 ;
        RECT  27.792 0 27.81 0.038 ;
    END
  END r_o[353]
  PIN r_o[354]
    DIRECTION OUTPUT ;
    USE SIGNAL ;
    PORT
      LAYER M5 ;
        RECT  27.84 0 27.864 0.192 ;
    END
  END r_o[354]
  PIN r_o[355]
    DIRECTION OUTPUT ;
    USE SIGNAL ;
    PORT
      LAYER M3 ;
        RECT  27.864 0 27.882 0.038 ;
    END
  END r_o[355]
  PIN r_o[356]
    DIRECTION OUTPUT ;
    USE SIGNAL ;
    PORT
      LAYER M5 ;
        RECT  27.936 0 27.96 0.192 ;
    END
  END r_o[356]
  PIN r_o[357]
    DIRECTION OUTPUT ;
    USE SIGNAL ;
    PORT
      LAYER M3 ;
        RECT  27.936 0 27.954 0.038 ;
    END
  END r_o[357]
  PIN r_o[358]
    DIRECTION OUTPUT ;
    USE SIGNAL ;
    PORT
      LAYER M5 ;
        RECT  28.032 0 28.056 0.192 ;
    END
  END r_o[358]
  PIN r_o[359]
    DIRECTION OUTPUT ;
    USE SIGNAL ;
    PORT
      LAYER M3 ;
        RECT  28.008 0 28.026 0.038 ;
    END
  END r_o[359]
  PIN r_o[35]
    DIRECTION OUTPUT ;
    USE SIGNAL ;
    PORT
      LAYER M3 ;
        RECT  4.68 0 4.698 0.038 ;
    END
  END r_o[35]
  PIN r_o[360]
    DIRECTION OUTPUT ;
    USE SIGNAL ;
    PORT
      LAYER M5 ;
        RECT  28.128 0 28.152 0.192 ;
    END
  END r_o[360]
  PIN r_o[361]
    DIRECTION OUTPUT ;
    USE SIGNAL ;
    PORT
      LAYER M3 ;
        RECT  28.08 0 28.098 0.038 ;
    END
  END r_o[361]
  PIN r_o[362]
    DIRECTION OUTPUT ;
    USE SIGNAL ;
    PORT
      LAYER M5 ;
        RECT  28.224 0 28.248 0.192 ;
    END
  END r_o[362]
  PIN r_o[363]
    DIRECTION OUTPUT ;
    USE SIGNAL ;
    PORT
      LAYER M3 ;
        RECT  28.152 0 28.17 0.038 ;
    END
  END r_o[363]
  PIN r_o[364]
    DIRECTION OUTPUT ;
    USE SIGNAL ;
    PORT
      LAYER M5 ;
        RECT  28.32 0 28.344 0.192 ;
    END
  END r_o[364]
  PIN r_o[365]
    DIRECTION OUTPUT ;
    USE SIGNAL ;
    PORT
      LAYER M3 ;
        RECT  28.224 0 28.242 0.038 ;
    END
  END r_o[365]
  PIN r_o[366]
    DIRECTION OUTPUT ;
    USE SIGNAL ;
    PORT
      LAYER M5 ;
        RECT  28.416 0 28.44 0.192 ;
    END
  END r_o[366]
  PIN r_o[367]
    DIRECTION OUTPUT ;
    USE SIGNAL ;
    PORT
      LAYER M3 ;
        RECT  28.296 0 28.314 0.038 ;
    END
  END r_o[367]
  PIN r_o[368]
    DIRECTION OUTPUT ;
    USE SIGNAL ;
    PORT
      LAYER M5 ;
        RECT  28.512 0 28.536 0.192 ;
    END
  END r_o[368]
  PIN r_o[369]
    DIRECTION OUTPUT ;
    USE SIGNAL ;
    PORT
      LAYER M3 ;
        RECT  28.44 0 28.458 0.038 ;
    END
  END r_o[369]
  PIN r_o[36]
    DIRECTION OUTPUT ;
    USE SIGNAL ;
    PORT
      LAYER M5 ;
        RECT  4.752 0 4.776 0.192 ;
    END
  END r_o[36]
  PIN r_o[370]
    DIRECTION OUTPUT ;
    USE SIGNAL ;
    PORT
      LAYER M5 ;
        RECT  28.608 0 28.632 0.192 ;
    END
  END r_o[370]
  PIN r_o[371]
    DIRECTION OUTPUT ;
    USE SIGNAL ;
    PORT
      LAYER M3 ;
        RECT  28.584 0 28.602 0.038 ;
    END
  END r_o[371]
  PIN r_o[372]
    DIRECTION OUTPUT ;
    USE SIGNAL ;
    PORT
      LAYER M5 ;
        RECT  28.704 0 28.728 0.192 ;
    END
  END r_o[372]
  PIN r_o[373]
    DIRECTION OUTPUT ;
    USE SIGNAL ;
    PORT
      LAYER M3 ;
        RECT  28.728 0 28.746 0.038 ;
    END
  END r_o[373]
  PIN r_o[374]
    DIRECTION OUTPUT ;
    USE SIGNAL ;
    PORT
      LAYER M5 ;
        RECT  28.8 0 28.824 0.192 ;
    END
  END r_o[374]
  PIN r_o[375]
    DIRECTION OUTPUT ;
    USE SIGNAL ;
    PORT
      LAYER M3 ;
        RECT  28.872 0 28.89 0.038 ;
    END
  END r_o[375]
  PIN r_o[376]
    DIRECTION OUTPUT ;
    USE SIGNAL ;
    PORT
      LAYER M5 ;
        RECT  28.992 0 29.016 0.192 ;
    END
  END r_o[376]
  PIN r_o[377]
    DIRECTION OUTPUT ;
    USE SIGNAL ;
    PORT
      LAYER M3 ;
        RECT  29.016 0 29.034 0.038 ;
    END
  END r_o[377]
  PIN r_o[378]
    DIRECTION OUTPUT ;
    USE SIGNAL ;
    PORT
      LAYER M5 ;
        RECT  29.088 0 29.112 0.192 ;
    END
  END r_o[378]
  PIN r_o[379]
    DIRECTION OUTPUT ;
    USE SIGNAL ;
    PORT
      LAYER M3 ;
        RECT  29.16 0 29.178 0.038 ;
    END
  END r_o[379]
  PIN r_o[37]
    DIRECTION OUTPUT ;
    USE SIGNAL ;
    PORT
      LAYER M3 ;
        RECT  4.824 0 4.842 0.038 ;
    END
  END r_o[37]
  PIN r_o[380]
    DIRECTION OUTPUT ;
    USE SIGNAL ;
    PORT
      LAYER M5 ;
        RECT  29.28 0 29.304 0.192 ;
    END
  END r_o[380]
  PIN r_o[381]
    DIRECTION OUTPUT ;
    USE SIGNAL ;
    PORT
      LAYER M3 ;
        RECT  29.304 0 29.322 0.038 ;
    END
  END r_o[381]
  PIN r_o[382]
    DIRECTION OUTPUT ;
    USE SIGNAL ;
    PORT
      LAYER M5 ;
        RECT  29.376 0 29.4 0.192 ;
    END
  END r_o[382]
  PIN r_o[383]
    DIRECTION OUTPUT ;
    USE SIGNAL ;
    PORT
      LAYER M3 ;
        RECT  29.448 0 29.466 0.038 ;
    END
  END r_o[383]
  PIN r_o[384]
    DIRECTION OUTPUT ;
    USE SIGNAL ;
    PORT
      LAYER M5 ;
        RECT  29.568 0 29.592 0.192 ;
    END
  END r_o[384]
  PIN r_o[385]
    DIRECTION OUTPUT ;
    USE SIGNAL ;
    PORT
      LAYER M3 ;
        RECT  29.592 0 29.61 0.038 ;
    END
  END r_o[385]
  PIN r_o[386]
    DIRECTION OUTPUT ;
    USE SIGNAL ;
    PORT
      LAYER M5 ;
        RECT  29.664 0 29.688 0.192 ;
    END
  END r_o[386]
  PIN r_o[387]
    DIRECTION OUTPUT ;
    USE SIGNAL ;
    PORT
      LAYER M3 ;
        RECT  29.736 0 29.754 0.038 ;
    END
  END r_o[387]
  PIN r_o[388]
    DIRECTION OUTPUT ;
    USE SIGNAL ;
    PORT
      LAYER M5 ;
        RECT  29.856 0 29.88 0.192 ;
    END
  END r_o[388]
  PIN r_o[389]
    DIRECTION OUTPUT ;
    USE SIGNAL ;
    PORT
      LAYER M3 ;
        RECT  29.88 0 29.898 0.038 ;
    END
  END r_o[389]
  PIN r_o[38]
    DIRECTION OUTPUT ;
    USE SIGNAL ;
    PORT
      LAYER M5 ;
        RECT  4.848 0 4.872 0.192 ;
    END
  END r_o[38]
  PIN r_o[390]
    DIRECTION OUTPUT ;
    USE SIGNAL ;
    PORT
      LAYER M5 ;
        RECT  29.952 0 29.976 0.192 ;
    END
  END r_o[390]
  PIN r_o[391]
    DIRECTION OUTPUT ;
    USE SIGNAL ;
    PORT
      LAYER M3 ;
        RECT  30.024 0 30.042 0.038 ;
    END
  END r_o[391]
  PIN r_o[392]
    DIRECTION OUTPUT ;
    USE SIGNAL ;
    PORT
      LAYER M5 ;
        RECT  30.144 0 30.168 0.192 ;
    END
  END r_o[392]
  PIN r_o[393]
    DIRECTION OUTPUT ;
    USE SIGNAL ;
    PORT
      LAYER M3 ;
        RECT  30.168 0 30.186 0.038 ;
    END
  END r_o[393]
  PIN r_o[394]
    DIRECTION OUTPUT ;
    USE SIGNAL ;
    PORT
      LAYER M5 ;
        RECT  30.24 0 30.264 0.192 ;
    END
  END r_o[394]
  PIN r_o[395]
    DIRECTION OUTPUT ;
    USE SIGNAL ;
    PORT
      LAYER M3 ;
        RECT  30.312 0 30.33 0.038 ;
    END
  END r_o[395]
  PIN r_o[396]
    DIRECTION OUTPUT ;
    USE SIGNAL ;
    PORT
      LAYER M5 ;
        RECT  30.336 0 30.36 0.192 ;
    END
  END r_o[396]
  PIN r_o[397]
    DIRECTION OUTPUT ;
    USE SIGNAL ;
    PORT
      LAYER M3 ;
        RECT  30.456 0 30.474 0.038 ;
    END
  END r_o[397]
  PIN r_o[398]
    DIRECTION OUTPUT ;
    USE SIGNAL ;
    PORT
      LAYER M5 ;
        RECT  30.528 0 30.552 0.192 ;
    END
  END r_o[398]
  PIN r_o[399]
    DIRECTION OUTPUT ;
    USE SIGNAL ;
    PORT
      LAYER M3 ;
        RECT  30.6 0 30.618 0.038 ;
    END
  END r_o[399]
  PIN r_o[39]
    DIRECTION OUTPUT ;
    USE SIGNAL ;
    PORT
      LAYER M3 ;
        RECT  4.968 0 4.986 0.038 ;
    END
  END r_o[39]
  PIN r_o[3]
    DIRECTION OUTPUT ;
    USE SIGNAL ;
    PORT
      LAYER M3 ;
        RECT  2.376 0 2.394 0.038 ;
    END
  END r_o[3]
  PIN r_o[400]
    DIRECTION OUTPUT ;
    USE SIGNAL ;
    PORT
      LAYER M5 ;
        RECT  30.624 0 30.648 0.192 ;
    END
  END r_o[400]
  PIN r_o[401]
    DIRECTION OUTPUT ;
    USE SIGNAL ;
    PORT
      LAYER M3 ;
        RECT  30.744 0 30.762 0.038 ;
    END
  END r_o[401]
  PIN r_o[402]
    DIRECTION OUTPUT ;
    USE SIGNAL ;
    PORT
      LAYER M5 ;
        RECT  30.816 0 30.84 0.192 ;
    END
  END r_o[402]
  PIN r_o[403]
    DIRECTION OUTPUT ;
    USE SIGNAL ;
    PORT
      LAYER M3 ;
        RECT  30.888 0 30.906 0.038 ;
    END
  END r_o[403]
  PIN r_o[404]
    DIRECTION OUTPUT ;
    USE SIGNAL ;
    PORT
      LAYER M5 ;
        RECT  30.912 0 30.936 0.192 ;
    END
  END r_o[404]
  PIN r_o[405]
    DIRECTION OUTPUT ;
    USE SIGNAL ;
    PORT
      LAYER M3 ;
        RECT  31.032 0 31.05 0.038 ;
    END
  END r_o[405]
  PIN r_o[406]
    DIRECTION OUTPUT ;
    USE SIGNAL ;
    PORT
      LAYER M5 ;
        RECT  31.104 0 31.128 0.192 ;
    END
  END r_o[406]
  PIN r_o[407]
    DIRECTION OUTPUT ;
    USE SIGNAL ;
    PORT
      LAYER M3 ;
        RECT  31.176 0 31.194 0.038 ;
    END
  END r_o[407]
  PIN r_o[408]
    DIRECTION OUTPUT ;
    USE SIGNAL ;
    PORT
      LAYER M5 ;
        RECT  31.2 0 31.224 0.192 ;
    END
  END r_o[408]
  PIN r_o[409]
    DIRECTION OUTPUT ;
    USE SIGNAL ;
    PORT
      LAYER M3 ;
        RECT  31.32 0 31.338 0.038 ;
    END
  END r_o[409]
  PIN r_o[40]
    DIRECTION OUTPUT ;
    USE SIGNAL ;
    PORT
      LAYER M5 ;
        RECT  5.04 0 5.064 0.192 ;
    END
  END r_o[40]
  PIN r_o[410]
    DIRECTION OUTPUT ;
    USE SIGNAL ;
    PORT
      LAYER M5 ;
        RECT  31.392 0 31.416 0.192 ;
    END
  END r_o[410]
  PIN r_o[411]
    DIRECTION OUTPUT ;
    USE SIGNAL ;
    PORT
      LAYER M3 ;
        RECT  31.464 0 31.482 0.038 ;
    END
  END r_o[411]
  PIN r_o[412]
    DIRECTION OUTPUT ;
    USE SIGNAL ;
    PORT
      LAYER M5 ;
        RECT  31.488 0 31.512 0.192 ;
    END
  END r_o[412]
  PIN r_o[413]
    DIRECTION OUTPUT ;
    USE SIGNAL ;
    PORT
      LAYER M3 ;
        RECT  31.608 0 31.626 0.038 ;
    END
  END r_o[413]
  PIN r_o[414]
    DIRECTION OUTPUT ;
    USE SIGNAL ;
    PORT
      LAYER M5 ;
        RECT  31.68 0 31.704 0.192 ;
    END
  END r_o[414]
  PIN r_o[415]
    DIRECTION OUTPUT ;
    USE SIGNAL ;
    PORT
      LAYER M3 ;
        RECT  31.752 0 31.77 0.038 ;
    END
  END r_o[415]
  PIN r_o[416]
    DIRECTION OUTPUT ;
    USE SIGNAL ;
    PORT
      LAYER M5 ;
        RECT  31.776 0 31.8 0.192 ;
    END
  END r_o[416]
  PIN r_o[417]
    DIRECTION OUTPUT ;
    USE SIGNAL ;
    PORT
      LAYER M3 ;
        RECT  31.896 0 31.914 0.038 ;
    END
  END r_o[417]
  PIN r_o[418]
    DIRECTION OUTPUT ;
    USE SIGNAL ;
    PORT
      LAYER M5 ;
        RECT  31.968 0 31.992 0.192 ;
    END
  END r_o[418]
  PIN r_o[419]
    DIRECTION OUTPUT ;
    USE SIGNAL ;
    PORT
      LAYER M3 ;
        RECT  32.04 0 32.058 0.038 ;
    END
  END r_o[419]
  PIN r_o[41]
    DIRECTION OUTPUT ;
    USE SIGNAL ;
    PORT
      LAYER M3 ;
        RECT  5.112 0 5.13 0.038 ;
    END
  END r_o[41]
  PIN r_o[420]
    DIRECTION OUTPUT ;
    USE SIGNAL ;
    PORT
      LAYER M5 ;
        RECT  32.064 0 32.088 0.192 ;
    END
  END r_o[420]
  PIN r_o[421]
    DIRECTION OUTPUT ;
    USE SIGNAL ;
    PORT
      LAYER M3 ;
        RECT  32.184 0 32.202 0.038 ;
    END
  END r_o[421]
  PIN r_o[422]
    DIRECTION OUTPUT ;
    USE SIGNAL ;
    PORT
      LAYER M5 ;
        RECT  32.256 0 32.28 0.192 ;
    END
  END r_o[422]
  PIN r_o[423]
    DIRECTION OUTPUT ;
    USE SIGNAL ;
    PORT
      LAYER M3 ;
        RECT  32.328 0 32.346 0.038 ;
    END
  END r_o[423]
  PIN r_o[424]
    DIRECTION OUTPUT ;
    USE SIGNAL ;
    PORT
      LAYER M5 ;
        RECT  32.352 0 32.376 0.192 ;
    END
  END r_o[424]
  PIN r_o[425]
    DIRECTION OUTPUT ;
    USE SIGNAL ;
    PORT
      LAYER M3 ;
        RECT  32.472 0 32.49 0.038 ;
    END
  END r_o[425]
  PIN r_o[426]
    DIRECTION OUTPUT ;
    USE SIGNAL ;
    PORT
      LAYER M5 ;
        RECT  32.544 0 32.568 0.192 ;
    END
  END r_o[426]
  PIN r_o[427]
    DIRECTION OUTPUT ;
    USE SIGNAL ;
    PORT
      LAYER M3 ;
        RECT  32.544 0 32.562 0.038 ;
    END
  END r_o[427]
  PIN r_o[428]
    DIRECTION OUTPUT ;
    USE SIGNAL ;
    PORT
      LAYER M5 ;
        RECT  33.216 0 33.24 0.192 ;
    END
  END r_o[428]
  PIN r_o[429]
    DIRECTION OUTPUT ;
    USE SIGNAL ;
    PORT
      LAYER M3 ;
        RECT  33.192 0 33.21 0.038 ;
    END
  END r_o[429]
  PIN r_o[42]
    DIRECTION OUTPUT ;
    USE SIGNAL ;
    PORT
      LAYER M5 ;
        RECT  5.136 0 5.16 0.192 ;
    END
  END r_o[42]
  PIN r_o[430]
    DIRECTION OUTPUT ;
    USE SIGNAL ;
    PORT
      LAYER M5 ;
        RECT  33.312 0 33.336 0.192 ;
    END
  END r_o[430]
  PIN r_o[431]
    DIRECTION OUTPUT ;
    USE SIGNAL ;
    PORT
      LAYER M3 ;
        RECT  33.264 0 33.282 0.038 ;
    END
  END r_o[431]
  PIN r_o[432]
    DIRECTION OUTPUT ;
    USE SIGNAL ;
    PORT
      LAYER M5 ;
        RECT  33.408 0 33.432 0.192 ;
    END
  END r_o[432]
  PIN r_o[433]
    DIRECTION OUTPUT ;
    USE SIGNAL ;
    PORT
      LAYER M3 ;
        RECT  33.336 0 33.354 0.038 ;
    END
  END r_o[433]
  PIN r_o[434]
    DIRECTION OUTPUT ;
    USE SIGNAL ;
    PORT
      LAYER M5 ;
        RECT  33.504 0 33.528 0.192 ;
    END
  END r_o[434]
  PIN r_o[435]
    DIRECTION OUTPUT ;
    USE SIGNAL ;
    PORT
      LAYER M3 ;
        RECT  33.408 0 33.426 0.038 ;
    END
  END r_o[435]
  PIN r_o[436]
    DIRECTION OUTPUT ;
    USE SIGNAL ;
    PORT
      LAYER M5 ;
        RECT  33.6 0 33.624 0.192 ;
    END
  END r_o[436]
  PIN r_o[437]
    DIRECTION OUTPUT ;
    USE SIGNAL ;
    PORT
      LAYER M3 ;
        RECT  33.48 0 33.498 0.038 ;
    END
  END r_o[437]
  PIN r_o[438]
    DIRECTION OUTPUT ;
    USE SIGNAL ;
    PORT
      LAYER M5 ;
        RECT  33.696 0 33.72 0.192 ;
    END
  END r_o[438]
  PIN r_o[439]
    DIRECTION OUTPUT ;
    USE SIGNAL ;
    PORT
      LAYER M3 ;
        RECT  33.552 0 33.57 0.038 ;
    END
  END r_o[439]
  PIN r_o[43]
    DIRECTION OUTPUT ;
    USE SIGNAL ;
    PORT
      LAYER M3 ;
        RECT  5.256 0 5.274 0.038 ;
    END
  END r_o[43]
  PIN r_o[440]
    DIRECTION OUTPUT ;
    USE SIGNAL ;
    PORT
      LAYER M5 ;
        RECT  33.792 0 33.816 0.192 ;
    END
  END r_o[440]
  PIN r_o[441]
    DIRECTION OUTPUT ;
    USE SIGNAL ;
    PORT
      LAYER M3 ;
        RECT  33.624 0 33.642 0.038 ;
    END
  END r_o[441]
  PIN r_o[442]
    DIRECTION OUTPUT ;
    USE SIGNAL ;
    PORT
      LAYER M5 ;
        RECT  33.888 0 33.912 0.192 ;
    END
  END r_o[442]
  PIN r_o[443]
    DIRECTION OUTPUT ;
    USE SIGNAL ;
    PORT
      LAYER M3 ;
        RECT  33.768 0 33.786 0.038 ;
    END
  END r_o[443]
  PIN r_o[444]
    DIRECTION OUTPUT ;
    USE SIGNAL ;
    PORT
      LAYER M5 ;
        RECT  33.984 0 34.008 0.192 ;
    END
  END r_o[444]
  PIN r_o[445]
    DIRECTION OUTPUT ;
    USE SIGNAL ;
    PORT
      LAYER M3 ;
        RECT  33.84 0 33.858 0.038 ;
    END
  END r_o[445]
  PIN r_o[446]
    DIRECTION OUTPUT ;
    USE SIGNAL ;
    PORT
      LAYER M5 ;
        RECT  34.08 0 34.104 0.192 ;
    END
  END r_o[446]
  PIN r_o[447]
    DIRECTION OUTPUT ;
    USE SIGNAL ;
    PORT
      LAYER M3 ;
        RECT  33.984 0 34.002 0.038 ;
    END
  END r_o[447]
  PIN r_o[448]
    DIRECTION OUTPUT ;
    USE SIGNAL ;
    PORT
      LAYER M5 ;
        RECT  34.176 0 34.2 0.192 ;
    END
  END r_o[448]
  PIN r_o[449]
    DIRECTION OUTPUT ;
    USE SIGNAL ;
    PORT
      LAYER M3 ;
        RECT  34.128 0 34.146 0.038 ;
    END
  END r_o[449]
  PIN r_o[44]
    DIRECTION OUTPUT ;
    USE SIGNAL ;
    PORT
      LAYER M5 ;
        RECT  5.328 0 5.352 0.192 ;
    END
  END r_o[44]
  PIN r_o[450]
    DIRECTION OUTPUT ;
    USE SIGNAL ;
    PORT
      LAYER M5 ;
        RECT  34.272 0 34.296 0.192 ;
    END
  END r_o[450]
  PIN r_o[451]
    DIRECTION OUTPUT ;
    USE SIGNAL ;
    PORT
      LAYER M3 ;
        RECT  34.272 0 34.29 0.038 ;
    END
  END r_o[451]
  PIN r_o[452]
    DIRECTION OUTPUT ;
    USE SIGNAL ;
    PORT
      LAYER M5 ;
        RECT  34.368 0 34.392 0.192 ;
    END
  END r_o[452]
  PIN r_o[453]
    DIRECTION OUTPUT ;
    USE SIGNAL ;
    PORT
      LAYER M3 ;
        RECT  34.416 0 34.434 0.038 ;
    END
  END r_o[453]
  PIN r_o[454]
    DIRECTION OUTPUT ;
    USE SIGNAL ;
    PORT
      LAYER M5 ;
        RECT  34.56 0 34.584 0.192 ;
    END
  END r_o[454]
  PIN r_o[455]
    DIRECTION OUTPUT ;
    USE SIGNAL ;
    PORT
      LAYER M3 ;
        RECT  34.56 0 34.578 0.038 ;
    END
  END r_o[455]
  PIN r_o[456]
    DIRECTION OUTPUT ;
    USE SIGNAL ;
    PORT
      LAYER M5 ;
        RECT  34.656 0 34.68 0.192 ;
    END
  END r_o[456]
  PIN r_o[457]
    DIRECTION OUTPUT ;
    USE SIGNAL ;
    PORT
      LAYER M3 ;
        RECT  34.704 0 34.722 0.038 ;
    END
  END r_o[457]
  PIN r_o[458]
    DIRECTION OUTPUT ;
    USE SIGNAL ;
    PORT
      LAYER M5 ;
        RECT  34.752 0 34.776 0.192 ;
    END
  END r_o[458]
  PIN r_o[459]
    DIRECTION OUTPUT ;
    USE SIGNAL ;
    PORT
      LAYER M3 ;
        RECT  34.848 0 34.866 0.038 ;
    END
  END r_o[459]
  PIN r_o[45]
    DIRECTION OUTPUT ;
    USE SIGNAL ;
    PORT
      LAYER M3 ;
        RECT  5.4 0 5.418 0.038 ;
    END
  END r_o[45]
  PIN r_o[460]
    DIRECTION OUTPUT ;
    USE SIGNAL ;
    PORT
      LAYER M5 ;
        RECT  34.944 0 34.968 0.192 ;
    END
  END r_o[460]
  PIN r_o[461]
    DIRECTION OUTPUT ;
    USE SIGNAL ;
    PORT
      LAYER M3 ;
        RECT  34.992 0 35.01 0.038 ;
    END
  END r_o[461]
  PIN r_o[462]
    DIRECTION OUTPUT ;
    USE SIGNAL ;
    PORT
      LAYER M5 ;
        RECT  35.04 0 35.064 0.192 ;
    END
  END r_o[462]
  PIN r_o[463]
    DIRECTION OUTPUT ;
    USE SIGNAL ;
    PORT
      LAYER M3 ;
        RECT  35.136 0 35.154 0.038 ;
    END
  END r_o[463]
  PIN r_o[464]
    DIRECTION OUTPUT ;
    USE SIGNAL ;
    PORT
      LAYER M5 ;
        RECT  35.232 0 35.256 0.192 ;
    END
  END r_o[464]
  PIN r_o[465]
    DIRECTION OUTPUT ;
    USE SIGNAL ;
    PORT
      LAYER M3 ;
        RECT  35.28 0 35.298 0.038 ;
    END
  END r_o[465]
  PIN r_o[466]
    DIRECTION OUTPUT ;
    USE SIGNAL ;
    PORT
      LAYER M5 ;
        RECT  35.328 0 35.352 0.192 ;
    END
  END r_o[466]
  PIN r_o[467]
    DIRECTION OUTPUT ;
    USE SIGNAL ;
    PORT
      LAYER M3 ;
        RECT  35.424 0 35.442 0.038 ;
    END
  END r_o[467]
  PIN r_o[468]
    DIRECTION OUTPUT ;
    USE SIGNAL ;
    PORT
      LAYER M5 ;
        RECT  35.52 0 35.544 0.192 ;
    END
  END r_o[468]
  PIN r_o[469]
    DIRECTION OUTPUT ;
    USE SIGNAL ;
    PORT
      LAYER M3 ;
        RECT  35.568 0 35.586 0.038 ;
    END
  END r_o[469]
  PIN r_o[46]
    DIRECTION OUTPUT ;
    USE SIGNAL ;
    PORT
      LAYER M5 ;
        RECT  5.424 0 5.448 0.192 ;
    END
  END r_o[46]
  PIN r_o[470]
    DIRECTION OUTPUT ;
    USE SIGNAL ;
    PORT
      LAYER M5 ;
        RECT  35.616 0 35.64 0.192 ;
    END
  END r_o[470]
  PIN r_o[471]
    DIRECTION OUTPUT ;
    USE SIGNAL ;
    PORT
      LAYER M3 ;
        RECT  35.712 0 35.73 0.038 ;
    END
  END r_o[471]
  PIN r_o[472]
    DIRECTION OUTPUT ;
    USE SIGNAL ;
    PORT
      LAYER M5 ;
        RECT  35.808 0 35.832 0.192 ;
    END
  END r_o[472]
  PIN r_o[473]
    DIRECTION OUTPUT ;
    USE SIGNAL ;
    PORT
      LAYER M3 ;
        RECT  35.856 0 35.874 0.038 ;
    END
  END r_o[473]
  PIN r_o[474]
    DIRECTION OUTPUT ;
    USE SIGNAL ;
    PORT
      LAYER M5 ;
        RECT  35.904 0 35.928 0.192 ;
    END
  END r_o[474]
  PIN r_o[475]
    DIRECTION OUTPUT ;
    USE SIGNAL ;
    PORT
      LAYER M3 ;
        RECT  36 0 36.018 0.038 ;
    END
  END r_o[475]
  PIN r_o[476]
    DIRECTION OUTPUT ;
    USE SIGNAL ;
    PORT
      LAYER M5 ;
        RECT  36.096 0 36.12 0.192 ;
    END
  END r_o[476]
  PIN r_o[477]
    DIRECTION OUTPUT ;
    USE SIGNAL ;
    PORT
      LAYER M3 ;
        RECT  36.144 0 36.162 0.038 ;
    END
  END r_o[477]
  PIN r_o[478]
    DIRECTION OUTPUT ;
    USE SIGNAL ;
    PORT
      LAYER M5 ;
        RECT  36.192 0 36.216 0.192 ;
    END
  END r_o[478]
  PIN r_o[479]
    DIRECTION OUTPUT ;
    USE SIGNAL ;
    PORT
      LAYER M3 ;
        RECT  36.288 0 36.306 0.038 ;
    END
  END r_o[479]
  PIN r_o[47]
    DIRECTION OUTPUT ;
    USE SIGNAL ;
    PORT
      LAYER M3 ;
        RECT  5.544 0 5.562 0.038 ;
    END
  END r_o[47]
  PIN r_o[480]
    DIRECTION OUTPUT ;
    USE SIGNAL ;
    PORT
      LAYER M5 ;
        RECT  36.384 0 36.408 0.192 ;
    END
  END r_o[480]
  PIN r_o[481]
    DIRECTION OUTPUT ;
    USE SIGNAL ;
    PORT
      LAYER M3 ;
        RECT  36.432 0 36.45 0.038 ;
    END
  END r_o[481]
  PIN r_o[482]
    DIRECTION OUTPUT ;
    USE SIGNAL ;
    PORT
      LAYER M5 ;
        RECT  36.48 0 36.504 0.192 ;
    END
  END r_o[482]
  PIN r_o[483]
    DIRECTION OUTPUT ;
    USE SIGNAL ;
    PORT
      LAYER M3 ;
        RECT  36.576 0 36.594 0.038 ;
    END
  END r_o[483]
  PIN r_o[484]
    DIRECTION OUTPUT ;
    USE SIGNAL ;
    PORT
      LAYER M5 ;
        RECT  36.672 0 36.696 0.192 ;
    END
  END r_o[484]
  PIN r_o[485]
    DIRECTION OUTPUT ;
    USE SIGNAL ;
    PORT
      LAYER M3 ;
        RECT  36.72 0 36.738 0.038 ;
    END
  END r_o[485]
  PIN r_o[486]
    DIRECTION OUTPUT ;
    USE SIGNAL ;
    PORT
      LAYER M5 ;
        RECT  36.768 0 36.792 0.192 ;
    END
  END r_o[486]
  PIN r_o[487]
    DIRECTION OUTPUT ;
    USE SIGNAL ;
    PORT
      LAYER M3 ;
        RECT  36.864 0 36.882 0.038 ;
    END
  END r_o[487]
  PIN r_o[488]
    DIRECTION OUTPUT ;
    USE SIGNAL ;
    PORT
      LAYER M5 ;
        RECT  36.96 0 36.984 0.192 ;
    END
  END r_o[488]
  PIN r_o[489]
    DIRECTION OUTPUT ;
    USE SIGNAL ;
    PORT
      LAYER M3 ;
        RECT  37.008 0 37.026 0.038 ;
    END
  END r_o[489]
  PIN r_o[48]
    DIRECTION OUTPUT ;
    USE SIGNAL ;
    PORT
      LAYER M5 ;
        RECT  5.52 0 5.544 0.192 ;
    END
  END r_o[48]
  PIN r_o[490]
    DIRECTION OUTPUT ;
    USE SIGNAL ;
    PORT
      LAYER M5 ;
        RECT  37.056 0 37.08 0.192 ;
    END
  END r_o[490]
  PIN r_o[491]
    DIRECTION OUTPUT ;
    USE SIGNAL ;
    PORT
      LAYER M3 ;
        RECT  37.152 0 37.17 0.038 ;
    END
  END r_o[491]
  PIN r_o[492]
    DIRECTION OUTPUT ;
    USE SIGNAL ;
    PORT
      LAYER M5 ;
        RECT  37.248 0 37.272 0.192 ;
    END
  END r_o[492]
  PIN r_o[493]
    DIRECTION OUTPUT ;
    USE SIGNAL ;
    PORT
      LAYER M3 ;
        RECT  37.296 0 37.314 0.038 ;
    END
  END r_o[493]
  PIN r_o[494]
    DIRECTION OUTPUT ;
    USE SIGNAL ;
    PORT
      LAYER M5 ;
        RECT  37.344 0 37.368 0.192 ;
    END
  END r_o[494]
  PIN r_o[495]
    DIRECTION OUTPUT ;
    USE SIGNAL ;
    PORT
      LAYER M3 ;
        RECT  37.44 0 37.458 0.038 ;
    END
  END r_o[495]
  PIN r_o[496]
    DIRECTION OUTPUT ;
    USE SIGNAL ;
    PORT
      LAYER M5 ;
        RECT  37.536 0 37.56 0.192 ;
    END
  END r_o[496]
  PIN r_o[497]
    DIRECTION OUTPUT ;
    USE SIGNAL ;
    PORT
      LAYER M3 ;
        RECT  37.584 0 37.602 0.038 ;
    END
  END r_o[497]
  PIN r_o[498]
    DIRECTION OUTPUT ;
    USE SIGNAL ;
    PORT
      LAYER M5 ;
        RECT  37.632 0 37.656 0.192 ;
    END
  END r_o[498]
  PIN r_o[499]
    DIRECTION OUTPUT ;
    USE SIGNAL ;
    PORT
      LAYER M3 ;
        RECT  37.728 0 37.746 0.038 ;
    END
  END r_o[499]
  PIN r_o[49]
    DIRECTION OUTPUT ;
    USE SIGNAL ;
    PORT
      LAYER M3 ;
        RECT  6.192 0 6.21 0.038 ;
    END
  END r_o[49]
  PIN r_o[4]
    DIRECTION OUTPUT ;
    USE SIGNAL ;
    PORT
      LAYER M5 ;
        RECT  2.448 0 2.472 0.192 ;
    END
  END r_o[4]
  PIN r_o[500]
    DIRECTION OUTPUT ;
    USE SIGNAL ;
    PORT
      LAYER M5 ;
        RECT  37.824 0 37.848 0.192 ;
    END
  END r_o[500]
  PIN r_o[501]
    DIRECTION OUTPUT ;
    USE SIGNAL ;
    PORT
      LAYER M3 ;
        RECT  37.872 0 37.89 0.038 ;
    END
  END r_o[501]
  PIN r_o[502]
    DIRECTION OUTPUT ;
    USE SIGNAL ;
    PORT
      LAYER M5 ;
        RECT  37.92 0 37.944 0.192 ;
    END
  END r_o[502]
  PIN r_o[503]
    DIRECTION OUTPUT ;
    USE SIGNAL ;
    PORT
      LAYER M3 ;
        RECT  37.944 0 37.962 0.038 ;
    END
  END r_o[503]
  PIN r_o[504]
    DIRECTION OUTPUT ;
    USE SIGNAL ;
    PORT
      LAYER M5 ;
        RECT  38.544 0 38.568 0.192 ;
    END
  END r_o[504]
  PIN r_o[505]
    DIRECTION OUTPUT ;
    USE SIGNAL ;
    PORT
      LAYER M3 ;
        RECT  38.592 0 38.61 0.038 ;
    END
  END r_o[505]
  PIN r_o[506]
    DIRECTION OUTPUT ;
    USE SIGNAL ;
    PORT
      LAYER M5 ;
        RECT  38.64 0 38.664 0.192 ;
    END
  END r_o[506]
  PIN r_o[507]
    DIRECTION OUTPUT ;
    USE SIGNAL ;
    PORT
      LAYER M3 ;
        RECT  38.664 0 38.682 0.038 ;
    END
  END r_o[507]
  PIN r_o[508]
    DIRECTION OUTPUT ;
    USE SIGNAL ;
    PORT
      LAYER M5 ;
        RECT  38.736 0 38.76 0.192 ;
    END
  END r_o[508]
  PIN r_o[509]
    DIRECTION OUTPUT ;
    USE SIGNAL ;
    PORT
      LAYER M3 ;
        RECT  38.736 0 38.754 0.038 ;
    END
  END r_o[509]
  PIN r_o[50]
    DIRECTION OUTPUT ;
    USE SIGNAL ;
    PORT
      LAYER M5 ;
        RECT  6.144 0 6.168 0.192 ;
    END
  END r_o[50]
  PIN r_o[510]
    DIRECTION OUTPUT ;
    USE SIGNAL ;
    PORT
      LAYER M5 ;
        RECT  38.832 0 38.856 0.192 ;
    END
  END r_o[510]
  PIN r_o[511]
    DIRECTION OUTPUT ;
    USE SIGNAL ;
    PORT
      LAYER M3 ;
        RECT  38.808 0 38.826 0.038 ;
    END
  END r_o[511]
  PIN r_o[512]
    DIRECTION OUTPUT ;
    USE SIGNAL ;
    PORT
      LAYER M5 ;
        RECT  38.928 0 38.952 0.192 ;
    END
  END r_o[512]
  PIN r_o[513]
    DIRECTION OUTPUT ;
    USE SIGNAL ;
    PORT
      LAYER M3 ;
        RECT  38.88 0 38.898 0.038 ;
    END
  END r_o[513]
  PIN r_o[514]
    DIRECTION OUTPUT ;
    USE SIGNAL ;
    PORT
      LAYER M5 ;
        RECT  39.024 0 39.048 0.192 ;
    END
  END r_o[514]
  PIN r_o[515]
    DIRECTION OUTPUT ;
    USE SIGNAL ;
    PORT
      LAYER M3 ;
        RECT  38.952 0 38.97 0.038 ;
    END
  END r_o[515]
  PIN r_o[516]
    DIRECTION OUTPUT ;
    USE SIGNAL ;
    PORT
      LAYER M5 ;
        RECT  39.12 0 39.144 0.192 ;
    END
  END r_o[516]
  PIN r_o[517]
    DIRECTION OUTPUT ;
    USE SIGNAL ;
    PORT
      LAYER M3 ;
        RECT  39.024 0 39.042 0.038 ;
    END
  END r_o[517]
  PIN r_o[518]
    DIRECTION OUTPUT ;
    USE SIGNAL ;
    PORT
      LAYER M5 ;
        RECT  39.216 0 39.24 0.192 ;
    END
  END r_o[518]
  PIN r_o[519]
    DIRECTION OUTPUT ;
    USE SIGNAL ;
    PORT
      LAYER M3 ;
        RECT  39.168 0 39.186 0.038 ;
    END
  END r_o[519]
  PIN r_o[51]
    DIRECTION OUTPUT ;
    USE SIGNAL ;
    PORT
      LAYER M3 ;
        RECT  6.264 0 6.282 0.038 ;
    END
  END r_o[51]
  PIN r_o[520]
    DIRECTION OUTPUT ;
    USE SIGNAL ;
    PORT
      LAYER M5 ;
        RECT  39.312 0 39.336 0.192 ;
    END
  END r_o[520]
  PIN r_o[521]
    DIRECTION OUTPUT ;
    USE SIGNAL ;
    PORT
      LAYER M3 ;
        RECT  39.312 0 39.33 0.038 ;
    END
  END r_o[521]
  PIN r_o[522]
    DIRECTION OUTPUT ;
    USE SIGNAL ;
    PORT
      LAYER M5 ;
        RECT  39.408 0 39.432 0.192 ;
    END
  END r_o[522]
  PIN r_o[523]
    DIRECTION OUTPUT ;
    USE SIGNAL ;
    PORT
      LAYER M3 ;
        RECT  39.456 0 39.474 0.038 ;
    END
  END r_o[523]
  PIN r_o[524]
    DIRECTION OUTPUT ;
    USE SIGNAL ;
    PORT
      LAYER M5 ;
        RECT  39.504 0 39.528 0.192 ;
    END
  END r_o[524]
  PIN r_o[525]
    DIRECTION OUTPUT ;
    USE SIGNAL ;
    PORT
      LAYER M3 ;
        RECT  39.6 0 39.618 0.038 ;
    END
  END r_o[525]
  PIN r_o[52]
    DIRECTION OUTPUT ;
    USE SIGNAL ;
    PORT
      LAYER M5 ;
        RECT  6.24 0 6.264 0.192 ;
    END
  END r_o[52]
  PIN r_o[53]
    DIRECTION OUTPUT ;
    USE SIGNAL ;
    PORT
      LAYER M3 ;
        RECT  6.336 0 6.354 0.038 ;
    END
  END r_o[53]
  PIN r_o[54]
    DIRECTION OUTPUT ;
    USE SIGNAL ;
    PORT
      LAYER M5 ;
        RECT  6.336 0 6.36 0.192 ;
    END
  END r_o[54]
  PIN r_o[55]
    DIRECTION OUTPUT ;
    USE SIGNAL ;
    PORT
      LAYER M3 ;
        RECT  6.408 0 6.426 0.038 ;
    END
  END r_o[55]
  PIN r_o[56]
    DIRECTION OUTPUT ;
    USE SIGNAL ;
    PORT
      LAYER M5 ;
        RECT  6.432 0 6.456 0.192 ;
    END
  END r_o[56]
  PIN r_o[57]
    DIRECTION OUTPUT ;
    USE SIGNAL ;
    PORT
      LAYER M3 ;
        RECT  6.48 0 6.498 0.038 ;
    END
  END r_o[57]
  PIN r_o[58]
    DIRECTION OUTPUT ;
    USE SIGNAL ;
    PORT
      LAYER M5 ;
        RECT  6.528 0 6.552 0.192 ;
    END
  END r_o[58]
  PIN r_o[59]
    DIRECTION OUTPUT ;
    USE SIGNAL ;
    PORT
      LAYER M3 ;
        RECT  6.552 0 6.57 0.038 ;
    END
  END r_o[59]
  PIN r_o[5]
    DIRECTION OUTPUT ;
    USE SIGNAL ;
    PORT
      LAYER M3 ;
        RECT  2.52 0 2.538 0.038 ;
    END
  END r_o[5]
  PIN r_o[60]
    DIRECTION OUTPUT ;
    USE SIGNAL ;
    PORT
      LAYER M5 ;
        RECT  6.624 0 6.648 0.192 ;
    END
  END r_o[60]
  PIN r_o[61]
    DIRECTION OUTPUT ;
    USE SIGNAL ;
    PORT
      LAYER M3 ;
        RECT  6.624 0 6.642 0.038 ;
    END
  END r_o[61]
  PIN r_o[62]
    DIRECTION OUTPUT ;
    USE SIGNAL ;
    PORT
      LAYER M5 ;
        RECT  6.72 0 6.744 0.192 ;
    END
  END r_o[62]
  PIN r_o[63]
    DIRECTION OUTPUT ;
    USE SIGNAL ;
    PORT
      LAYER M3 ;
        RECT  6.696 0 6.714 0.038 ;
    END
  END r_o[63]
  PIN r_o[64]
    DIRECTION OUTPUT ;
    USE SIGNAL ;
    PORT
      LAYER M5 ;
        RECT  6.816 0 6.84 0.192 ;
    END
  END r_o[64]
  PIN r_o[65]
    DIRECTION OUTPUT ;
    USE SIGNAL ;
    PORT
      LAYER M3 ;
        RECT  6.84 0 6.858 0.038 ;
    END
  END r_o[65]
  PIN r_o[66]
    DIRECTION OUTPUT ;
    USE SIGNAL ;
    PORT
      LAYER M5 ;
        RECT  6.912 0 6.936 0.192 ;
    END
  END r_o[66]
  PIN r_o[67]
    DIRECTION OUTPUT ;
    USE SIGNAL ;
    PORT
      LAYER M3 ;
        RECT  6.984 0 7.002 0.038 ;
    END
  END r_o[67]
  PIN r_o[68]
    DIRECTION OUTPUT ;
    USE SIGNAL ;
    PORT
      LAYER M5 ;
        RECT  7.008 0 7.032 0.192 ;
    END
  END r_o[68]
  PIN r_o[69]
    DIRECTION OUTPUT ;
    USE SIGNAL ;
    PORT
      LAYER M3 ;
        RECT  7.128 0 7.146 0.038 ;
    END
  END r_o[69]
  PIN r_o[6]
    DIRECTION OUTPUT ;
    USE SIGNAL ;
    PORT
      LAYER M5 ;
        RECT  2.64 0 2.664 0.192 ;
    END
  END r_o[6]
  PIN r_o[70]
    DIRECTION OUTPUT ;
    USE SIGNAL ;
    PORT
      LAYER M5 ;
        RECT  7.2 0 7.224 0.192 ;
    END
  END r_o[70]
  PIN r_o[71]
    DIRECTION OUTPUT ;
    USE SIGNAL ;
    PORT
      LAYER M3 ;
        RECT  7.272 0 7.29 0.038 ;
    END
  END r_o[71]
  PIN r_o[72]
    DIRECTION OUTPUT ;
    USE SIGNAL ;
    PORT
      LAYER M5 ;
        RECT  7.296 0 7.32 0.192 ;
    END
  END r_o[72]
  PIN r_o[73]
    DIRECTION OUTPUT ;
    USE SIGNAL ;
    PORT
      LAYER M3 ;
        RECT  7.416 0 7.434 0.038 ;
    END
  END r_o[73]
  PIN r_o[74]
    DIRECTION OUTPUT ;
    USE SIGNAL ;
    PORT
      LAYER M5 ;
        RECT  7.488 0 7.512 0.192 ;
    END
  END r_o[74]
  PIN r_o[75]
    DIRECTION OUTPUT ;
    USE SIGNAL ;
    PORT
      LAYER M3 ;
        RECT  7.56 0 7.578 0.038 ;
    END
  END r_o[75]
  PIN r_o[76]
    DIRECTION OUTPUT ;
    USE SIGNAL ;
    PORT
      LAYER M5 ;
        RECT  7.584 0 7.608 0.192 ;
    END
  END r_o[76]
  PIN r_o[77]
    DIRECTION OUTPUT ;
    USE SIGNAL ;
    PORT
      LAYER M3 ;
        RECT  7.704 0 7.722 0.038 ;
    END
  END r_o[77]
  PIN r_o[78]
    DIRECTION OUTPUT ;
    USE SIGNAL ;
    PORT
      LAYER M5 ;
        RECT  7.776 0 7.8 0.192 ;
    END
  END r_o[78]
  PIN r_o[79]
    DIRECTION OUTPUT ;
    USE SIGNAL ;
    PORT
      LAYER M3 ;
        RECT  7.848 0 7.866 0.038 ;
    END
  END r_o[79]
  PIN r_o[7]
    DIRECTION OUTPUT ;
    USE SIGNAL ;
    PORT
      LAYER M3 ;
        RECT  2.664 0 2.682 0.038 ;
    END
  END r_o[7]
  PIN r_o[80]
    DIRECTION OUTPUT ;
    USE SIGNAL ;
    PORT
      LAYER M5 ;
        RECT  7.872 0 7.896 0.192 ;
    END
  END r_o[80]
  PIN r_o[81]
    DIRECTION OUTPUT ;
    USE SIGNAL ;
    PORT
      LAYER M3 ;
        RECT  7.92 0 7.938 0.038 ;
    END
  END r_o[81]
  PIN r_o[82]
    DIRECTION OUTPUT ;
    USE SIGNAL ;
    PORT
      LAYER M5 ;
        RECT  8.064 0 8.088 0.192 ;
    END
  END r_o[82]
  PIN r_o[83]
    DIRECTION OUTPUT ;
    USE SIGNAL ;
    PORT
      LAYER M3 ;
        RECT  8.064 0 8.082 0.038 ;
    END
  END r_o[83]
  PIN r_o[84]
    DIRECTION OUTPUT ;
    USE SIGNAL ;
    PORT
      LAYER M5 ;
        RECT  8.16 0 8.184 0.192 ;
    END
  END r_o[84]
  PIN r_o[85]
    DIRECTION OUTPUT ;
    USE SIGNAL ;
    PORT
      LAYER M3 ;
        RECT  8.208 0 8.226 0.038 ;
    END
  END r_o[85]
  PIN r_o[86]
    DIRECTION OUTPUT ;
    USE SIGNAL ;
    PORT
      LAYER M5 ;
        RECT  8.352 0 8.376 0.192 ;
    END
  END r_o[86]
  PIN r_o[87]
    DIRECTION OUTPUT ;
    USE SIGNAL ;
    PORT
      LAYER M3 ;
        RECT  8.352 0 8.37 0.038 ;
    END
  END r_o[87]
  PIN r_o[88]
    DIRECTION OUTPUT ;
    USE SIGNAL ;
    PORT
      LAYER M5 ;
        RECT  8.448 0 8.472 0.192 ;
    END
  END r_o[88]
  PIN r_o[89]
    DIRECTION OUTPUT ;
    USE SIGNAL ;
    PORT
      LAYER M3 ;
        RECT  8.496 0 8.514 0.038 ;
    END
  END r_o[89]
  PIN r_o[8]
    DIRECTION OUTPUT ;
    USE SIGNAL ;
    PORT
      LAYER M5 ;
        RECT  2.736 0 2.76 0.192 ;
    END
  END r_o[8]
  PIN r_o[90]
    DIRECTION OUTPUT ;
    USE SIGNAL ;
    PORT
      LAYER M5 ;
        RECT  8.64 0 8.664 0.192 ;
    END
  END r_o[90]
  PIN r_o[91]
    DIRECTION OUTPUT ;
    USE SIGNAL ;
    PORT
      LAYER M3 ;
        RECT  8.64 0 8.658 0.038 ;
    END
  END r_o[91]
  PIN r_o[92]
    DIRECTION OUTPUT ;
    USE SIGNAL ;
    PORT
      LAYER M5 ;
        RECT  8.736 0 8.76 0.192 ;
    END
  END r_o[92]
  PIN r_o[93]
    DIRECTION OUTPUT ;
    USE SIGNAL ;
    PORT
      LAYER M3 ;
        RECT  8.784 0 8.802 0.038 ;
    END
  END r_o[93]
  PIN r_o[94]
    DIRECTION OUTPUT ;
    USE SIGNAL ;
    PORT
      LAYER M5 ;
        RECT  8.832 0 8.856 0.192 ;
    END
  END r_o[94]
  PIN r_o[95]
    DIRECTION OUTPUT ;
    USE SIGNAL ;
    PORT
      LAYER M3 ;
        RECT  8.928 0 8.946 0.038 ;
    END
  END r_o[95]
  PIN r_o[96]
    DIRECTION OUTPUT ;
    USE SIGNAL ;
    PORT
      LAYER M5 ;
        RECT  9.024 0 9.048 0.192 ;
    END
  END r_o[96]
  PIN r_o[97]
    DIRECTION OUTPUT ;
    USE SIGNAL ;
    PORT
      LAYER M3 ;
        RECT  9.072 0 9.09 0.038 ;
    END
  END r_o[97]
  PIN r_o[98]
    DIRECTION OUTPUT ;
    USE SIGNAL ;
    PORT
      LAYER M5 ;
        RECT  9.12 0 9.144 0.192 ;
    END
  END r_o[98]
  PIN r_o[99]
    DIRECTION OUTPUT ;
    USE SIGNAL ;
    PORT
      LAYER M3 ;
        RECT  9.216 0 9.234 0.038 ;
    END
  END r_o[99]
  PIN r_o[9]
    DIRECTION OUTPUT ;
    USE SIGNAL ;
    PORT
      LAYER M3 ;
        RECT  2.808 0 2.826 0.038 ;
    END
  END r_o[9]
  PIN VDD
    DIRECTION INOUT ;
    USE POWER ;
    PORT
      LAYER M5 ;
        RECT  40.392 2.151 40.512 17.289 ;
        RECT  34.992 2.151 35.112 17.289 ;
        RECT  29.592 2.151 29.712 17.289 ;
        RECT  24.192 2.151 24.312 17.289 ;
        RECT  18.792 2.151 18.912 17.289 ;
        RECT  13.392 2.151 13.512 17.289 ;
        RECT  7.992 2.151 8.112 17.289 ;
        RECT  2.592 2.151 2.712 17.289 ;
    END
  END VDD
  PIN VSS
    DIRECTION INOUT ;
    USE GROUND ;
    PORT
      LAYER M5 ;
        RECT  40.2 2.137 40.32 17.303 ;
        RECT  34.8 2.137 34.92 17.303 ;
        RECT  29.4 2.137 29.52 17.303 ;
        RECT  24 2.137 24.12 17.303 ;
        RECT  18.6 2.137 18.72 17.303 ;
        RECT  13.2 2.137 13.32 17.303 ;
        RECT  7.8 2.137 7.92 17.303 ;
        RECT  2.4 2.137 2.52 17.303 ;
    END
  END VSS
  # OT_OBS_CLOSED layer=M5 d_um=1.536 added=96
  OBS
    LAYER RVTN ;
     RECT  2.16 2.16 41.04 2.295 ;
     RECT  2.16 2.565 41.04 2.835 ;
     RECT  2.16 3.105 41.04 3.375 ;
     RECT  2.16 3.645 41.04 3.915 ;
     RECT  2.16 4.185 41.04 4.455 ;
     RECT  2.16 4.725 41.04 4.995 ;
     RECT  2.16 5.265 41.04 5.535 ;
     RECT  2.16 5.805 41.04 6.075 ;
     RECT  2.16 6.345 41.04 6.615 ;
     RECT  2.16 6.885 41.04 7.155 ;
     RECT  2.16 7.425 41.04 7.695 ;
     RECT  2.16 7.965 41.04 8.235 ;
     RECT  2.16 8.505 41.04 8.775 ;
     RECT  2.16 9.045 41.04 9.315 ;
     RECT  2.16 9.585 41.04 9.855 ;
     RECT  2.16 10.125 41.04 10.395 ;
     RECT  2.16 10.665 41.04 10.935 ;
     RECT  2.16 11.205 41.04 11.475 ;
     RECT  2.16 11.745 41.04 12.015 ;
     RECT  2.16 12.285 41.04 12.555 ;
     RECT  2.16 12.825 41.04 13.095 ;
     RECT  2.16 13.365 41.04 13.635 ;
     RECT  2.16 13.905 41.04 14.175 ;
     RECT  2.16 14.445 41.04 14.715 ;
     RECT  2.16 14.985 41.04 15.255 ;
     RECT  2.16 15.525 41.04 15.795 ;
     RECT  2.16 16.065 41.04 16.335 ;
     RECT  2.16 16.605 41.04 16.875 ;
     RECT  2.16 17.145 41.04 17.28 ;
    LAYER RVTP ;
     RECT  2.16 2.295 41.04 2.565 ;
     RECT  2.16 2.835 41.04 3.105 ;
     RECT  2.16 3.375 41.04 3.645 ;
     RECT  2.16 3.915 41.04 4.185 ;
     RECT  2.16 4.455 41.04 4.725 ;
     RECT  2.16 4.995 41.04 5.265 ;
     RECT  2.16 5.535 41.04 5.805 ;
     RECT  2.16 6.075 41.04 6.345 ;
     RECT  2.16 6.615 41.04 6.885 ;
     RECT  2.16 7.155 41.04 7.425 ;
     RECT  2.16 7.695 41.04 7.965 ;
     RECT  2.16 8.235 41.04 8.505 ;
     RECT  2.16 8.775 41.04 9.045 ;
     RECT  2.16 9.315 41.04 9.585 ;
     RECT  2.16 9.855 41.04 10.125 ;
     RECT  2.16 10.395 41.04 10.665 ;
     RECT  2.16 10.935 41.04 11.205 ;
     RECT  2.16 11.475 41.04 11.745 ;
     RECT  2.16 12.015 41.04 12.285 ;
     RECT  2.16 12.555 41.04 12.825 ;
     RECT  2.16 13.095 41.04 13.365 ;
     RECT  2.16 13.635 41.04 13.905 ;
     RECT  2.16 14.175 41.04 14.445 ;
     RECT  2.16 14.715 41.04 14.985 ;
     RECT  2.16 15.255 41.04 15.525 ;
     RECT  2.16 15.795 41.04 16.065 ;
     RECT  2.16 16.335 41.04 16.605 ;
     RECT  2.16 16.875 41.04 17.145 ;
    LAYER M1 ;
     RECT  2.16 2.151 41.04 17.289 ;
    LAYER M2 ;
     RECT  2.299 1.26 2.335 1.278 ;
     RECT  2.16 2.151 2.335 17.289 ;
     RECT  2.335 1.26 2.371 17.289 ;
     RECT  2.371 0.036 2.515 0.054 ;
     RECT  2.371 1.26 2.623 17.514 ;
     RECT  2.623 1.152 2.723 17.514 ;
     RECT  2.723 1.152 2.795 1.359 ;
     RECT  2.723 2.151 2.803 17.514 ;
     RECT  2.515 0.036 3.019 0.126 ;
     RECT  2.803 2.151 3.191 17.676 ;
     RECT  3.019 0.036 3.407 0.198 ;
     RECT  3.739 1.152 3.883 1.17 ;
     RECT  3.191 2.151 3.883 17.334 ;
     RECT  3.407 0.036 3.983 0.126 ;
     RECT  3.883 1.152 3.983 17.334 ;
     RECT  3.983 1.152 4.559 17.289 ;
     RECT  4.559 1.152 4.991 1.242 ;
     RECT  3.983 0.036 4.999 0.054 ;
     RECT  4.999 0.036 5.135 0.126 ;
     RECT  4.559 2.151 6.187 17.289 ;
     RECT  6.043 18.81 6.215 18.828 ;
     RECT  5.135 0.036 6.223 0.054 ;
     RECT  6.223 0.036 6.431 0.198 ;
     RECT  6.187 2.106 6.539 17.289 ;
     RECT  6.439 18.774 6.575 18.792 ;
     RECT  6.539 2.151 6.691 17.289 ;
     RECT  6.691 2.151 6.791 17.334 ;
     RECT  6.791 2.151 7.555 17.289 ;
     RECT  7.555 2.034 7.771 17.289 ;
     RECT  7.771 2.034 7.843 17.37 ;
     RECT  7.483 18.774 7.843 18.792 ;
     RECT  7.843 1.728 7.943 17.37 ;
     RECT  7.843 18.774 7.979 18.828 ;
     RECT  7.979 18.774 8.843 18.792 ;
     RECT  6.431 0.036 9.095 0.126 ;
     RECT  7.943 1.728 9.095 17.289 ;
     RECT  9.095 2.106 9.347 17.289 ;
     RECT  9.139 1.152 9.455 1.17 ;
     RECT  9.095 0.036 9.931 0.054 ;
     RECT  9.347 2.151 9.931 17.289 ;
     RECT  9.931 2.151 10.075 17.334 ;
     RECT  10.075 2.106 10.139 17.334 ;
     RECT  10.003 18.234 10.391 18.252 ;
     RECT  10.363 1.152 10.499 1.17 ;
     RECT  9.931 0.036 10.751 0.198 ;
     RECT  10.751 0.18 10.823 0.198 ;
     RECT  10.139 2.106 10.939 17.289 ;
     RECT  10.939 1.728 11.227 17.289 ;
     RECT  11.623 19.386 11.759 19.404 ;
     RECT  11.227 1.152 11.903 17.289 ;
     RECT  11.695 0.036 12.091 0.054 ;
     RECT  12.091 0.036 12.271 0.126 ;
     RECT  11.903 1.152 12.335 1.359 ;
     RECT  12.271 0.036 12.407 0.198 ;
     RECT  12.335 1.152 12.407 1.278 ;
     RECT  12.407 0.036 12.551 0.126 ;
     RECT  11.903 2.151 12.919 17.289 ;
     RECT  12.407 1.152 12.947 1.242 ;
     RECT  12.551 0.036 12.983 0.09 ;
     RECT  12.947 1.224 13.055 1.242 ;
     RECT  12.919 2.106 13.135 17.289 ;
     RECT  13.135 2.106 13.243 17.37 ;
     RECT  13.243 1.728 13.271 17.37 ;
     RECT  13.271 1.728 13.783 17.289 ;
     RECT  13.783 1.152 14.171 17.289 ;
     RECT  14.171 1.728 14.747 17.289 ;
     RECT  12.983 0.036 15.043 0.054 ;
     RECT  15.043 0.036 15.187 0.09 ;
     RECT  15.187 0.036 15.287 0.126 ;
     RECT  15.223 1.152 15.619 1.17 ;
     RECT  14.747 2.151 15.619 17.289 ;
     RECT  15.619 1.152 15.827 17.289 ;
     RECT  15.287 0.036 16.051 0.054 ;
     RECT  16.051 0.036 16.151 0.126 ;
     RECT  15.827 1.152 16.187 1.17 ;
     RECT  16.151 0.108 17.203 0.126 ;
     RECT  17.095 19.386 17.231 19.404 ;
     RECT  15.827 2.151 17.347 17.289 ;
     RECT  17.203 0.108 17.419 0.198 ;
     RECT  17.347 1.728 17.635 17.289 ;
     RECT  17.419 18.774 17.663 18.864 ;
     RECT  17.635 1.656 17.771 17.289 ;
     RECT  17.771 1.692 17.851 17.289 ;
     RECT  17.419 0.036 18.095 0.198 ;
     RECT  17.851 1.692 18.239 17.334 ;
     RECT  18.239 1.692 18.311 17.289 ;
     RECT  18.463 18.81 19.175 18.828 ;
     RECT  18.095 0.036 19.391 0.126 ;
     RECT  18.311 2.106 19.507 17.289 ;
     RECT  19.391 0.036 20.227 0.054 ;
     RECT  20.227 0.036 20.371 0.126 ;
     RECT  20.371 0.036 20.471 0.162 ;
     RECT  20.227 18.702 20.623 18.72 ;
     RECT  20.471 0.036 20.759 0.126 ;
     RECT  19.507 1.728 20.867 17.289 ;
     RECT  20.623 18.702 20.903 18.792 ;
     RECT  20.759 0.036 21.407 0.054 ;
     RECT  20.867 1.8 21.739 17.289 ;
     RECT  21.739 1.728 22.091 17.289 ;
     RECT  22.639 0.036 22.819 0.054 ;
     RECT  22.423 1.152 22.891 1.17 ;
     RECT  22.351 18.81 22.891 18.828 ;
     RECT  22.819 0.036 22.919 0.126 ;
     RECT  22.891 18.81 23.107 18.909 ;
     RECT  22.091 2.151 23.215 17.289 ;
     RECT  22.919 0.036 23.279 0.054 ;
     RECT  23.215 2.151 23.315 17.712 ;
     RECT  22.891 1.152 23.323 1.242 ;
     RECT  23.315 2.151 23.323 17.289 ;
     RECT  23.107 18.54 23.351 18.909 ;
     RECT  23.351 18.54 23.495 18.792 ;
     RECT  24.043 0.108 24.331 0.126 ;
     RECT  24.331 0.036 24.367 0.126 ;
     RECT  23.495 18.774 24.719 18.792 ;
     RECT  23.323 1.152 25.079 17.289 ;
     RECT  24.367 0.036 25.151 0.198 ;
     RECT  25.079 1.728 25.547 17.289 ;
     RECT  25.807 18.774 26.059 18.792 ;
     RECT  25.151 0.036 26.095 0.126 ;
     RECT  26.095 1.224 26.131 1.242 ;
     RECT  26.095 0.036 26.231 0.198 ;
     RECT  26.131 1.152 26.347 1.242 ;
     RECT  25.547 2.106 26.347 17.289 ;
     RECT  26.347 1.152 26.591 17.289 ;
     RECT  26.059 18.702 26.663 18.792 ;
     RECT  26.231 0.036 26.951 0.126 ;
     RECT  26.951 0.036 27.275 0.054 ;
     RECT  26.663 18.774 27.347 18.792 ;
     RECT  26.591 1.152 28.003 1.17 ;
     RECT  26.591 2.151 28.003 17.289 ;
     RECT  27.967 18.666 28.039 18.756 ;
     RECT  28.039 0.036 28.075 0.054 ;
     RECT  28.039 18.621 28.139 18.756 ;
     RECT  28.139 18.702 28.363 18.756 ;
     RECT  28.003 1.152 28.427 17.289 ;
     RECT  28.363 18.702 28.463 18.792 ;
     RECT  28.463 18.774 28.499 18.792 ;
     RECT  28.427 2.106 28.831 17.289 ;
     RECT  28.831 2.106 29.039 17.712 ;
     RECT  28.427 1.152 29.227 1.17 ;
     RECT  28.075 0.036 29.615 0.126 ;
     RECT  29.227 1.152 29.731 1.359 ;
     RECT  29.039 2.106 29.731 17.289 ;
     RECT  29.875 18.774 29.911 18.792 ;
     RECT  29.911 18.774 30.047 18.828 ;
     RECT  30.047 18.774 30.155 18.792 ;
     RECT  29.731 1.152 30.515 17.289 ;
     RECT  29.615 0.036 30.775 0.054 ;
     RECT  30.515 1.152 31.019 1.242 ;
     RECT  30.775 0.036 31.099 0.126 ;
     RECT  31.099 0.036 31.235 0.198 ;
     RECT  31.235 0.18 31.343 0.198 ;
     RECT  31.019 1.152 31.739 1.17 ;
     RECT  30.515 2.151 31.747 17.289 ;
     RECT  31.603 18.774 31.819 18.792 ;
     RECT  31.747 1.224 31.883 1.242 ;
     RECT  31.747 2.151 31.919 17.712 ;
     RECT  32.035 0.036 32.323 0.054 ;
     RECT  32.323 0.036 32.495 0.126 ;
     RECT  31.819 18.702 32.495 18.792 ;
     RECT  32.495 18.774 33.431 18.792 ;
     RECT  32.495 0.036 33.619 0.054 ;
     RECT  33.691 18.81 33.871 18.828 ;
     RECT  33.619 0.036 33.943 0.126 ;
     RECT  33.871 18.81 34.007 18.909 ;
     RECT  31.919 2.151 34.015 17.289 ;
     RECT  33.943 0.036 34.151 0.198 ;
     RECT  34.015 2.151 34.151 17.604 ;
     RECT  34.267 18.774 34.403 18.792 ;
     RECT  34.151 2.151 35.131 17.289 ;
     RECT  35.131 1.728 35.851 17.289 ;
     RECT  34.771 18.81 35.995 18.828 ;
     RECT  34.151 0.036 36.139 0.054 ;
     RECT  35.995 18.774 36.139 18.828 ;
     RECT  36.139 18.774 36.275 18.864 ;
     RECT  35.851 1.656 36.347 17.289 ;
     RECT  36.139 0.036 37.031 0.126 ;
     RECT  36.275 18.774 37.283 18.792 ;
     RECT  36.347 2.151 37.867 17.289 ;
     RECT  37.435 18.81 38.003 18.828 ;
     RECT  37.031 0.036 38.515 0.09 ;
     RECT  38.875 18.774 39.155 18.792 ;
     RECT  38.515 0.036 39.335 0.126 ;
     RECT  37.255 1.152 39.335 1.17 ;
     RECT  37.867 2.106 39.487 17.289 ;
     RECT  39.487 2.034 39.703 17.289 ;
     RECT  39.335 0.036 39.731 0.09 ;
     RECT  39.703 1.962 40.243 17.289 ;
     RECT  40.243 1.962 40.531 17.37 ;
     RECT  39.731 0.036 40.631 0.054 ;
     RECT  40.531 1.962 40.631 17.442 ;
     RECT  40.631 1.962 40.883 17.289 ;
     RECT  40.675 18.774 41.027 18.792 ;
     RECT  40.883 2.151 41.04 17.289 ;
     RECT  41.04 7.776 41.063 8.532 ;
     RECT  41.04 14.148 41.063 14.814 ;
     RECT  41.063 7.776 41.099 7.794 ;
     RECT  41.04 12.528 41.099 12.546 ;
     RECT  41.04 9.936 41.135 9.954 ;
     RECT  41.063 14.49 41.135 14.508 ;
    LAYER M3 ;
     RECT  2.232 0.012 40.986 2.641 ;
     RECT  2.232 2.641 41.022 2.669 ;
     RECT  2.304 2.669 41.022 3.979 ;
     RECT  2.196 3.979 41.022 4.649 ;
     RECT  2.34 4.649 41.022 6.341 ;
     RECT  2.34 6.341 40.986 6.385 ;
     RECT  2.304 6.385 40.986 7.771 ;
     RECT  2.304 7.771 41.094 9.931 ;
     RECT  2.304 9.931 41.13 14.071 ;
     RECT  2.232 14.071 41.13 14.513 ;
     RECT  2.232 14.513 41.058 15.989 ;
     RECT  2.304 15.989 41.058 16.807 ;
     RECT  2.232 16.807 41.058 18.797 ;
     RECT  2.232 18.797 41.022 18.802 ;
     RECT  2.232 18.802 40.986 19.421 ;
    LAYER M4 ;
     RECT  2.149 14.832 2.285 14.856 ;
     RECT  2.293 17.52 2.341 17.544 ;
     RECT  2.141 3.984 2.408 4.008 ;
     RECT  2.365 7.392 2.408 7.416 ;
     RECT  0.227 9.552 2.408 9.576 ;
     RECT  2.365 12.528 2.408 12.552 ;
     RECT  2.285 14.208 2.408 14.856 ;
     RECT  2.341 17.424 2.408 17.544 ;
     RECT  2.3 0.528 2.437 0.552 ;
     RECT  2.408 2.148 2.629 17.544 ;
     RECT  2.629 1.728 2.653 17.544 ;
     RECT  2.653 1.728 2.704 17.88 ;
     RECT  2.437 0.288 2.725 0.552 ;
     RECT  2.704 15.984 2.819 17.88 ;
     RECT  2.819 15.984 2.837 17.496 ;
     RECT  2.725 0.192 2.867 0.552 ;
     RECT  2.861 19.296 2.876 19.32 ;
     RECT  2.704 9.552 2.917 11.544 ;
     RECT  2.704 6.864 2.945 8.472 ;
     RECT  2.876 19.2 2.945 19.32 ;
     RECT  2.945 19.2 2.963 19.224 ;
     RECT  2.704 3.312 3.341 4.536 ;
     RECT  3.341 3.312 3.443 4.008 ;
     RECT  2.704 12.528 3.491 14.568 ;
     RECT  3.491 12.528 3.565 13.704 ;
     RECT  3.443 3.312 3.629 3.816 ;
     RECT  2.945 6.864 3.683 7.416 ;
     RECT  3.013 0.576 3.701 0.6 ;
     RECT  2.837 15.984 3.733 17.208 ;
     RECT  2.704 1.728 3.781 1.752 ;
     RECT  2.917 9.552 3.809 10.392 ;
     RECT  3.733 15.408 3.817 17.208 ;
     RECT  3.781 1.728 3.845 1.8 ;
     RECT  3.845 1.776 3.877 1.8 ;
     RECT  3.683 7.344 3.917 7.416 ;
     RECT  3.877 1.776 3.953 1.896 ;
     RECT  3.953 1.872 3.961 1.896 ;
     RECT  2.917 11.52 4.021 11.544 ;
     RECT  3.629 3.408 4.025 3.816 ;
     RECT  3.817 15.984 4.057 17.208 ;
     RECT  3.565 13.104 4.061 13.704 ;
     RECT  4.021 11.52 4.105 11.976 ;
     RECT  4.057 15.984 4.277 17.688 ;
     RECT  4.277 17.136 4.453 17.688 ;
     RECT  4.105 11.52 4.601 11.544 ;
     RECT  4.049 0.192 4.741 0.36 ;
     RECT  4.061 13.104 4.741 13.608 ;
     RECT  4.453 17.136 4.787 18.264 ;
     RECT  4.453 2.256 4.849 2.28 ;
     RECT  4.025 3.408 4.849 3.768 ;
     RECT  4.849 2.256 4.889 3.768 ;
     RECT  4.277 15.984 4.889 16.056 ;
     RECT  4.889 2.256 5.029 2.568 ;
     RECT  4.201 5.616 5.029 5.64 ;
     RECT  5.029 1.728 5.069 2.568 ;
     RECT  4.777 10.848 5.123 11.4 ;
     RECT  4.741 0.192 5.125 0.552 ;
     RECT  4.787 18.24 5.171 18.264 ;
     RECT  5.123 10.848 5.245 11.16 ;
     RECT  4.787 17.136 5.276 17.208 ;
     RECT  5.069 1.728 5.393 1.8 ;
     RECT  5.125 0.192 5.537 0.6 ;
     RECT  5.276 17.088 5.555 17.208 ;
     RECT  4.889 15.984 5.749 16.008 ;
     RECT  2.945 8.448 5.785 8.472 ;
     RECT  4.741 12.528 5.825 13.608 ;
     RECT  5.029 3.936 5.833 5.64 ;
     RECT  3.917 7.392 5.861 7.416 ;
     RECT  5.785 8.448 5.891 8.52 ;
     RECT  5.833 5.616 6.001 5.64 ;
     RECT  5.825 12.528 6.085 13.464 ;
     RECT  5.425 18.816 6.085 18.84 ;
     RECT  3.809 9.552 6.109 9.576 ;
     RECT  5.245 10.8 6.109 11.16 ;
     RECT  6.001 5.616 6.133 5.736 ;
     RECT  5.393 1.776 6.145 1.8 ;
     RECT  5.749 15.408 6.145 16.008 ;
     RECT  6.085 18.816 6.179 18.936 ;
     RECT  6.145 14.784 6.181 16.008 ;
     RECT  6.109 9.552 6.227 11.16 ;
     RECT  6.227 11.136 6.325 11.16 ;
     RECT  6.085 12.336 6.325 13.464 ;
     RECT  6.179 18.912 6.365 18.936 ;
     RECT  5.891 8.448 6.397 8.472 ;
     RECT  6.181 14.784 6.421 16.056 ;
     RECT  5.965 17.616 6.467 17.688 ;
     RECT  6.421 14.784 6.517 16.584 ;
     RECT  6.467 17.616 6.517 17.64 ;
     RECT  6.145 1.776 6.541 2.28 ;
     RECT  5.833 3.936 6.541 4.584 ;
     RECT  6.541 1.776 6.605 4.584 ;
     RECT  6.517 14.784 6.613 17.64 ;
     RECT  6.037 6.816 6.653 6.888 ;
     RECT  6.613 14.688 6.755 17.64 ;
     RECT  6.133 5.616 6.85 5.784 ;
     RECT  6.397 7.968 6.853 8.472 ;
     RECT  6.227 9.552 6.853 9.576 ;
     RECT  6.325 11.136 6.901 13.464 ;
     RECT  6.605 1.728 6.973 4.584 ;
     RECT  6.85 5.616 6.973 5.832 ;
     RECT  6.853 7.92 7.189 9.576 ;
     RECT  6.901 11.136 7.189 13.656 ;
     RECT  6.749 19.2 7.333 19.32 ;
     RECT  7.333 18.816 7.417 19.32 ;
     RECT  7.417 18.816 7.523 18.84 ;
     RECT  6.973 1.728 7.808 5.832 ;
     RECT  6.653 6.816 7.808 6.84 ;
     RECT  7.189 7.92 7.808 13.656 ;
     RECT  6.755 14.784 7.808 17.64 ;
     RECT  5.537 0.192 8.053 0.216 ;
     RECT  7.808 1.728 8.104 17.64 ;
     RECT  8.104 17.232 8.108 17.64 ;
     RECT  8.104 7.92 8.165 16.104 ;
     RECT  8.108 17.232 8.195 18.264 ;
     RECT  8.104 2.832 8.243 4.584 ;
     RECT  8.165 7.92 8.273 8.568 ;
     RECT  8.165 9.552 8.387 16.104 ;
     RECT  8.243 3.408 8.417 4.584 ;
     RECT  8.387 9.552 8.489 13.608 ;
     RECT  8.195 17.232 8.497 17.64 ;
     RECT  8.417 3.744 8.561 4.584 ;
     RECT  8.104 1.728 8.777 1.752 ;
     RECT  8.561 3.744 9.001 4.536 ;
     RECT  8.629 18.768 9.065 18.792 ;
     RECT  8.489 11.664 9.1 13.608 ;
     RECT  8.387 14.64 9.133 16.104 ;
     RECT  8.497 17.232 9.133 17.256 ;
     RECT  8.104 5.712 9.205 6.84 ;
     RECT  8.273 7.92 9.205 8.52 ;
     RECT  9.1 11.664 9.281 13.224 ;
     RECT  8.053 0.192 9.301 0.6 ;
     RECT  9.001 3.744 9.397 4.008 ;
     RECT  9.301 0.192 9.425 1.176 ;
     RECT  9.341 19.2 9.443 19.32 ;
     RECT  9.205 5.712 9.539 8.52 ;
     RECT  9.133 14.64 9.539 17.256 ;
     RECT  9.281 12.528 9.613 13.224 ;
     RECT  9.539 7.248 9.683 8.52 ;
     RECT  9.397 3.408 9.685 4.008 ;
     RECT  9.74 19.344 9.827 19.368 ;
     RECT  9.683 7.248 9.857 7.272 ;
     RECT  8.489 9.552 9.925 10.2 ;
     RECT  9.683 8.4 9.961 8.52 ;
     RECT  9.925 9.552 9.961 11.448 ;
     RECT  9.539 5.712 9.965 6.072 ;
     RECT  9.877 1.728 9.973 1.752 ;
     RECT  9.965 5.712 10.009 5.736 ;
     RECT  9.539 14.64 10.045 16.008 ;
     RECT  10.045 14.64 10.081 15.48 ;
     RECT  9.973 1.728 10.165 1.8 ;
     RECT  9.685 2.88 10.165 4.008 ;
     RECT  9.961 8.4 10.181 11.448 ;
     RECT  9.539 17.04 10.211 17.256 ;
     RECT  10.211 17.04 10.217 17.16 ;
     RECT  10.165 1.728 10.289 4.008 ;
     RECT  10.181 11.424 10.289 11.448 ;
     RECT  10.081 14.64 10.393 15.432 ;
     RECT  10.393 14.4 10.501 15.432 ;
     RECT  9.613 12.528 10.541 12.552 ;
     RECT  10.289 1.728 10.613 1.752 ;
     RECT  10.501 14.304 10.681 15.432 ;
     RECT  10.681 14.112 10.721 15.432 ;
     RECT  9.425 0.192 10.741 0.216 ;
     RECT  10.741 18.816 10.837 18.84 ;
     RECT  10.837 18.816 10.861 19.224 ;
     RECT  10.289 2.832 10.933 4.008 ;
     RECT  10.933 2.832 11.081 4.296 ;
     RECT  10.181 8.4 11.117 10.248 ;
     RECT  11.117 8.4 11.149 9.672 ;
     RECT  10.217 17.136 11.221 17.16 ;
     RECT  11.149 7.488 11.225 9.672 ;
     RECT  11.221 17.136 11.317 17.688 ;
     RECT  10.741 0.192 11.473 0.312 ;
     RECT  11.317 16.56 11.693 17.688 ;
     RECT  10.721 14.112 11.708 14.808 ;
     RECT  10.861 18.816 11.788 19.32 ;
     RECT  11.788 19.296 11.809 19.32 ;
     RECT  11.225 7.488 11.843 8.424 ;
     RECT  11.693 17.136 11.905 17.688 ;
     RECT  11.843 7.488 11.941 7.944 ;
     RECT  11.473 0.192 11.981 1.176 ;
     RECT  11.708 14.112 12.089 15 ;
     RECT  11.329 11.376 12.157 11.4 ;
     RECT  11.545 2.256 12.181 2.28 ;
     RECT  11.225 9.408 12.229 9.672 ;
     RECT  12.157 10.992 12.229 11.4 ;
     RECT  12.089 14.208 12.265 15 ;
     RECT  12.181 2.256 12.277 2.328 ;
     RECT  12.229 9.408 12.325 11.4 ;
     RECT  12.277 1.68 12.373 2.328 ;
     RECT  11.081 3.408 12.373 4.296 ;
     RECT  12.337 12.528 12.409 12.552 ;
     RECT  12.373 1.68 12.553 4.296 ;
     RECT  12.517 5.712 12.553 5.736 ;
     RECT  11.905 17.136 12.764 18.264 ;
     RECT  12.764 17.136 12.851 19.176 ;
     RECT  12.325 9.36 12.877 11.4 ;
     RECT  12.409 12.528 12.877 13.128 ;
     RECT  12.553 1.68 12.985 5.736 ;
     RECT  11.941 6.816 12.985 7.944 ;
     RECT  11.981 0.192 13.093 0.648 ;
     RECT  12.985 1.68 13.093 7.944 ;
     RECT  12.877 9.36 13.093 13.128 ;
     RECT  12.265 14.208 13.093 15.432 ;
     RECT  12.851 17.136 13.187 18.84 ;
     RECT  13.093 0.192 13.208 8.28 ;
     RECT  13.093 9.36 13.208 15.432 ;
     RECT  13.187 17.136 13.208 17.448 ;
     RECT  13.208 0.192 13.283 17.448 ;
     RECT  13.283 0.192 13.312 17.4 ;
     RECT  13.312 2.418 13.504 17.4 ;
     RECT  13.312 0.192 13.619 1.272 ;
     RECT  13.504 11.184 13.619 13.224 ;
     RECT  13.504 14.208 13.619 15.864 ;
     RECT  13.619 11.376 13.645 13.224 ;
     RECT  13.504 17.136 13.667 17.4 ;
     RECT  13.645 12.768 13.673 13.224 ;
     RECT  13.504 2.88 13.708 9.816 ;
     RECT  13.673 12.768 13.708 13.128 ;
     RECT  13.619 0.192 13.715 1.176 ;
     RECT  13.619 14.208 13.781 15.816 ;
     RECT  13.708 2.88 14.033 8.28 ;
     RECT  13.781 14.496 14.051 15.816 ;
     RECT  14.033 2.88 14.105 7.704 ;
     RECT  14.105 4.848 14.357 7.704 ;
     RECT  14.357 4.848 14.387 7.224 ;
     RECT  14.387 4.848 14.627 4.872 ;
     RECT  13.187 18.816 14.627 18.84 ;
     RECT  14.387 6.384 14.645 7.224 ;
     RECT  14.051 14.64 14.645 15.816 ;
     RECT  13.708 9.36 14.821 9.816 ;
     RECT  13.667 17.136 14.825 17.256 ;
     RECT  13.715 0.192 14.869 0.312 ;
     RECT  13.708 13.056 14.917 13.128 ;
     RECT  14.869 0.192 14.957 0.6 ;
     RECT  14.645 14.64 14.969 15.48 ;
     RECT  14.105 2.88 15.149 3.768 ;
     RECT  13.645 11.376 15.149 11.4 ;
     RECT  14.917 13.056 15.203 13.176 ;
     RECT  15.157 1.728 15.253 1.752 ;
     RECT  14.969 14.64 15.253 15.384 ;
     RECT  14.821 9.312 15.361 9.816 ;
     RECT  14.957 0.192 15.433 0.696 ;
     RECT  15.253 1.728 15.433 1.848 ;
     RECT  15.433 0.192 15.5 1.848 ;
     RECT  15.361 9.312 15.541 10.248 ;
     RECT  15.5 0.192 15.587 2.712 ;
     RECT  15.541 9.12 15.689 10.248 ;
     RECT  15.587 1.728 15.905 2.328 ;
     RECT  15.905 1.776 15.977 2.328 ;
     RECT  15.253 13.632 15.977 15.384 ;
     RECT  15.689 9.312 16.013 10.248 ;
     RECT  14.825 17.136 16.021 17.16 ;
     RECT  14.677 18.24 16.021 18.264 ;
     RECT  16.021 17.136 16.028 18.264 ;
     RECT  16.028 17.136 16.115 19.176 ;
     RECT  16.115 17.136 16.121 18.264 ;
     RECT  14.645 6.384 16.124 6.408 ;
     RECT  15.149 3.696 16.153 3.768 ;
     RECT  16.013 9.312 16.157 9.672 ;
     RECT  15.977 2.304 16.337 2.328 ;
     RECT  16.153 15.984 16.613 16.008 ;
     RECT  16.121 17.136 16.613 17.16 ;
     RECT  15.757 12.528 16.621 12.552 ;
     RECT  16.369 7.776 16.691 7.8 ;
     RECT  16.613 15.984 16.697 17.16 ;
     RECT  16.124 6.24 16.7 6.408 ;
     RECT  16.7 5.376 16.787 6.408 ;
     RECT  16.621 12 16.796 12.552 ;
     RECT  15.977 13.632 16.796 14.856 ;
     RECT  16.153 3.696 16.933 3.96 ;
     RECT  16.796 12 17.053 14.856 ;
     RECT  16.697 15.984 17.053 16.008 ;
     RECT  16.121 18.24 17.075 18.264 ;
     RECT  16.801 10.848 17.093 10.872 ;
     RECT  15.587 0.192 17.125 0.264 ;
     RECT  16.787 5.712 17.165 6.408 ;
     RECT  17.153 19.296 17.18 19.32 ;
     RECT  16.697 17.088 17.197 17.16 ;
     RECT  17.053 12 17.219 16.008 ;
     RECT  16.765 7.488 17.221 7.512 ;
     RECT  17.219 14.064 17.273 16.008 ;
     RECT  17.125 0.192 17.309 1.176 ;
     RECT  17.309 0.576 17.317 1.176 ;
     RECT  17.221 7.392 17.345 7.512 ;
     RECT  16.157 9.312 17.413 9.576 ;
     RECT  16.933 2.448 17.485 3.96 ;
     RECT  17.273 14.064 17.533 15.432 ;
     RECT  17.317 0.576 17.597 1.224 ;
     RECT  17.485 2.4 17.653 3.96 ;
     RECT  17.653 2.4 17.701 4.584 ;
     RECT  17.597 0.576 17.843 0.6 ;
     RECT  17.219 12 17.845 13.08 ;
     RECT  17.845 11.952 17.893 13.08 ;
     RECT  17.197 17.088 18.037 17.64 ;
     RECT  17.701 1.728 18.181 4.584 ;
     RECT  17.165 6.048 18.181 6.408 ;
     RECT  17.893 11.328 18.349 13.08 ;
     RECT  18.349 10.896 18.385 13.08 ;
     RECT  18.181 1.728 18.457 6.408 ;
     RECT  17.345 7.392 18.457 7.416 ;
     RECT  17.413 9.312 18.493 9.672 ;
     RECT  17.18 19.2 18.505 19.32 ;
     RECT  18.457 1.728 18.605 7.416 ;
     RECT  18.605 2.016 18.608 7.416 ;
     RECT  18.493 8.976 18.608 9.672 ;
     RECT  18.385 10.8 18.608 13.08 ;
     RECT  17.533 14.064 18.608 14.952 ;
     RECT  18.037 17.088 18.608 17.496 ;
     RECT  18.608 2.016 18.611 17.496 ;
     RECT  18.611 2.148 18.712 17.496 ;
     RECT  18.712 2.418 18.904 17.496 ;
     RECT  18.469 0.192 18.949 0.216 ;
     RECT  18.853 18.768 18.949 18.792 ;
     RECT  18.904 17.088 19.033 17.496 ;
     RECT  18.949 18.672 19.043 18.792 ;
     RECT  18.904 3.072 19.145 5.208 ;
     RECT  18.904 14.208 19.145 16.008 ;
     RECT  18.904 6.768 19.427 10.296 ;
     RECT  18.949 0.192 19.429 0.264 ;
     RECT  19.033 17.088 19.525 17.64 ;
     RECT  19.429 0.192 19.577 0.552 ;
     RECT  19.145 14.208 19.577 15.528 ;
     RECT  19.525 17.088 19.649 17.688 ;
     RECT  19.427 8.496 19.811 10.296 ;
     RECT  19.145 3.072 19.829 4.68 ;
     RECT  19.427 6.768 19.909 7.416 ;
     RECT  19.909 6.72 19.955 7.416 ;
     RECT  19.043 18.672 20.005 18.696 ;
     RECT  18.904 11.424 20.077 11.448 ;
     RECT  19.577 14.208 20.153 14.904 ;
     RECT  20.005 18.24 20.153 18.84 ;
     RECT  19.811 8.544 20.221 10.296 ;
     RECT  20.077 11.424 20.221 11.64 ;
     RECT  20.221 8.544 20.333 11.64 ;
     RECT  20.153 18.24 20.339 18.264 ;
     RECT  19.717 1.728 20.368 1.752 ;
     RECT  19.829 3.888 20.369 4.68 ;
     RECT  20.333 10.896 20.369 11.64 ;
     RECT  19.955 6.72 20.441 6.84 ;
     RECT  20.369 11.424 20.477 11.64 ;
     RECT  20.153 14.208 20.545 14.232 ;
     RECT  19.649 17.088 20.645 17.112 ;
     RECT  20.369 4.656 21.053 4.68 ;
     RECT  20.368 1.728 21.089 1.8 ;
     RECT  19.577 0.192 21.157 0.36 ;
     RECT  21.089 1.728 21.157 1.752 ;
     RECT  20.333 8.544 21.161 9.768 ;
     RECT  20.477 11.616 21.161 11.64 ;
     RECT  20.645 17.088 21.299 17.64 ;
     RECT  21.157 0.192 21.341 1.752 ;
     RECT  21.299 17.088 21.587 17.16 ;
     RECT  20.545 13.632 21.593 14.232 ;
     RECT  21.625 15.936 21.709 15.96 ;
     RECT  21.692 6.48 21.733 6.504 ;
     RECT  21.301 7.872 21.733 7.896 ;
     RECT  21.589 11.952 21.773 12.552 ;
     RECT  21.733 6.48 21.779 7.896 ;
     RECT  21.161 9.312 21.985 9.768 ;
     RECT  21.733 5.04 22.097 5.064 ;
     RECT  21.985 9.312 22.129 10.248 ;
     RECT  21.341 0.192 22.241 0.6 ;
     RECT  21.587 17.136 22.373 17.16 ;
     RECT  21.779 6.816 22.385 7.32 ;
     RECT  22.129 9.072 22.561 10.248 ;
     RECT  22.385 6.816 22.595 6.84 ;
     RECT  22.373 17.136 22.597 17.64 ;
     RECT  22.165 18.768 22.597 18.792 ;
     RECT  22.381 13.584 22.625 13.608 ;
     RECT  22.501 5.136 22.741 5.736 ;
     RECT  22.625 13.584 22.741 14.28 ;
     RECT  22.561 9.072 22.777 10.44 ;
     RECT  22.597 16.992 22.777 17.64 ;
     RECT  22.597 18.672 22.777 18.792 ;
     RECT  21.773 11.952 22.805 11.976 ;
     RECT  22.741 5.136 22.883 6.264 ;
     RECT  22.741 13.056 22.885 14.28 ;
     RECT  22.241 0.288 22.889 0.6 ;
     RECT  22.883 5.136 22.889 5.736 ;
     RECT  22.805 11.424 22.889 11.976 ;
     RECT  22.777 8.544 22.913 10.44 ;
     RECT  22.889 5.136 22.925 5.16 ;
     RECT  22.525 15.408 22.933 15.432 ;
     RECT  22.913 8.448 22.997 10.44 ;
     RECT  22.777 16.992 23.027 18.792 ;
     RECT  21.341 1.728 23.077 1.752 ;
     RECT  22.933 15.408 23.125 16.008 ;
     RECT  23.027 16.992 23.125 17.64 ;
     RECT  22.885 3.264 23.237 3.288 ;
     RECT  23.125 15.408 23.353 17.64 ;
     RECT  23.027 18.768 23.533 18.792 ;
     RECT  23.353 7.392 23.569 7.416 ;
     RECT  23.077 1.728 23.845 1.848 ;
     RECT  23.237 2.88 23.845 3.288 ;
     RECT  23.569 6.864 23.845 7.416 ;
     RECT  22.889 11.808 23.929 11.976 ;
     RECT  23.557 0.192 23.941 0.216 ;
     RECT  22.997 8.544 23.965 10.44 ;
     RECT  23.929 11.664 23.965 11.976 ;
     RECT  23.533 18.768 23.987 18.84 ;
     RECT  23.845 1.728 24.008 3.288 ;
     RECT  23.497 4.512 24.008 4.536 ;
     RECT  23.845 6.192 24.008 7.416 ;
     RECT  23.965 8.544 24.008 11.976 ;
     RECT  22.885 12.96 24.008 14.328 ;
     RECT  23.353 15.36 24.008 17.64 ;
     RECT  23.941 0.192 24.185 0.552 ;
     RECT  24.008 1.728 24.304 17.64 ;
     RECT  24.304 1.728 24.419 15.432 ;
     RECT  24.419 1.728 24.437 14.232 ;
     RECT  24.437 1.728 24.46 7.944 ;
     RECT  24.304 16.992 24.545 17.64 ;
     RECT  24.437 8.976 24.611 14.232 ;
     RECT  24.419 15.408 24.707 15.432 ;
     RECT  24.46 1.728 24.797 7.272 ;
     RECT  24.797 1.728 24.905 5.976 ;
     RECT  24.185 0.192 25.013 0.408 ;
     RECT  24.905 1.728 25.139 2.712 ;
     RECT  24.905 3.888 25.139 5.976 ;
     RECT  25.139 3.888 25.193 5.16 ;
     RECT  24.797 6.96 25.283 7.272 ;
     RECT  23.987 18.816 25.513 18.84 ;
     RECT  24.611 8.976 25.571 13.08 ;
     RECT  24.611 14.208 25.649 14.232 ;
     RECT  25.193 3.888 25.715 4.872 ;
     RECT  25.571 8.976 25.769 12.504 ;
     RECT  25.283 6.96 25.837 6.984 ;
     RECT  25.837 6.24 25.877 6.984 ;
     RECT  25.513 18.768 25.907 18.84 ;
     RECT  24.545 17.088 26.029 17.64 ;
     RECT  25.715 3.888 26.129 3.912 ;
     RECT  25.907 18.768 26.291 18.792 ;
     RECT  25.013 0.192 26.341 0.312 ;
     RECT  25.139 1.728 26.525 1.752 ;
     RECT  26.341 0.192 26.821 0.6 ;
     RECT  25.877 6.24 26.837 6.264 ;
     RECT  26.593 18.24 26.867 18.36 ;
     RECT  25.649 14.208 26.917 14.808 ;
     RECT  26.837 5.712 26.921 6.264 ;
     RECT  25.769 8.976 26.957 12.072 ;
     RECT  26.867 18.336 26.963 18.36 ;
     RECT  26.917 14.208 27.001 14.856 ;
     RECT  26.029 17.088 27.109 17.16 ;
     RECT  27.001 14.208 27.317 14.232 ;
     RECT  26.957 8.976 27.425 11.88 ;
     RECT  26.821 0.192 27.497 1.176 ;
     RECT  26.809 7.92 27.709 7.944 ;
     RECT  27.425 8.976 27.709 11.352 ;
     RECT  27.709 7.92 27.749 11.352 ;
     RECT  27.109 16.416 27.829 17.16 ;
     RECT  27.809 1.248 27.893 1.272 ;
     RECT  27.889 18.768 27.925 18.792 ;
     RECT  27.749 8.4 27.929 11.352 ;
     RECT  27.925 18.768 28.011 18.84 ;
     RECT  27.925 3.072 28.021 3.096 ;
     RECT  28.011 18.768 28.033 18.888 ;
     RECT  27.565 13.056 28.073 13.08 ;
     RECT  27.497 0.192 28.145 0.264 ;
     RECT  28.105 14.4 28.172 14.424 ;
     RECT  28.021 3.072 28.213 3.432 ;
     RECT  28.033 18.72 28.259 18.936 ;
     RECT  27.829 15.984 28.277 17.16 ;
     RECT  28.213 3.072 28.285 3.48 ;
     RECT  28.285 2.448 28.309 3.48 ;
     RECT  28.309 1.728 28.321 3.48 ;
     RECT  26.921 6.24 28.349 6.264 ;
     RECT  28.145 0.24 28.361 0.264 ;
     RECT  28.259 18.72 28.397 18.888 ;
     RECT  28.321 1.728 28.501 4.008 ;
     RECT  28.349 6.192 28.501 6.264 ;
     RECT  28.172 14.4 28.597 14.856 ;
     RECT  28.277 15.984 29.041 17.64 ;
     RECT  28.597 13.968 29.077 14.856 ;
     RECT  29.041 15.984 29.077 18.216 ;
     RECT  28.285 12.528 29.125 12.552 ;
     RECT  29.077 13.968 29.125 18.216 ;
     RECT  28.501 1.728 29.221 4.296 ;
     RECT  28.501 5.376 29.221 6.264 ;
     RECT  29.221 1.728 29.269 6.84 ;
     RECT  27.929 9.168 29.269 11.352 ;
     RECT  29.269 1.728 29.408 11.352 ;
     RECT  29.125 12.528 29.408 18.216 ;
     RECT  29.408 1.728 29.653 18.216 ;
     RECT  29.653 1.728 29.704 18.84 ;
     RECT  29.704 13.92 29.843 14.856 ;
     RECT  29.221 0.288 29.941 0.312 ;
     RECT  29.704 17.088 29.981 18.84 ;
     RECT  29.704 15.984 29.989 16.104 ;
     RECT  29.704 9.888 30.089 11.928 ;
     RECT  29.981 17.088 30.179 18.264 ;
     RECT  29.704 1.728 30.227 4.44 ;
     RECT  30.227 3.888 30.275 4.44 ;
     RECT  30.227 1.728 30.305 2.904 ;
     RECT  29.989 15.984 30.313 16.008 ;
     RECT  29.704 6.864 30.467 7.8 ;
     RECT  30.467 7.44 30.652 7.8 ;
     RECT  30.275 3.984 30.697 4.44 ;
     RECT  29.843 14.256 30.773 14.856 ;
     RECT  30.697 3.984 30.781 4.536 ;
     RECT  29.941 0.192 30.805 0.312 ;
     RECT  30.089 11.232 30.989 11.928 ;
     RECT  30.805 0.192 31.061 0.36 ;
     RECT  30.305 1.728 31.091 2.712 ;
     RECT  30.773 14.256 31.097 14.28 ;
     RECT  30.089 9.888 31.309 10.056 ;
     RECT  31.061 0.336 31.379 0.36 ;
     RECT  30.989 11.904 31.385 11.928 ;
     RECT  31.333 5.808 31.421 5.832 ;
     RECT  30.179 17.088 31.525 17.208 ;
     RECT  31.525 17.088 31.669 17.256 ;
     RECT  30.179 18.24 31.669 18.264 ;
     RECT  31.309 9.168 31.705 10.056 ;
     RECT  31.705 9.072 31.789 10.056 ;
     RECT  31.091 1.728 32.069 2.184 ;
     RECT  31.669 17.088 32.099 18.264 ;
     RECT  31.345 15.456 32.173 15.48 ;
     RECT  31.789 9.168 32.177 10.056 ;
     RECT  32.099 17.088 32.291 17.64 ;
     RECT  32.069 1.728 32.393 1.848 ;
     RECT  32.393 1.824 32.401 1.848 ;
     RECT  32.053 0.576 32.429 0.6 ;
     RECT  32.173 14.928 32.437 15.48 ;
     RECT  32.437 14.928 32.483 16.008 ;
     RECT  32.533 19.2 32.569 19.224 ;
     RECT  32.483 14.928 32.581 14.952 ;
     RECT  32.569 19.2 32.62 19.32 ;
     RECT  30.652 7.44 32.681 7.464 ;
     RECT  32.483 15.984 32.681 16.008 ;
     RECT  32.581 14.496 32.713 14.952 ;
     RECT  30.781 3.984 32.749 4.056 ;
     RECT  32.749 3.984 32.789 4.248 ;
     RECT  32.177 10.032 33.037 10.056 ;
     RECT  33.037 10.032 33.217 10.872 ;
     RECT  32.789 4.224 33.325 4.248 ;
     RECT  33.217 9.072 33.329 10.872 ;
     RECT  32.291 17.616 33.361 17.64 ;
     RECT  33.205 2.304 33.397 2.328 ;
     RECT  32.965 7.488 33.397 7.512 ;
     RECT  32.713 14.256 33.577 14.952 ;
     RECT  32.533 0.192 33.589 0.216 ;
     RECT  33.577 14.208 33.637 14.952 ;
     RECT  33.361 17.616 33.644 18.264 ;
     RECT  32.62 19.296 33.644 19.32 ;
     RECT  32.173 6.144 33.653 6.168 ;
     RECT  33.325 4.224 33.685 5.16 ;
     RECT  33.644 17.616 33.689 19.32 ;
     RECT  33.637 13.632 33.725 14.952 ;
     RECT  33.689 17.616 33.731 19.224 ;
     RECT  33.001 16.56 33.749 16.632 ;
     RECT  33.731 17.616 33.749 18.264 ;
     RECT  33.397 7.488 33.761 8.472 ;
     RECT  33.685 4.224 33.937 6.12 ;
     RECT  33.749 16.56 34.213 18.264 ;
     RECT  33.397 1.728 34.225 2.328 ;
     RECT  33.937 3.408 34.225 6.12 ;
     RECT  34.213 15.984 34.307 18.264 ;
     RECT  33.589 0.192 34.541 0.312 ;
     RECT  34.541 0.192 34.625 0.6 ;
     RECT  34.021 13.104 34.657 13.128 ;
     RECT  34.657 12.528 34.693 13.128 ;
     RECT  34.625 0.192 34.769 0.312 ;
     RECT  34.225 1.728 34.808 6.12 ;
     RECT  33.761 7.968 34.808 8.472 ;
     RECT  33.329 9.6 34.808 10.872 ;
     RECT  34.693 11.952 34.808 13.128 ;
     RECT  33.725 14.112 34.808 14.952 ;
     RECT  34.307 15.984 34.808 17.64 ;
     RECT  34.808 1.728 35.104 17.64 ;
     RECT  35.104 16.08 35.165 17.64 ;
     RECT  35.153 19.296 35.18 19.32 ;
     RECT  35.104 5.184 35.219 5.784 ;
     RECT  35.104 7.392 35.219 11.448 ;
     RECT  35.219 7.392 35.237 10.824 ;
     RECT  35.18 19.104 35.237 19.32 ;
     RECT  35.237 19.104 35.267 19.224 ;
     RECT  35.219 5.184 35.315 5.592 ;
     RECT  35.267 19.104 35.315 19.128 ;
     RECT  35.237 7.392 35.603 10.296 ;
     RECT  35.509 18.768 35.747 18.792 ;
     RECT  35.104 13.92 35.813 15.048 ;
     RECT  34.769 0.192 35.873 0.216 ;
     RECT  35.104 1.728 35.873 2.664 ;
     RECT  35.813 14.448 35.891 15.048 ;
     RECT  35.104 12.528 35.921 12.552 ;
     RECT  35.873 0.192 35.957 2.664 ;
     RECT  35.165 17.04 35.993 17.64 ;
     RECT  35.603 9.12 36.101 10.296 ;
     RECT  36.133 12.912 36.275 13.416 ;
     RECT  35.957 0.192 36.277 0.216 ;
     RECT  35.957 1.728 36.277 2.664 ;
     RECT  35.603 7.392 36.313 7.848 ;
     RECT  35.993 17.088 36.313 17.64 ;
     RECT  36.277 1.728 36.461 2.904 ;
     RECT  35.891 14.448 36.569 14.856 ;
     RECT  36.557 6.288 36.641 6.312 ;
     RECT  36.313 17.088 36.707 18.312 ;
     RECT  36.707 17.088 36.803 18.216 ;
     RECT  36.275 13.392 36.853 13.416 ;
     RECT  35.315 5.184 37.177 5.208 ;
     RECT  36.313 7.344 37.177 7.848 ;
     RECT  36.101 9.36 37.177 10.296 ;
     RECT  36.461 1.728 37.181 2.184 ;
     RECT  37.177 7.344 37.253 10.296 ;
     RECT  36.853 13.392 37.325 14.28 ;
     RECT  37.325 13.392 37.357 13.8 ;
     RECT  36.803 17.088 37.379 17.304 ;
     RECT  37.181 1.728 37.397 1.8 ;
     RECT  37.253 7.344 37.429 8.568 ;
     RECT  37.237 15.36 37.429 15.384 ;
     RECT  37.379 17.088 37.429 17.208 ;
     RECT  36.277 0.048 37.621 0.216 ;
     RECT  37.253 9.648 37.681 10.296 ;
     RECT  37.429 15.36 37.757 17.208 ;
     RECT  37.681 9.648 37.763 10.872 ;
     RECT  37.357 12.864 37.789 13.8 ;
     RECT  37.763 10.224 37.829 10.872 ;
     RECT  37.429 7.296 37.865 8.568 ;
     RECT  37.621 0.048 37.973 0.264 ;
     RECT  37.973 0.048 38.051 0.216 ;
     RECT  36.925 6.24 38.06 6.264 ;
     RECT  38.06 6.192 38.185 6.264 ;
     RECT  37.177 5.136 38.221 5.208 ;
     RECT  37.865 7.872 38.243 8.568 ;
     RECT  37.789 12.144 38.3 13.8 ;
     RECT  38.149 18.816 38.341 18.84 ;
     RECT  38.221 4.464 38.401 5.208 ;
     RECT  38.185 6.192 38.401 6.84 ;
     RECT  38.341 18.816 38.437 18.888 ;
     RECT  37.757 15.408 38.509 17.208 ;
     RECT  38.473 3.12 38.533 3.144 ;
     RECT  38.437 18.816 38.579 18.936 ;
     RECT  38.533 3.12 38.581 3.48 ;
     RECT  38.401 4.464 38.581 6.84 ;
     RECT  37.397 1.728 38.617 1.752 ;
     RECT  38.581 3.12 38.617 6.84 ;
     RECT  38.579 18.864 38.693 18.936 ;
     RECT  38.243 8.4 38.797 8.568 ;
     RECT  37.829 10.224 38.797 10.296 ;
     RECT  38.693 18.912 38.867 18.936 ;
     RECT  38.797 8.4 38.909 10.296 ;
     RECT  38.909 10.224 38.917 10.296 ;
     RECT  38.3 11.52 38.917 13.8 ;
     RECT  38.617 1.728 38.977 6.84 ;
     RECT  38.917 10.224 39.013 13.8 ;
     RECT  38.509 15.408 39.013 17.64 ;
     RECT  39.013 19.2 39.049 19.224 ;
     RECT  39.049 19.2 39.133 19.32 ;
     RECT  38.051 0.192 39.193 0.216 ;
     RECT  39.193 0.192 39.337 0.504 ;
     RECT  39.337 0.192 39.397 0.552 ;
     RECT  38.977 1.728 39.397 6.888 ;
     RECT  39.397 0.192 39.625 6.888 ;
     RECT  38.909 8.4 39.625 9.096 ;
     RECT  39.013 10.224 39.685 17.64 ;
     RECT  39.625 0.192 39.845 9.096 ;
     RECT  39.845 0.288 40.021 9.096 ;
     RECT  39.685 10.224 40.021 17.688 ;
     RECT  39.877 18.816 40.025 18.84 ;
     RECT  40.021 0.288 40.403 17.688 ;
     RECT  40.403 1.68 40.504 17.688 ;
     RECT  40.504 1.68 40.565 1.752 ;
     RECT  40.504 4.512 40.643 4.536 ;
     RECT  40.504 7.68 40.643 7.896 ;
     RECT  40.504 14.4 40.643 16.008 ;
     RECT  40.504 17.376 40.645 17.688 ;
     RECT  40.643 14.736 40.673 16.008 ;
     RECT  40.643 7.872 40.681 7.896 ;
     RECT  40.673 15.408 40.691 16.008 ;
     RECT  40.403 0.288 40.717 0.6 ;
     RECT  40.717 0.288 40.739 0.552 ;
     RECT  40.504 5.712 40.739 6.12 ;
     RECT  40.504 10.608 40.739 11.448 ;
     RECT  40.504 3.312 40.745 3.336 ;
     RECT  40.739 11.232 40.745 11.448 ;
     RECT  40.691 15.408 40.753 15.48 ;
     RECT  40.565 1.728 40.787 1.752 ;
     RECT  40.739 6.096 40.787 6.12 ;
     RECT  40.745 11.424 40.787 11.448 ;
     RECT  40.645 17.376 40.817 18.792 ;
     RECT  40.753 15.456 40.853 15.48 ;
     RECT  40.817 17.616 40.853 18.792 ;
     RECT  40.739 0.528 40.979 0.552 ;
     RECT  40.853 17.616 40.979 17.64 ;
     RECT  40.504 12.768 40.997 12.792 ;
     RECT  40.853 18.768 41.069 18.792 ;
    LAYER M5 ;
     RECT  36.576 0.037 36.6 0.144 ;
     RECT  38.016 0.037 38.04 0.144 ;
     RECT  2.16 0.144 40.968 0.563 ;
     RECT  2.16 0.563 40.776 1.283 ;
     RECT  2.16 1.283 26.904 1.763 ;
     RECT  27.936 1.283 40.776 1.763 ;
     RECT  2.16 1.763 21 1.811 ;
     RECT  27.936 1.763 40.728 1.811 ;
     RECT  2.16 1.811 4.584 1.907 ;
     RECT  6.144 1.811 19.56 2.195 ;
     RECT  27.936 1.811 36.696 2.195 ;
     RECT  4.464 1.907 4.584 2.291 ;
     RECT  27.936 2.195 36.6 2.291 ;
     RECT  10.848 2.195 19.56 2.339 ;
     RECT  27.936 2.291 35.112 2.339 ;
     RECT  10.848 2.339 15.576 2.867 ;
     RECT  6.144 2.195 9.72 2.915 ;
     RECT  11.616 2.867 15.576 2.915 ;
     RECT  22.512 1.763 25.416 2.915 ;
     RECT  12.768 2.915 15.576 3.107 ;
     RECT  16.944 2.339 19.56 3.107 ;
     RECT  27.936 2.339 28.248 3.107 ;
     RECT  22.512 2.915 22.92 3.299 ;
     RECT  2.16 1.907 3.336 3.301 ;
     RECT  4.56 2.291 4.584 3.443 ;
     RECT  11.616 2.915 11.64 3.443 ;
     RECT  28.032 3.107 28.248 3.443 ;
     RECT  28.224 3.443 28.248 3.491 ;
     RECT  16.944 3.107 19.512 3.733 ;
     RECT  6.144 2.915 9.432 3.973 ;
     RECT  2.16 3.301 3.576 4.019 ;
     RECT  29.232 2.339 32.28 4.067 ;
     RECT  13.104 3.107 15.576 4.261 ;
     RECT  16.56 3.733 19.512 4.261 ;
     RECT  29.232 4.067 31.368 4.261 ;
     RECT  33.504 2.339 35.112 4.595 ;
     RECT  24 2.915 25.416 4.837 ;
     RECT  12.528 4.261 15.576 4.883 ;
     RECT  22.512 3.299 22.872 5.029 ;
     RECT  6.144 3.973 9.96 5.077 ;
     RECT  21.744 5.029 22.872 5.171 ;
     RECT  38.016 1.811 40.728 5.171 ;
     RECT  33.696 4.595 35.112 5.173 ;
     RECT  33.696 5.173 35.208 5.557 ;
     RECT  5.76 5.077 9.96 5.747 ;
     RECT  12.528 4.883 14.376 5.747 ;
     RECT  21.744 5.171 22.536 5.747 ;
     RECT  26.88 1.763 26.904 5.747 ;
     RECT  33.696 5.557 35.304 5.747 ;
     RECT  5.76 5.747 9.384 5.795 ;
     RECT  28.896 4.261 31.368 5.843 ;
     RECT  24 4.837 25.704 5.987 ;
     RECT  38.736 5.171 40.728 6.085 ;
     RECT  24 5.987 24.696 6.181 ;
     RECT  28.896 5.843 31.08 6.181 ;
     RECT  38.736 6.085 40.776 6.181 ;
     RECT  15.552 4.883 15.576 6.229 ;
     RECT  16.56 4.261 19.608 6.229 ;
     RECT  36.576 2.291 36.6 6.323 ;
     RECT  15.552 6.229 19.608 6.709 ;
     RECT  6.816 5.795 9.384 6.805 ;
     RECT  13.008 5.747 14.376 6.805 ;
     RECT  21.744 5.747 21.768 6.805 ;
     RECT  22.848 6.229 22.872 6.805 ;
     RECT  6.816 6.805 9.528 6.851 ;
     RECT  2.4 4.019 3.576 6.853 ;
     RECT  7.2 6.851 9.528 7.237 ;
     RECT  23.856 6.181 24.696 7.237 ;
     RECT  25.68 5.987 25.704 7.237 ;
     RECT  38.112 6.181 40.776 7.285 ;
     RECT  2.4 6.853 3.672 7.333 ;
     RECT  21.744 6.805 22.872 7.381 ;
     RECT  23.856 7.237 25.704 7.381 ;
     RECT  34.032 5.747 35.304 7.381 ;
     RECT  15.552 6.709 19.944 7.427 ;
     RECT  12.288 6.805 14.376 7.477 ;
     RECT  21.744 7.381 25.704 7.907 ;
     RECT  7.2 7.237 9.672 7.909 ;
     RECT  5.76 5.795 5.784 7.957 ;
     RECT  6.864 7.909 9.672 7.957 ;
     RECT  28.368 6.181 31.08 8.389 ;
     RECT  11.808 7.477 14.376 8.435 ;
     RECT  5.76 7.957 9.672 8.485 ;
     RECT  15.552 7.427 19.608 8.485 ;
     RECT  34.032 7.381 35.4 8.485 ;
     RECT  27.84 8.389 31.08 9.061 ;
     RECT  15.552 8.485 19.8 9.155 ;
     RECT  27.84 9.061 31.752 9.203 ;
     RECT  12.288 8.435 14.376 9.397 ;
     RECT  0.192 9.541 0.216 9.779 ;
     RECT  20.928 9.061 20.952 9.779 ;
     RECT  34.032 8.485 35.592 10.165 ;
     RECT  16.176 9.155 19.8 10.307 ;
     RECT  4.752 3.733 4.776 11.365 ;
     RECT  5.76 8.485 10.056 11.365 ;
     RECT  37.44 7.285 40.776 11.459 ;
     RECT  2.4 7.333 3.768 11.941 ;
     RECT  4.752 11.365 10.056 11.941 ;
     RECT  22.56 7.907 25.704 12.083 ;
     RECT  2.4 11.941 10.056 12.755 ;
     RECT  11.328 9.397 14.376 13.045 ;
     RECT  22.56 12.083 24.696 13.045 ;
     RECT  25.68 12.083 25.704 13.045 ;
     RECT  11.328 13.045 14.952 13.141 ;
     RECT  11.328 13.141 15.192 13.621 ;
     RECT  16.176 10.307 19.608 13.621 ;
     RECT  34.032 10.165 36.264 13.621 ;
     RECT  2.4 12.755 4.776 14.197 ;
     RECT  27.84 9.203 31.08 14.197 ;
     RECT  33.648 13.621 36.264 14.197 ;
     RECT  22.56 13.045 25.704 14.243 ;
     RECT  33.6 14.197 36.264 14.245 ;
     RECT  26.928 14.197 31.08 14.291 ;
     RECT  5.76 12.755 10.056 14.389 ;
     RECT  11.328 13.621 19.608 14.389 ;
     RECT  33.072 14.245 36.264 14.485 ;
     RECT  25.68 14.243 25.704 14.819 ;
     RECT  2.304 14.197 4.776 14.821 ;
     RECT  5.76 14.389 19.608 14.867 ;
     RECT  26.928 14.291 30.744 14.867 ;
     RECT  32.592 14.485 36.264 14.867 ;
     RECT  32.592 14.867 35.88 14.917 ;
     RECT  32.448 14.917 35.88 15.059 ;
     RECT  37.44 11.459 40.728 15.349 ;
     RECT  5.76 14.867 19.512 15.443 ;
     RECT  22.56 14.243 24.696 15.443 ;
     RECT  37.248 15.349 40.728 15.443 ;
     RECT  5.856 15.443 19.512 15.491 ;
     RECT  6.096 15.491 19.512 15.539 ;
     RECT  20.592 13.621 21.48 15.925 ;
     RECT  27.84 14.867 30.264 16.019 ;
     RECT  32.448 15.059 35.736 16.019 ;
     RECT  37.248 15.443 40.68 16.019 ;
     RECT  2.16 14.821 4.776 16.067 ;
     RECT  28.608 16.019 29.976 16.115 ;
     RECT  22.752 15.443 24.408 16.981 ;
     RECT  32.592 16.019 35.736 17.029 ;
     RECT  6.096 15.539 19.128 17.077 ;
     RECT  20.592 15.925 21.672 17.077 ;
     RECT  22.704 16.981 24.408 17.077 ;
     RECT  27.12 16.405 27.144 17.077 ;
     RECT  28.608 16.115 29.832 17.077 ;
     RECT  32.592 17.029 35.928 17.077 ;
     RECT  37.248 16.019 40.512 17.077 ;
     RECT  2.16 16.067 4.2 17.125 ;
     RECT  5.328 17.077 21.672 17.125 ;
     RECT  22.704 17.077 40.512 17.125 ;
     RECT  2.16 17.125 40.512 17.605 ;
     RECT  2.16 17.605 40.968 19.28 ;
     RECT  2.88 19.28 2.904 19.331 ;
     RECT  6.768 19.28 7.368 19.331 ;
     RECT  9.36 19.28 9.816 19.331 ;
     RECT  10.896 19.28 11.784 19.331 ;
     RECT  17.184 19.28 18.456 19.331 ;
     RECT  32.592 19.28 32.616 19.331 ;
     RECT  33.648 19.28 33.672 19.331 ;
     RECT  35.184 19.28 35.208 19.331 ;
     RECT  39.072 19.28 39.096 19.331 ;
     RECT  9.792 19.331 9.816 19.379 ;
     RECT  36.6 0.037 36.624 0.144 ;
     RECT  36.84 0.037 36.912 0.144 ;
     RECT  37.128 0.037 37.2 0.144 ;
     RECT  37.416 0.037 37.488 0.144 ;
     RECT  37.704 0.037 37.776 0.144 ;
     RECT  37.992 0.037 38.016 0.144 ;
     RECT  26.904 1.283 27.936 3.107 ;
     RECT  21 1.763 22.512 1.811 ;
     RECT  25.416 1.763 26.88 4.837 ;
     RECT  36.696 1.811 38.016 2.195 ;
     RECT  3.336 1.907 4.464 2.291 ;
     RECT  9.72 2.195 10.848 2.867 ;
     RECT  36.6 2.195 38.016 5.171 ;
     RECT  3.336 2.291 4.56 3.301 ;
     RECT  35.112 2.291 36.576 5.173 ;
     RECT  15.576 2.339 16.944 3.733 ;
     RECT  28.248 2.339 29.232 3.491 ;
     RECT  32.28 2.339 33.504 4.067 ;
     RECT  9.72 2.867 9.96 2.915 ;
     RECT  9.432 2.915 9.96 3.973 ;
     RECT  11.64 2.915 12.768 3.107 ;
     RECT  22.92 2.915 24 3.299 ;
     RECT  11.64 3.107 13.104 3.443 ;
     RECT  19.512 3.107 19.56 4.261 ;
     RECT  26.904 3.107 28.032 3.443 ;
     RECT  22.872 3.299 24 5.171 ;
     RECT  3.576 3.301 4.56 3.443 ;
     RECT  3.576 3.443 4.584 3.733 ;
     RECT  12.528 3.443 13.104 4.261 ;
     RECT  26.904 3.443 28.224 3.491 ;
     RECT  28.896 3.491 29.232 4.261 ;
     RECT  3.576 3.733 4.752 6.853 ;
     RECT  4.776 3.733 6.144 5.077 ;
     RECT  15.576 3.733 16.56 6.229 ;
     RECT  25.704 4.837 26.88 5.747 ;
     RECT  14.376 4.883 15.552 9.155 ;
     RECT  4.776 5.077 5.76 11.365 ;
     RECT  22.536 5.171 24 5.747 ;
     RECT  36.6 5.171 38.736 6.181 ;
     RECT  35.208 5.173 36.576 5.557 ;
     RECT  35.304 5.557 36.576 6.323 ;
     RECT  9.384 5.747 9.672 6.805 ;
     RECT  12.528 5.747 13.008 6.805 ;
     RECT  21.768 5.747 24 6.181 ;
     RECT  5.784 5.795 6.816 6.851 ;
     RECT  24.696 5.987 25.68 7.237 ;
     RECT  21.768 6.181 23.856 6.229 ;
     RECT  36.6 6.181 38.112 6.323 ;
     RECT  21.768 6.229 22.848 6.805 ;
     RECT  22.872 6.229 23.856 7.381 ;
     RECT  35.304 6.323 35.4 7.381 ;
     RECT  37.44 6.323 38.112 7.285 ;
     RECT  9.528 6.805 9.672 7.237 ;
     RECT  5.784 6.851 7.2 7.909 ;
     RECT  3.672 6.853 4.752 7.333 ;
     RECT  3.768 7.333 4.752 11.941 ;
     RECT  19.608 7.427 19.8 8.485 ;
     RECT  5.784 7.909 6.864 7.957 ;
     RECT  11.808 8.435 12.288 9.397 ;
     RECT  19.8 9.061 20.928 9.779 ;
     RECT  10.056 9.397 11.328 14.389 ;
     RECT  36.264 10.165 37.44 14.867 ;
     RECT  24.696 12.083 25.68 13.045 ;
     RECT  4.776 12.755 5.76 15.443 ;
     RECT  14.952 13.045 16.176 13.141 ;
     RECT  15.192 13.141 16.176 13.621 ;
     RECT  19.608 13.621 20.592 14.867 ;
     RECT  21.48 13.621 22.56 15.443 ;
     RECT  25.704 14.197 26.928 14.819 ;
     RECT  24.696 14.243 25.68 14.819 ;
     RECT  19.512 14.867 20.592 15.539 ;
     RECT  35.88 14.867 37.44 15.059 ;
     RECT  35.736 15.059 37.44 15.349 ;
     RECT  35.736 15.349 37.248 17.029 ;
     RECT  4.776 15.443 5.856 15.491 ;
     RECT  21.48 15.443 22.752 15.925 ;
     RECT  4.776 15.491 6.096 16.067 ;
     RECT  19.128 15.539 20.592 17.077 ;
     RECT  21.672 15.925 22.752 16.981 ;
     RECT  27.84 16.019 28.608 16.405 ;
     RECT  29.976 16.019 30.264 16.115 ;
     RECT  32.448 16.019 32.592 17.077 ;
     RECT  4.2 16.067 6.096 17.077 ;
     RECT  29.832 16.115 30.264 17.077 ;
     RECT  27.144 16.405 28.608 17.077 ;
     RECT  21.672 16.981 22.704 17.125 ;
     RECT  35.928 17.029 37.248 17.077 ;
     RECT  4.2 17.077 5.328 17.125 ;
     RECT  9.816 19.28 9.84 19.331 ;
     RECT  10.056 19.28 10.128 19.331 ;
     RECT  10.344 19.28 10.416 19.331 ;
     RECT  10.632 19.28 10.704 19.331 ;
     RECT  32.616 19.28 33.168 19.331 ;
     RECT  34.44 19.28 34.512 19.331 ;
     RECT  34.824 19.28 34.896 19.331 ;
     RECT  35.112 19.28 35.184 19.331 ;
  END
END dsfd_vm_frm
END LIBRARY
